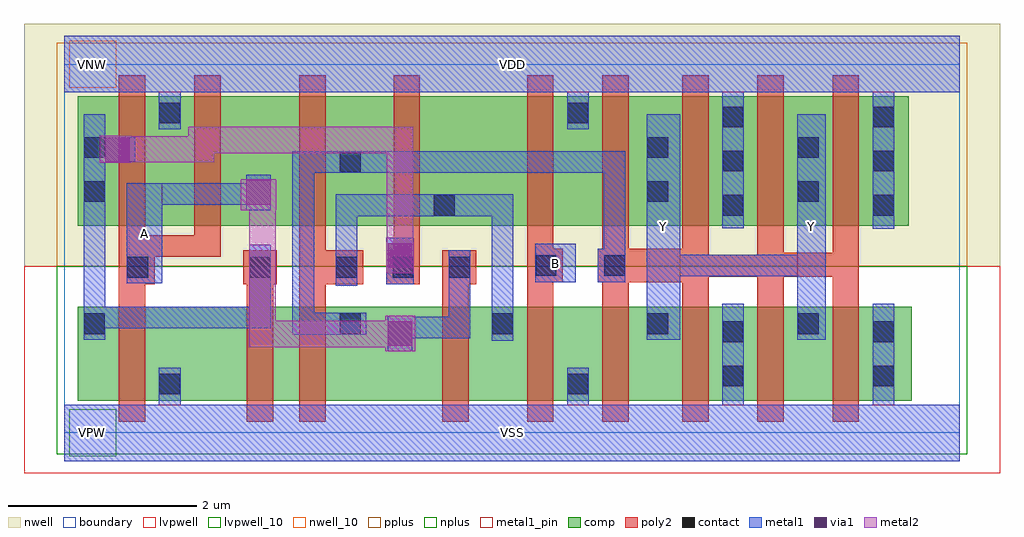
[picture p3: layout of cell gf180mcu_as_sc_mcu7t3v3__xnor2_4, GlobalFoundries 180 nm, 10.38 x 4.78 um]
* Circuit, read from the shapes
.subckt gf180mcu_as_sc_mcu7t3v3__xnor2_4 A B VDD VNW VSS Y
XM1 VSS A n1 VSUBS nfet_03v3 w=1u l=0.28u
XM2 n2 n1 VSS VSUBS nfet_03v3 w=1u l=0.28u
XM3 n3 n4 n2 VSUBS nfet_03v3 w=1u l=0.28u
XM4 n4 A n3 VSUBS nfet_03v3 w=1u l=0.28u
XM5 VSS B n4 VSUBS nfet_03v3 w=1u l=0.28u
XM6 Y n3 VSS VSUBS nfet_03v3 w=1u l=0.28u m=4
XM7 VDD A n1 VNW pfet_03v3 w=1.38u l=0.28u
XM8 n5 A VDD VNW pfet_03v3 w=1.38u l=0.28u
XM9 n3 n4 n5 VNW pfet_03v3 w=1.38u l=0.28u
XM10 n4 n1 n3 VNW pfet_03v3 w=1.38u l=0.28u
XM11 VDD B n4 VNW pfet_03v3 w=1.38u l=0.28u
XM12 Y n3 VDD VNW pfet_03v3 w=1.38u l=0.28u m=4
.ends

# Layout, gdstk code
import gdstk
lib = gdstk.Library(unit=1e-6, precision=1e-09)
def R(c, l, rs):  # rectangles x0, y0, x1, y1
    for r in rs: c.add(gdstk.rectangle(r[:2], r[2:], *l))
boundary = (0, 0)
nwell = (21, 0)
nwell_10 = (21, 10)
comp = (22, 0)
poly2 = (30, 0)
pplus = (31, 0)
nplus = (32, 0)
contact = (33, 0)
metal1 = (34, 0)
metal1_pin = (34, 10)
via1 = (35, 0)
metal2 = (36, 0)
lvpwell = (204, 0)
lvpwell_10 = (204, 10)

gf180mcu_as_sc_mcu7t3v3_ = lib.new_cell('gf180mcu_as_sc_mcu7t3v3__xnor2_4')
R(gf180mcu_as_sc_mcu7t3v3_, boundary, [(0,0,9.52,3.92), (0,0,9.52,3.92)])
R(gf180mcu_as_sc_mcu7t3v3_, nwell, [(-0.43,1.77,9.95,4.35), (-0.43,1.77,9.95,4.35)])
R(gf180mcu_as_sc_mcu7t3v3_, nwell_10, [(0.05,3.67,0.55,4.17), (0.05,3.67,0.55,4.17)])
R(gf180mcu_as_sc_mcu7t3v3_, comp, [(0.14,0.34,9.01,1.34), (0.14,0.34,9.01,1.34), (0.14,2.2,8.98,3.58), (0.14,2.2,8.98,3.58)])
R(gf180mcu_as_sc_mcu7t3v3_, poly2, [(0.58,0.12,0.86,1.58), (0.58,0.12,0.86,1.58), (1.94,0.12,2.22,1.58), (1.94,0.12,2.22,1.58), (2.5,0.12,2.78,1.58), (2.5,0.12,2.78,1.58), (4.02,0.12,4.3,1.58), (4.02,0.12,4.3,1.58), (4.92,0.12,5.2,1.6), (4.92,0.12,5.2,1.6), (5.72,0.12,6,1.6), (5.72,0.12,6,1.6), (6.57,0.12,6.85,1.6), (6.57,0.12,6.85,1.6), (7.37,0.12,7.65,1.66), (7.37,0.12,7.65,1.66), (8.17,0.12,8.45,1.66), (8.17,0.12,8.45,1.66), (0.58,1.58,0.96,1.87), (0.58,1.58,0.96,1.87), (1.9,1.58,2.26,1.94), (1.9,1.58,2.26,1.94), (2.5,1.58,3.18,1.94), (2.5,1.58,3.18,1.94), (3.42,1.58,3.78,1.94), (3.42,1.58,3.78,1.94), (4.02,1.58,4.38,1.94), (4.02,1.58,4.38,1.94), (4.92,1.6,5.3,1.96), (4.92,1.6,5.3,1.96), (5.67,1.6,6.85,1.66), (5.67,1.6,6.85,1.66), (5.67,1.66,8.45,1.895), (5.67,1.66,8.45,1.895), (0.58,1.87,1.66,2.1), (0.58,1.87,1.66,2.1), (5.67,1.895,6.85,1.96), (5.67,1.895,6.85,1.96), (7.37,1.895,8.45,1.915), (7.37,1.895,8.45,1.915), (7.37,1.915,7.65,3.8), (7.37,1.915,7.65,3.8), (8.17,1.915,8.45,3.8), (8.17,1.915,8.45,3.8), (2.5,1.94,2.78,3.8), (2.5,1.94,2.78,3.8), (3.5,1.94,3.78,3.8), (3.5,1.94,3.78,3.8), (4.92,1.96,5.2,3.8), (4.92,1.96,5.2,3.8), (5.72,1.96,6,3.8), (5.72,1.96,6,3.8), (6.57,1.96,6.85,3.8), (6.57,1.96,6.85,3.8), (0.58,2.1,0.86,3.8), (0.58,2.1,0.86,3.8), (1.38,2.1,1.66,3.8), (1.38,2.1,1.66,3.8)])
R(gf180mcu_as_sc_mcu7t3v3_, pplus, [(-0.08,1.77,9.6,4.15), (-0.08,1.77,9.6,4.15), (0.35,1.97,4.01,2.04), (0.35,1.97,4.01,2.04), (4.69,1.97,8.68,2.04), (4.69,1.97,8.68,2.04), (-0.02,2.04,9.14,3.74), (-0.02,2.04,9.14,3.74), (0.35,3.74,4.01,3.81), (0.35,3.74,4.01,3.81), (4.69,3.74,8.68,3.81), (4.69,3.74,8.68,3.81)])
R(gf180mcu_as_sc_mcu7t3v3_, nplus, [(-0.08,-0.23,9.6,1.77), (-0.08,-0.23,9.6,1.77), (-0.08,-0.23,9.6,1.77), (-0.08,-0.23,9.6,1.77)])
R(gf180mcu_as_sc_mcu7t3v3_, contact, [(1.01,0.41,1.23,0.63), (1.01,0.41,1.23,0.63), (5.35,0.41,5.57,0.63), (5.35,0.41,5.57,0.63), (7,0.495,7.22,0.715), (7,0.495,7.22,0.715), (8.6,0.495,8.82,0.715), (8.6,0.495,8.82,0.715), (7,0.965,7.22,1.185), (7,0.965,7.22,1.185), (8.6,0.965,8.82,1.185), (8.6,0.965,8.82,1.185), (0.21,1.05,0.43,1.27), (0.21,1.05,0.43,1.27), (2.93,1.05,3.15,1.27), (2.93,1.05,3.15,1.27), (4.55,1.05,4.77,1.27), (4.55,1.05,4.77,1.27), (6.2,1.05,6.42,1.27), (6.2,1.05,6.42,1.27), (7.8,1.05,8.02,1.27), (7.8,1.05,8.02,1.27), (0.67,1.65,0.89,1.87), (0.67,1.65,0.89,1.87), (1.97,1.65,2.19,1.87), (1.97,1.65,2.19,1.87), (2.89,1.65,3.11,1.87), (2.89,1.65,3.11,1.87), (3.49,1.65,3.71,1.87), (3.49,1.65,3.71,1.87), (4.09,1.65,4.31,1.87), (4.09,1.65,4.31,1.87), (5.01,1.67,5.23,1.89), (5.01,1.67,5.23,1.89), (5.74,1.67,5.96,1.89), (5.74,1.67,5.96,1.89), (3.93,2.31,4.15,2.53), (3.93,2.31,4.15,2.53), (7,2.31,7.22,2.53), (7,2.31,7.22,2.53), (8.6,2.31,8.82,2.53), (8.6,2.31,8.82,2.53), (0.21,2.455,0.43,2.675), (0.21,2.455,0.43,2.675), (6.2,2.455,6.42,2.675), (6.2,2.455,6.42,2.675), (7.8,2.455,8.02,2.675), (7.8,2.455,8.02,2.675), (2.93,2.77,3.15,2.99), (2.93,2.77,3.15,2.99), (7,2.78,7.22,3), (7,2.78,7.22,3), (8.6,2.78,8.82,3), (8.6,2.78,8.82,3), (0.21,2.925,0.43,3.145), (0.21,2.925,0.43,3.145), (6.2,2.925,6.42,3.145), (6.2,2.925,6.42,3.145), (7.8,2.925,8.02,3.145), (7.8,2.925,8.02,3.145), (7,3.25,7.22,3.47), (7,3.25,7.22,3.47), (8.6,3.25,8.82,3.47), (8.6,3.25,8.82,3.47), (1.01,3.29,1.23,3.51), (1.01,3.29,1.23,3.51), (5.35,3.29,5.57,3.51), (5.35,3.29,5.57,3.51)])
R(gf180mcu_as_sc_mcu7t3v3_, metal1, [(0,-0.3,9.52,0.3), (0,-0.3,9.52,0.3), (1.005,0.3,1.235,0.69), (1.005,0.3,1.235,0.69), (5.345,0.3,5.575,0.69), (5.345,0.3,5.575,0.69), (6.995,0.3,7.225,1.375), (6.995,0.3,7.225,1.375), (8.595,0.3,8.825,1.375), (8.595,0.3,8.825,1.375), (3.44,0.865,3.7,1.005), (3.44,0.865,3.7,1.005), (4.545,0.98,4.775,2.305), (4.545,0.98,4.775,2.305), (0.205,0.99,0.435,1.11), (0.205,0.99,0.435,1.11), (6.195,0.99,6.55,1.665), (6.195,0.99,6.55,1.665), (7.795,0.99,8.095,1.665), (7.795,0.99,8.095,1.665), (3.44,1.005,4.315,1.235), (3.44,1.005,4.315,1.235), (2.425,1.045,3.21,1.275), (2.425,1.045,3.21,1.275), (0.205,1.11,2.195,1.34), (0.205,1.11,2.195,1.34), (3.44,1.235,3.7,1.245), (3.44,1.235,3.7,1.245), (4.085,1.235,4.315,1.94), (4.085,1.235,4.315,1.94), (2.425,1.275,2.655,2.765), (2.425,1.275,2.655,2.765), (0.205,1.34,0.435,2.885), (0.205,1.34,0.435,2.885), (1.965,1.34,2.195,2), (1.965,1.34,2.195,2), (2.885,1.565,3.115,2.305), (2.885,1.565,3.115,2.305), (3.42,1.58,3.715,2.075), (3.42,1.58,3.715,2.075), (0.665,1.59,1.04,2.425), (0.665,1.59,1.04,2.425), (5.005,1.6,5.44,2.01), (5.005,1.6,5.44,2.01), (5.67,1.6,5.965,1.96), (5.67,1.6,5.965,1.96), (6.195,1.665,8.095,1.895), (6.195,1.665,8.095,1.895), (6.195,1.895,6.55,3.39), (6.195,1.895,6.55,3.39), (7.795,1.895,8.095,3.39), (7.795,1.895,8.095,3.39), (5.735,1.96,5.965,2.765), (5.735,1.96,5.965,2.765), (8.595,2.17,8.825,3.62), (8.595,2.17,8.825,3.62), (6.995,2.175,7.225,3.62), (6.995,2.175,7.225,3.62), (2.885,2.305,4.775,2.535), (2.885,2.305,4.775,2.535), (1.935,2.365,2.195,2.425), (1.935,2.365,2.195,2.425), (0.665,2.425,2.195,2.655), (0.665,2.425,2.195,2.655), (1.935,2.655,2.195,2.745), (1.935,2.655,2.195,2.745), (2.425,2.765,5.965,2.995), (2.425,2.765,5.965,2.995), (0.205,2.885,0.755,3.145), (0.205,2.885,0.755,3.145), (0.205,3.145,0.435,3.39), (0.205,3.145,0.435,3.39), (1.005,3.23,1.235,3.62), (1.005,3.23,1.235,3.62), (5.345,3.23,5.575,3.62), (5.345,3.23,5.575,3.62), (0,3.62,9.52,4.22), (0,3.62,9.52,4.22)])
R(gf180mcu_as_sc_mcu7t3v3_, metal1_pin, [(0,-0.3,9.52,0.3), (0,-0.3,9.52,0.3), (6.195,0.99,6.55,3.39), (6.195,0.99,6.55,3.39), (7.795,0.99,8.095,3.39), (7.795,0.99,8.095,3.39), (0.665,1.59,1.04,2.655), (0.665,1.59,1.04,2.655), (5.005,1.6,5.44,2.01), (5.005,1.6,5.44,2.01), (0,3.62,9.52,4.22), (0,3.62,9.52,4.22)])
R(gf180mcu_as_sc_mcu7t3v3_, via1, [(3.44,0.925,3.7,1.185), (3.44,0.925,3.7,1.185), (3.44,1.755,3.7,2.015), (3.44,1.755,3.7,2.015), (1.935,2.425,2.195,2.685), (1.935,2.425,2.195,2.685), (0.435,2.885,0.695,3.145), (0.435,2.885,0.695,3.145)])
R(gf180mcu_as_sc_mcu7t3v3_, metal2, [(3.41,0.865,3.73,0.91), (3.41,0.865,3.73,0.91), (1.965,0.91,3.73,1.19), (1.965,0.91,3.73,1.19), (1.965,1.19,2.245,2.365), (1.965,1.19,2.245,2.365), (3.41,1.19,3.73,1.245), (3.41,1.19,3.73,1.245), (3.42,1.695,3.715,2.03), (3.42,1.695,3.715,2.03), (3.43,2.03,3.71,2.975), (3.43,2.03,3.71,2.975), (1.875,2.365,2.255,2.695), (1.875,2.365,2.255,2.695), (0.375,2.87,0.71,2.875), (0.375,2.87,0.71,2.875), (0.375,2.875,1.595,2.975), (0.375,2.875,1.595,2.975), (0.375,2.975,3.71,3.155), (0.375,2.975,3.71,3.155), (0.375,3.155,0.71,3.16), (0.375,3.155,0.71,3.16), (1.315,3.155,3.71,3.255), (1.315,3.155,3.71,3.255)])
R(gf180mcu_as_sc_mcu7t3v3_, lvpwell, [(-0.43,-0.43,9.95,1.77), (-0.43,-0.43,9.95,1.77)])
R(gf180mcu_as_sc_mcu7t3v3_, lvpwell_10, [(0.05,-0.25,0.55,0.25), (0.05,-0.25,0.55,0.25)])
gf180mcu_as_sc_mcu7t3v3_.add(gdstk.Label('VDD', (4.76,3.92), layer=34, texttype=10))
gf180mcu_as_sc_mcu7t3v3_.add(gdstk.Label('VSS', (4.76,0), layer=34, texttype=10))
gf180mcu_as_sc_mcu7t3v3_.add(gdstk.Label('B', (5.222,1.805), layer=34, texttype=10))
gf180mcu_as_sc_mcu7t3v3_.add(gdstk.Label('A', (0.852,2.122), layer=34, texttype=10))
gf180mcu_as_sc_mcu7t3v3_.add(gdstk.Label('Y', (7.945,2.19), layer=34, texttype=10))
gf180mcu_as_sc_mcu7t3v3_.add(gdstk.Label('Y', (6.372,2.19), layer=34, texttype=10))
gf180mcu_as_sc_mcu7t3v3_.add(gdstk.Label('VDD', (4.76,3.92), layer=34, texttype=10))
gf180mcu_as_sc_mcu7t3v3_.add(gdstk.Label('VSS', (4.76,0), layer=34, texttype=10))
gf180mcu_as_sc_mcu7t3v3_.add(gdstk.Label('B', (5.222,1.805), layer=34, texttype=10))
gf180mcu_as_sc_mcu7t3v3_.add(gdstk.Label('A', (0.852,2.122), layer=34, texttype=10))
gf180mcu_as_sc_mcu7t3v3_.add(gdstk.Label('Y', (7.945,2.19), layer=34, texttype=10))
gf180mcu_as_sc_mcu7t3v3_.add(gdstk.Label('Y', (6.372,2.19), layer=34, texttype=10))
gf180mcu_as_sc_mcu7t3v3_.add(gdstk.Label('VNW', (0.3,3.92), layer=21, texttype=10))
gf180mcu_as_sc_mcu7t3v3_.add(gdstk.Label('VNW', (0.3,3.92), layer=21, texttype=10))
gf180mcu_as_sc_mcu7t3v3_.add(gdstk.Label('VPW', (0.3,0), layer=204, texttype=10))
gf180mcu_as_sc_mcu7t3v3_.add(gdstk.Label('VPW', (0.3,0), layer=204, texttype=10))

lib.write_gds('gf180mcu_as_sc_mcu7t3v3__xnor2_4.gds')
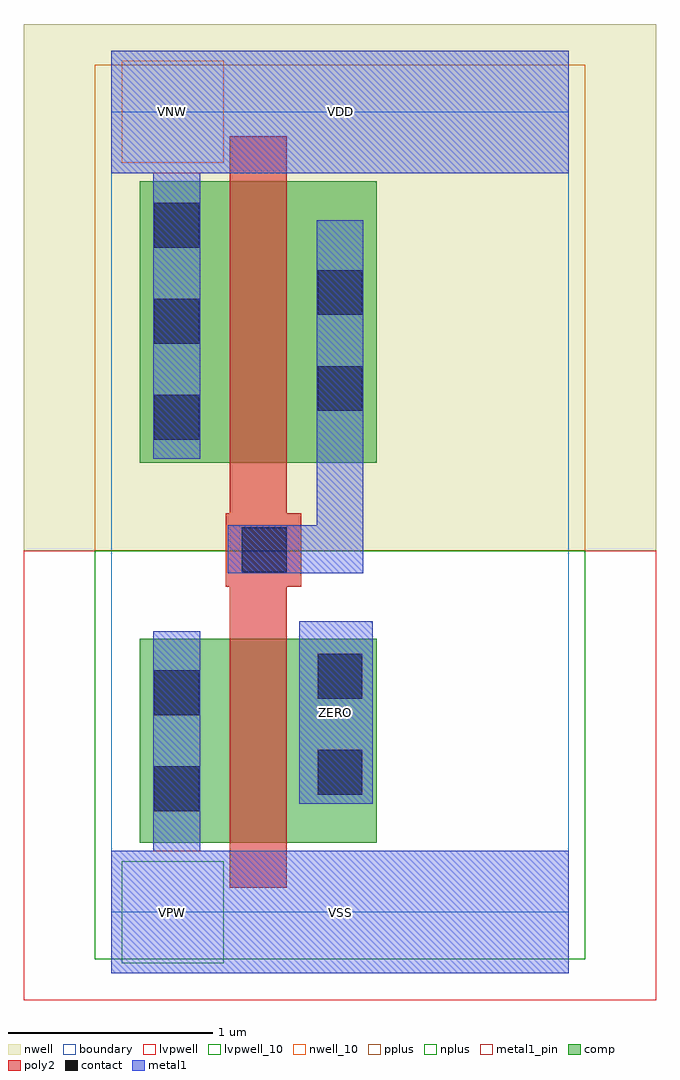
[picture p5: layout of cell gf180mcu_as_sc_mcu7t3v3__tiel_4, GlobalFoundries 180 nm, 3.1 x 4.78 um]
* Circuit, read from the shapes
.subckt gf180mcu_as_sc_mcu7t3v3__tiel_4 VDD VNW VSS ZERO
XM1 ZERO n1 VSS VSUBS nfet_03v3 w=1u l=0.28u
XM2 n1 n1 VDD VNW pfet_03v3 w=1.38u l=0.28u
.ends

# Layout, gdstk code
import gdstk
lib = gdstk.Library(unit=1e-6, precision=1e-09)
def R(c, l, rs):  # rectangles x0, y0, x1, y1
    for r in rs: c.add(gdstk.rectangle(r[:2], r[2:], *l))
boundary = (0, 0)
nwell = (21, 0)
nwell_10 = (21, 10)
comp = (22, 0)
poly2 = (30, 0)
pplus = (31, 0)
nplus = (32, 0)
contact = (33, 0)
metal1 = (34, 0)
metal1_pin = (34, 10)
lvpwell = (204, 0)
lvpwell_10 = (204, 10)

gf180mcu_as_sc_mcu7t3v3_ = lib.new_cell('gf180mcu_as_sc_mcu7t3v3__tiel_4')
R(gf180mcu_as_sc_mcu7t3v3_, boundary, [(0,0,2.24,3.92), (0,0,2.24,3.92)])
R(gf180mcu_as_sc_mcu7t3v3_, nwell, [(-0.43,1.77,2.67,4.35), (-0.43,1.77,2.67,4.35)])
R(gf180mcu_as_sc_mcu7t3v3_, nwell_10, [(0.05,3.67,0.55,4.17), (0.05,3.67,0.55,4.17)])
R(gf180mcu_as_sc_mcu7t3v3_, comp, [(0.14,0.34,1.3,1.34), (0.14,0.34,1.3,1.34), (0.14,2.2,1.3,3.58), (0.14,2.2,1.3,3.58)])
R(gf180mcu_as_sc_mcu7t3v3_, poly2, [(0.58,0.12,0.86,1.595), (0.58,0.12,0.86,1.595), (0.56,1.595,0.93,1.955), (0.56,1.595,0.93,1.955), (0.58,1.955,0.86,3.8), (0.58,1.955,0.86,3.8)])
R(gf180mcu_as_sc_mcu7t3v3_, pplus, [(-0.08,1.77,2.32,4.15), (-0.08,1.77,2.32,4.15), (0.35,1.97,1.09,2.04), (0.35,1.97,1.09,2.04), (-0.02,2.04,1.46,3.74), (-0.02,2.04,1.46,3.74), (0.35,3.74,1.09,3.81), (0.35,3.74,1.09,3.81)])
R(gf180mcu_as_sc_mcu7t3v3_, nplus, [(-0.08,-0.23,2.32,1.77), (-0.08,-0.23,2.32,1.77), (-0.08,-0.23,2.32,1.77), (-0.08,-0.23,2.32,1.77)])
R(gf180mcu_as_sc_mcu7t3v3_, contact, [(0.21,0.495,0.43,0.715), (0.21,0.495,0.43,0.715), (1.01,0.575,1.23,0.795), (1.01,0.575,1.23,0.795), (0.21,0.965,0.43,1.185), (0.21,0.965,0.43,1.185), (1.01,1.045,1.23,1.265), (1.01,1.045,1.23,1.265), (0.64,1.665,0.86,1.885), (0.64,1.665,0.86,1.885), (0.21,2.315,0.43,2.535), (0.21,2.315,0.43,2.535), (1.01,2.455,1.23,2.675), (1.01,2.455,1.23,2.675), (0.21,2.785,0.43,3.005), (0.21,2.785,0.43,3.005), (1.01,2.925,1.23,3.145), (1.01,2.925,1.23,3.145), (0.21,3.255,0.43,3.475), (0.21,3.255,0.43,3.475)])
R(gf180mcu_as_sc_mcu7t3v3_, metal1, [(0,-0.3,2.24,0.3), (0,-0.3,2.24,0.3), (0.205,0.3,0.435,1.375), (0.205,0.3,0.435,1.375), (0.92,0.53,1.28,1.425), (0.92,0.53,1.28,1.425), (0.57,1.66,1.235,1.895), (0.57,1.66,1.235,1.895), (1.005,1.895,1.235,3.39), (1.005,1.895,1.235,3.39), (0.205,2.22,0.435,3.62), (0.205,2.22,0.435,3.62), (0,3.62,2.24,4.22), (0,3.62,2.24,4.22)])
R(gf180mcu_as_sc_mcu7t3v3_, metal1_pin, [(0,-0.3,2.24,0.3), (0,-0.3,2.24,0.3), (0.92,0.53,1.28,1.425), (0.92,0.53,1.28,1.425), (0,3.62,2.24,4.22), (0,3.62,2.24,4.22)])
R(gf180mcu_as_sc_mcu7t3v3_, lvpwell, [(-0.43,-0.43,2.67,1.77), (-0.43,-0.43,2.67,1.77)])
R(gf180mcu_as_sc_mcu7t3v3_, lvpwell_10, [(0.05,-0.25,0.55,0.25), (0.05,-0.25,0.55,0.25)])
gf180mcu_as_sc_mcu7t3v3_.add(gdstk.Label('VDD', (1.12,3.92), layer=34, texttype=10))
gf180mcu_as_sc_mcu7t3v3_.add(gdstk.Label('VSS', (1.12,0), layer=34, texttype=10))
gf180mcu_as_sc_mcu7t3v3_.add(gdstk.Label('ZERO', (1.1,0.977), layer=34, texttype=10))
gf180mcu_as_sc_mcu7t3v3_.add(gdstk.Label('VDD', (1.12,3.92), layer=34, texttype=10))
gf180mcu_as_sc_mcu7t3v3_.add(gdstk.Label('VSS', (1.12,0), layer=34, texttype=10))
gf180mcu_as_sc_mcu7t3v3_.add(gdstk.Label('ZERO', (1.1,0.977), layer=34, texttype=10))
gf180mcu_as_sc_mcu7t3v3_.add(gdstk.Label('VNW', (0.3,3.92), layer=21, texttype=10))
gf180mcu_as_sc_mcu7t3v3_.add(gdstk.Label('VNW', (0.3,3.92), layer=21, texttype=10))
gf180mcu_as_sc_mcu7t3v3_.add(gdstk.Label('VPW', (0.3,0), layer=204, texttype=10))
gf180mcu_as_sc_mcu7t3v3_.add(gdstk.Label('VPW', (0.3,0), layer=204, texttype=10))

lib.write_gds('gf180mcu_as_sc_mcu7t3v3__tiel_4.gds')
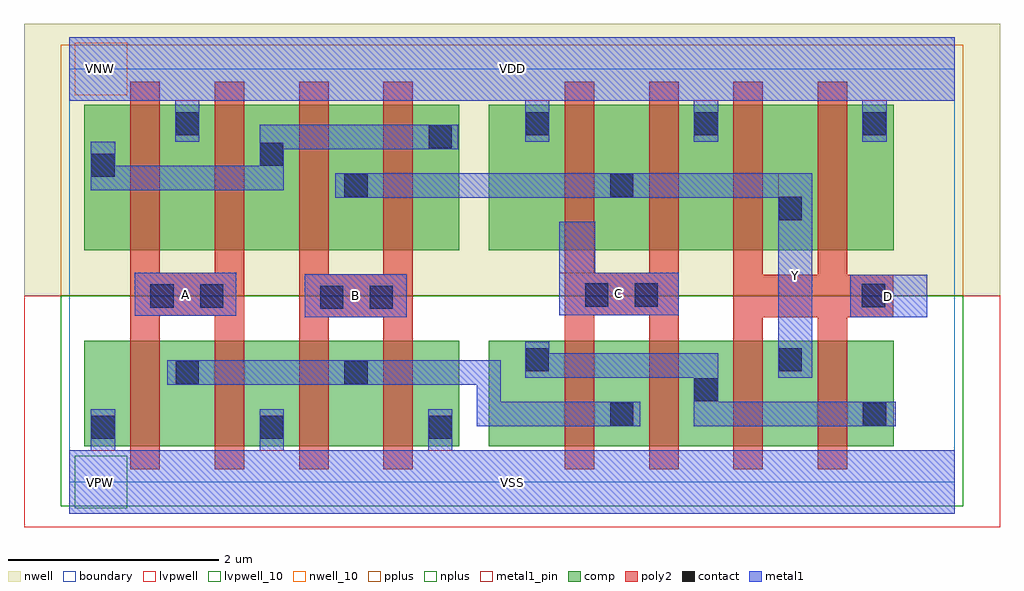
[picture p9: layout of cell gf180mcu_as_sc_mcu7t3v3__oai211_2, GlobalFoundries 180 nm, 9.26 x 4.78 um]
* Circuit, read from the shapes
.subckt gf180mcu_as_sc_mcu7t3v3__oai211_2 A B C D VDD VNW VSS Y
XM1 n1 A VSS VSUBS nfet_03v3 w=1u l=0.28u m=2
XM2 n1 B VSS VSUBS nfet_03v3 w=1u l=0.28u m=2
XM3 n1 C n2 VSUBS nfet_03v3 w=1u l=0.28u m=2
XM4 Y D n2 VSUBS nfet_03v3 w=1u l=0.28u m=2
XM5 VDD A n3 VNW pfet_03v3 w=1.38u l=0.28u m=2
XM6 Y B n3 VNW pfet_03v3 w=1.38u l=0.28u m=2
XM7 Y C VDD VNW pfet_03v3 w=1.38u l=0.28u m=2
XM8 Y D VDD VNW pfet_03v3 w=1.38u l=0.28u m=2
.ends

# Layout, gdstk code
import gdstk
lib = gdstk.Library(unit=1e-6, precision=1e-09)
def R(c, l, rs):  # rectangles x0, y0, x1, y1
    for r in rs: c.add(gdstk.rectangle(r[:2], r[2:], *l))
boundary = (0, 0)
nwell = (21, 0)
nwell_10 = (21, 10)
comp = (22, 0)
poly2 = (30, 0)
pplus = (31, 0)
nplus = (32, 0)
contact = (33, 0)
metal1 = (34, 0)
metal1_pin = (34, 10)
lvpwell = (204, 0)
lvpwell_10 = (204, 10)

gf180mcu_as_sc_mcu7t3v3_ = lib.new_cell('gf180mcu_as_sc_mcu7t3v3__oai211_2')
R(gf180mcu_as_sc_mcu7t3v3_, boundary, [(0,0,8.4,3.92), (0,0,8.4,3.92)])
R(gf180mcu_as_sc_mcu7t3v3_, nwell, [(-0.43,1.77,8.83,4.35), (-0.43,1.77,8.83,4.35)])
R(gf180mcu_as_sc_mcu7t3v3_, nwell_10, [(0.05,3.67,0.55,4.17), (0.05,3.67,0.55,4.17)])
R(gf180mcu_as_sc_mcu7t3v3_, comp, [(0.14,0.34,3.7,1.34), (0.14,0.34,3.7,1.34), (3.98,0.34,7.82,1.34), (3.98,0.34,7.82,1.34), (0.14,2.2,3.7,3.58), (0.14,2.2,3.7,3.58), (3.98,2.2,7.82,3.58), (3.98,2.2,7.82,3.58)])
R(gf180mcu_as_sc_mcu7t3v3_, poly2, [(0.58,0.12,0.86,1.58), (0.58,0.12,0.86,1.58), (1.38,0.12,1.66,1.58), (1.38,0.12,1.66,1.58), (2.18,0.12,2.46,1.565), (2.18,0.12,2.46,1.565), (2.98,0.12,3.26,1.565), (2.98,0.12,3.26,1.565), (4.7,0.12,4.98,1.585), (4.7,0.12,4.98,1.585), (5.5,0.12,5.78,1.585), (5.5,0.12,5.78,1.585), (6.3,0.12,6.58,1.565), (6.3,0.12,6.58,1.565), (7.1,0.12,7.38,1.565), (7.1,0.12,7.38,1.565), (2.18,1.565,3.26,1.97), (2.18,1.565,3.26,1.97), (6.3,1.565,7.815,1.965), (6.3,1.565,7.815,1.965), (0.58,1.58,1.66,1.985), (0.58,1.58,1.66,1.985), (4.7,1.585,5.78,1.985), (4.7,1.585,5.78,1.985), (6.3,1.965,6.58,3.8), (6.3,1.965,6.58,3.8), (7.1,1.965,7.38,3.8), (7.1,1.965,7.38,3.8), (2.18,1.97,2.46,3.8), (2.18,1.97,2.46,3.8), (2.98,1.97,3.26,3.8), (2.98,1.97,3.26,3.8), (0.58,1.985,0.86,3.8), (0.58,1.985,0.86,3.8), (1.38,1.985,1.66,3.8), (1.38,1.985,1.66,3.8), (4.7,1.985,4.98,3.8), (4.7,1.985,4.98,3.8), (5.5,1.985,5.78,3.8), (5.5,1.985,5.78,3.8)])
R(gf180mcu_as_sc_mcu7t3v3_, pplus, [(-0.08,1.77,8.48,4.15), (-0.08,1.77,8.48,4.15), (0.35,1.97,3.49,2.04), (0.35,1.97,3.49,2.04), (4.47,1.97,7.61,2.04), (4.47,1.97,7.61,2.04), (-0.02,2.04,7.98,3.74), (-0.02,2.04,7.98,3.74), (0.35,3.74,3.49,3.81), (0.35,3.74,3.49,3.81), (4.47,3.74,7.61,3.81), (4.47,3.74,7.61,3.81)])
R(gf180mcu_as_sc_mcu7t3v3_, nplus, [(-0.08,-0.23,8.48,1.77), (-0.08,-0.23,8.48,1.77), (-0.08,-0.23,8.48,1.77), (-0.08,-0.23,8.48,1.77)])
R(gf180mcu_as_sc_mcu7t3v3_, contact, [(0.21,0.41,0.43,0.63), (0.21,0.41,0.43,0.63), (1.81,0.41,2.03,0.63), (1.81,0.41,2.03,0.63), (3.41,0.41,3.63,0.63), (3.41,0.41,3.63,0.63), (5.13,0.535,5.35,0.755), (5.13,0.535,5.35,0.755), (7.53,0.535,7.75,0.755), (7.53,0.535,7.75,0.755), (5.93,0.765,6.15,0.985), (5.93,0.765,6.15,0.985), (1.01,0.93,1.23,1.15), (1.01,0.93,1.23,1.15), (2.61,0.93,2.83,1.15), (2.61,0.93,2.83,1.15), (4.33,1.05,4.55,1.27), (4.33,1.05,4.55,1.27), (6.73,1.05,6.95,1.27), (6.73,1.05,6.95,1.27), (2.38,1.645,2.6,1.865), (2.38,1.645,2.6,1.865), (2.85,1.645,3.07,1.865), (2.85,1.645,3.07,1.865), (0.77,1.655,0.99,1.875), (0.77,1.655,0.99,1.875), (1.24,1.655,1.46,1.875), (1.24,1.655,1.46,1.875), (7.52,1.66,7.74,1.88), (7.52,1.66,7.74,1.88), (4.895,1.665,5.115,1.885), (4.895,1.665,5.115,1.885), (5.365,1.665,5.585,1.885), (5.365,1.665,5.585,1.885), (6.73,2.485,6.95,2.705), (6.73,2.485,6.95,2.705), (2.61,2.705,2.83,2.925), (2.61,2.705,2.83,2.925), (5.13,2.705,5.35,2.925), (5.13,2.705,5.35,2.925), (0.21,2.895,0.43,3.115), (0.21,2.895,0.43,3.115), (1.81,3,2.03,3.22), (1.81,3,2.03,3.22), (3.41,3.165,3.63,3.385), (3.41,3.165,3.63,3.385), (1.01,3.29,1.23,3.51), (1.01,3.29,1.23,3.51), (4.33,3.29,4.55,3.51), (4.33,3.29,4.55,3.51), (5.93,3.29,6.15,3.51), (5.93,3.29,6.15,3.51), (7.53,3.29,7.75,3.51), (7.53,3.29,7.75,3.51)])
R(gf180mcu_as_sc_mcu7t3v3_, metal1, [(0,-0.3,8.4,0.3), (0,-0.3,8.4,0.3), (0.205,0.3,0.435,0.69), (0.205,0.3,0.435,0.69), (1.805,0.3,2.035,0.69), (1.805,0.3,2.035,0.69), (3.405,0.3,3.635,0.69), (3.405,0.3,3.635,0.69), (3.865,0.53,5.415,0.76), (3.865,0.53,5.415,0.76), (5.925,0.53,7.84,0.76), (5.925,0.53,7.84,0.76), (3.865,0.76,4.095,0.925), (3.865,0.76,4.095,0.925), (5.925,0.76,6.155,0.99), (5.925,0.76,6.155,0.99), (0.93,0.925,4.095,1.155), (0.93,0.925,4.095,1.155), (4.325,0.99,6.155,1.22), (4.325,0.99,6.155,1.22), (6.725,0.99,7.05,2.7), (6.725,0.99,7.05,2.7), (4.325,1.22,4.555,1.33), (4.325,1.22,4.555,1.33), (2.235,1.565,3.2,1.97), (2.235,1.565,3.2,1.97), (7.41,1.565,8.14,1.965), (7.41,1.565,8.14,1.965), (0.62,1.58,1.585,1.985), (0.62,1.58,1.585,1.985), (4.65,1.585,5.78,1.985), (4.65,1.585,5.78,1.985), (4.65,1.985,4.99,2.47), (4.65,1.985,4.99,2.47), (2.525,2.7,7.05,2.93), (2.525,2.7,7.05,2.93), (0.205,2.77,2.035,3), (0.205,2.77,2.035,3), (0.205,3,0.435,3.23), (0.205,3,0.435,3.23), (1.805,3,2.035,3.16), (1.805,3,2.035,3.16), (1.805,3.16,3.69,3.39), (1.805,3.16,3.69,3.39), (1.005,3.23,1.235,3.62), (1.005,3.23,1.235,3.62), (4.325,3.23,4.555,3.62), (4.325,3.23,4.555,3.62), (5.925,3.23,6.155,3.62), (5.925,3.23,6.155,3.62), (7.525,3.23,7.755,3.62), (7.525,3.23,7.755,3.62), (0,3.62,8.4,4.22), (0,3.62,8.4,4.22)])
R(gf180mcu_as_sc_mcu7t3v3_, metal1_pin, [(0,-0.3,8.4,0.3), (0,-0.3,8.4,0.3), (6.725,0.99,7.05,2.93), (6.725,0.99,7.05,2.93), (2.235,1.565,3.2,1.97), (2.235,1.565,3.2,1.97), (7.41,1.565,8.14,1.965), (7.41,1.565,8.14,1.965), (0.62,1.58,1.585,1.985), (0.62,1.58,1.585,1.985), (4.65,1.585,5.78,1.985), (4.65,1.585,5.78,1.985), (0,3.62,8.4,4.22), (0,3.62,8.4,4.22)])
R(gf180mcu_as_sc_mcu7t3v3_, lvpwell, [(-0.43,-0.43,8.83,1.77), (-0.43,-0.43,8.83,1.77)])
R(gf180mcu_as_sc_mcu7t3v3_, lvpwell_10, [(0.05,-0.25,0.55,0.25), (0.05,-0.25,0.55,0.25)])
gf180mcu_as_sc_mcu7t3v3_.add(gdstk.Label('VDD', (4.2,3.92), layer=34, texttype=10))
gf180mcu_as_sc_mcu7t3v3_.add(gdstk.Label('VSS', (4.2,0), layer=34, texttype=10))
gf180mcu_as_sc_mcu7t3v3_.add(gdstk.Label('A', (1.102,1.782), layer=34, texttype=10))
gf180mcu_as_sc_mcu7t3v3_.add(gdstk.Label('B', (2.717,1.767), layer=34, texttype=10))
gf180mcu_as_sc_mcu7t3v3_.add(gdstk.Label('C', (5.215,1.785), layer=34, texttype=10))
gf180mcu_as_sc_mcu7t3v3_.add(gdstk.Label('Y', (6.887,1.96), layer=34, texttype=10))
gf180mcu_as_sc_mcu7t3v3_.add(gdstk.Label('D', (7.775,1.765), layer=34, texttype=10))
gf180mcu_as_sc_mcu7t3v3_.add(gdstk.Label('VDD', (4.2,3.92), layer=34, texttype=10))
gf180mcu_as_sc_mcu7t3v3_.add(gdstk.Label('VSS', (4.2,0), layer=34, texttype=10))
gf180mcu_as_sc_mcu7t3v3_.add(gdstk.Label('A', (1.102,1.782), layer=34, texttype=10))
gf180mcu_as_sc_mcu7t3v3_.add(gdstk.Label('B', (2.717,1.767), layer=34, texttype=10))
gf180mcu_as_sc_mcu7t3v3_.add(gdstk.Label('C', (5.215,1.785), layer=34, texttype=10))
gf180mcu_as_sc_mcu7t3v3_.add(gdstk.Label('Y', (6.887,1.96), layer=34, texttype=10))
gf180mcu_as_sc_mcu7t3v3_.add(gdstk.Label('D', (7.775,1.765), layer=34, texttype=10))
gf180mcu_as_sc_mcu7t3v3_.add(gdstk.Label('VNW', (0.3,3.92), layer=21, texttype=10))
gf180mcu_as_sc_mcu7t3v3_.add(gdstk.Label('VNW', (0.3,3.92), layer=21, texttype=10))
gf180mcu_as_sc_mcu7t3v3_.add(gdstk.Label('VPW', (0.3,0), layer=204, texttype=10))
gf180mcu_as_sc_mcu7t3v3_.add(gdstk.Label('VPW', (0.3,0), layer=204, texttype=10))

lib.write_gds('gf180mcu_as_sc_mcu7t3v3__oai211_2.gds')
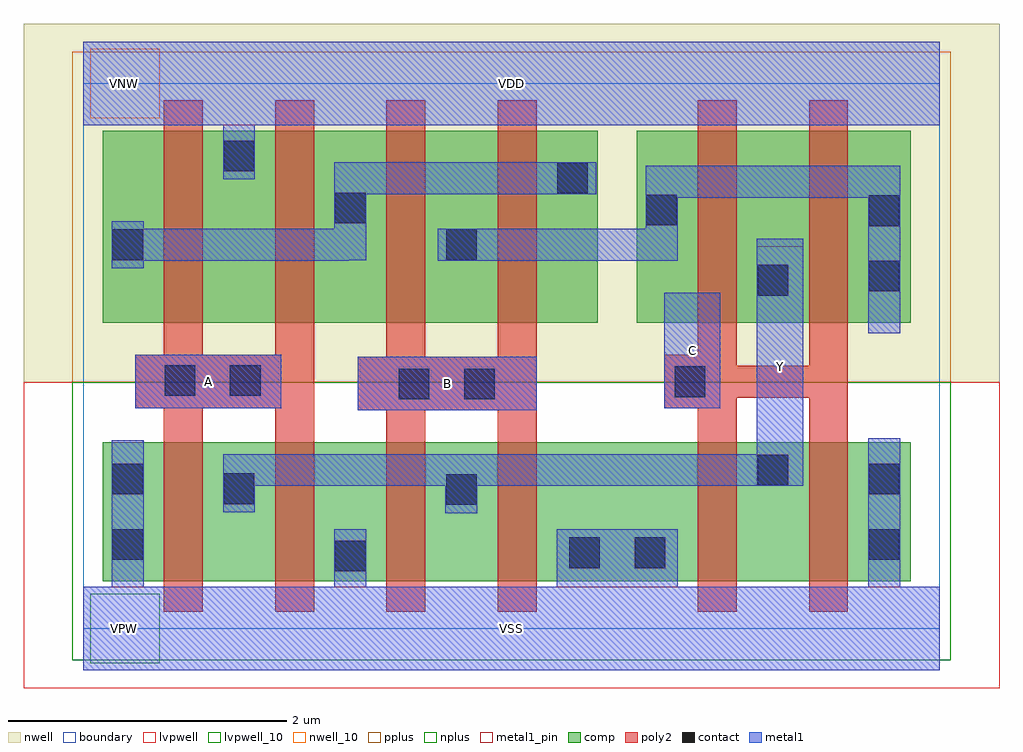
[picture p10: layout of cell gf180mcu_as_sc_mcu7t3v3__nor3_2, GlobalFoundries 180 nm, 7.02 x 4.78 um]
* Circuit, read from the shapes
.subckt gf180mcu_as_sc_mcu7t3v3__nor3_2 A B C VDD VNW VSS Y
XM1 Y A VSS VSUBS nfet_03v3 w=1u l=0.28u m=2
XM2 Y B VSS VSUBS nfet_03v3 w=1u l=0.28u m=2
XM3 Y C VSS VSUBS nfet_03v3 w=1u l=0.28u m=2
XM4 VDD A n1 VNW pfet_03v3 w=1.38u l=0.28u m=2
XM5 n2 B n1 VNW pfet_03v3 w=1.38u l=0.28u m=2
XM6 Y C n2 VNW pfet_03v3 w=1.38u l=0.28u m=2
.ends

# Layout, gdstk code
import gdstk
lib = gdstk.Library(unit=1e-6, precision=1e-09)
def R(c, l, rs):  # rectangles x0, y0, x1, y1
    for r in rs: c.add(gdstk.rectangle(r[:2], r[2:], *l))
boundary = (0, 0)
nwell = (21, 0)
nwell_10 = (21, 10)
comp = (22, 0)
poly2 = (30, 0)
pplus = (31, 0)
nplus = (32, 0)
contact = (33, 0)
metal1 = (34, 0)
metal1_pin = (34, 10)
lvpwell = (204, 0)
lvpwell_10 = (204, 10)

gf180mcu_as_sc_mcu7t3v3_ = lib.new_cell('gf180mcu_as_sc_mcu7t3v3__nor3_2')
R(gf180mcu_as_sc_mcu7t3v3_, boundary, [(0,0,6.16,3.92), (0,0,6.16,3.92)])
R(gf180mcu_as_sc_mcu7t3v3_, nwell, [(-0.43,1.77,6.59,4.35), (-0.43,1.77,6.59,4.35)])
R(gf180mcu_as_sc_mcu7t3v3_, nwell_10, [(0.05,3.67,0.55,4.17), (0.05,3.67,0.55,4.17)])
R(gf180mcu_as_sc_mcu7t3v3_, comp, [(0.14,0.34,5.95,1.34), (0.14,0.34,5.95,1.34), (0.14,2.2,3.7,3.58), (0.14,2.2,3.7,3.58), (3.98,2.2,5.95,3.58), (3.98,2.2,5.95,3.58)])
R(gf180mcu_as_sc_mcu7t3v3_, poly2, [(0.58,0.12,0.86,1.585), (0.58,0.12,0.86,1.585), (1.38,0.12,1.66,1.585), (1.38,0.12,1.66,1.585), (2.18,0.12,2.46,1.57), (2.18,0.12,2.46,1.57), (2.98,0.12,3.26,1.57), (2.98,0.12,3.26,1.57), (4.42,0.12,4.7,1.585), (4.42,0.12,4.7,1.585), (5.22,0.12,5.5,1.66), (5.22,0.12,5.5,1.66), (1.975,1.57,3.26,1.955), (1.975,1.57,3.26,1.955), (0.375,1.585,1.66,1.97), (0.375,1.585,1.66,1.97), (4.18,1.585,4.7,1.66), (4.18,1.585,4.7,1.66), (4.18,1.66,5.5,1.89), (4.18,1.66,5.5,1.89), (4.18,1.89,4.7,1.97), (4.18,1.89,4.7,1.97), (5.22,1.89,5.5,3.8), (5.22,1.89,5.5,3.8), (2.18,1.955,2.46,3.8), (2.18,1.955,2.46,3.8), (2.98,1.955,3.26,3.8), (2.98,1.955,3.26,3.8), (0.58,1.97,0.86,3.8), (0.58,1.97,0.86,3.8), (1.38,1.97,1.66,3.8), (1.38,1.97,1.66,3.8), (4.42,1.97,4.7,3.8), (4.42,1.97,4.7,3.8)])
R(gf180mcu_as_sc_mcu7t3v3_, pplus, [(-0.08,1.77,6.24,4.15), (-0.08,1.77,6.24,4.15), (0.35,1.97,3.49,2.04), (0.35,1.97,3.49,2.04), (4.19,1.97,5.73,2.04), (4.19,1.97,5.73,2.04), (-0.02,2.04,6.11,3.74), (-0.02,2.04,6.11,3.74), (0.35,3.74,3.49,3.81), (0.35,3.74,3.49,3.81), (4.19,3.74,5.73,3.81), (4.19,3.74,5.73,3.81)])
R(gf180mcu_as_sc_mcu7t3v3_, nplus, [(-0.08,-0.23,6.24,1.77), (-0.08,-0.23,6.24,1.77), (-0.08,-0.23,6.24,1.77), (-0.08,-0.23,6.24,1.77)])
R(gf180mcu_as_sc_mcu7t3v3_, contact, [(1.81,0.41,2.03,0.63), (1.81,0.41,2.03,0.63), (3.495,0.435,3.715,0.655), (3.495,0.435,3.715,0.655), (3.965,0.435,4.185,0.655), (3.965,0.435,4.185,0.655), (0.21,0.495,0.43,0.715), (0.21,0.495,0.43,0.715), (5.65,0.495,5.87,0.715), (5.65,0.495,5.87,0.715), (2.61,0.89,2.83,1.11), (2.61,0.89,2.83,1.11), (1.01,0.895,1.23,1.115), (1.01,0.895,1.23,1.115), (0.21,0.965,0.43,1.185), (0.21,0.965,0.43,1.185), (5.65,0.965,5.87,1.185), (5.65,0.965,5.87,1.185), (4.85,1.03,5.07,1.25), (4.85,1.03,5.07,1.25), (2.27,1.65,2.49,1.87), (2.27,1.65,2.49,1.87), (2.74,1.65,2.96,1.87), (2.74,1.65,2.96,1.87), (4.255,1.665,4.475,1.885), (4.255,1.665,4.475,1.885), (0.585,1.675,0.805,1.895), (0.585,1.675,0.805,1.895), (1.055,1.675,1.275,1.895), (1.055,1.675,1.275,1.895), (4.85,2.395,5.07,2.615), (4.85,2.395,5.07,2.615), (5.65,2.425,5.87,2.645), (5.65,2.425,5.87,2.645), (0.21,2.65,0.43,2.87), (0.21,2.65,0.43,2.87), (2.61,2.65,2.83,2.87), (2.61,2.65,2.83,2.87), (5.65,2.895,5.87,3.115), (5.65,2.895,5.87,3.115), (4.05,2.9,4.27,3.12), (4.05,2.9,4.27,3.12), (1.81,2.915,2.03,3.135), (1.81,2.915,2.03,3.135), (3.41,3.13,3.63,3.35), (3.41,3.13,3.63,3.35), (1.01,3.29,1.23,3.51), (1.01,3.29,1.23,3.51)])
R(gf180mcu_as_sc_mcu7t3v3_, metal1, [(0,-0.3,6.16,0.3), (0,-0.3,6.16,0.3), (0.205,0.3,0.435,1.355), (0.205,0.3,0.435,1.355), (1.805,0.3,2.035,0.715), (1.805,0.3,2.035,0.715), (3.405,0.3,4.275,0.715), (3.405,0.3,4.275,0.715), (5.645,0.3,5.875,1.37), (5.645,0.3,5.875,1.37), (2.605,0.83,2.835,1.025), (2.605,0.83,2.835,1.025), (1.005,0.835,1.235,1.025), (1.005,0.835,1.235,1.025), (1.005,1.025,5.18,1.255), (1.005,1.025,5.18,1.255), (4.845,1.255,5.18,2.805), (4.845,1.255,5.18,2.805), (1.975,1.57,3.26,1.955), (1.975,1.57,3.26,1.955), (0.375,1.585,1.425,1.97), (0.375,1.585,1.425,1.97), (4.18,1.585,4.58,2.415), (4.18,1.585,4.58,2.415), (5.645,2.125,5.875,3.1), (5.645,2.125,5.875,3.1), (0.205,2.59,0.435,2.645), (0.205,2.59,0.435,2.645), (0.205,2.645,1.91,2.65), (0.205,2.645,1.91,2.65), (2.55,2.645,4.275,2.875), (2.55,2.645,4.275,2.875), (0.205,2.65,2.035,2.875), (0.205,2.65,2.035,2.875), (0.205,2.875,0.435,2.93), (0.205,2.875,0.435,2.93), (1.805,2.875,2.035,3.125), (1.805,2.875,2.035,3.125), (4.045,2.875,4.275,3.1), (4.045,2.875,4.275,3.1), (4.045,3.1,5.875,3.33), (4.045,3.1,5.875,3.33), (1.805,3.125,3.69,3.355), (1.805,3.125,3.69,3.355), (1.005,3.23,1.235,3.62), (1.005,3.23,1.235,3.62), (0,3.62,6.16,4.22), (0,3.62,6.16,4.22)])
R(gf180mcu_as_sc_mcu7t3v3_, metal1_pin, [(0,-0.3,6.16,0.3), (0,-0.3,6.16,0.3), (4.845,1.025,5.18,2.75), (4.845,1.025,5.18,2.75), (1.975,1.57,3.26,1.955), (1.975,1.57,3.26,1.955), (0.375,1.585,1.425,1.97), (0.375,1.585,1.425,1.97), (4.18,1.585,4.58,2.415), (4.18,1.585,4.58,2.415), (0,3.62,6.16,4.22), (0,3.62,6.16,4.22)])
R(gf180mcu_as_sc_mcu7t3v3_, lvpwell, [(-0.43,-0.43,6.59,1.77), (-0.43,-0.43,6.59,1.77)])
R(gf180mcu_as_sc_mcu7t3v3_, lvpwell_10, [(0.05,-0.25,0.55,0.25), (0.05,-0.25,0.55,0.25)])
gf180mcu_as_sc_mcu7t3v3_.add(gdstk.Label('VDD', (3.08,3.92), layer=34, texttype=10))
gf180mcu_as_sc_mcu7t3v3_.add(gdstk.Label('VSS', (3.08,0), layer=34, texttype=10))
gf180mcu_as_sc_mcu7t3v3_.add(gdstk.Label('A', (0.9,1.777), layer=34, texttype=10))
gf180mcu_as_sc_mcu7t3v3_.add(gdstk.Label('B', (2.617,1.762), layer=34, texttype=10))
gf180mcu_as_sc_mcu7t3v3_.add(gdstk.Label('C', (4.38,2), layer=34, texttype=10))
gf180mcu_as_sc_mcu7t3v3_.add(gdstk.Label('Y', (5.012,1.887), layer=34, texttype=10))
gf180mcu_as_sc_mcu7t3v3_.add(gdstk.Label('VDD', (3.08,3.92), layer=34, texttype=10))
gf180mcu_as_sc_mcu7t3v3_.add(gdstk.Label('VSS', (3.08,0), layer=34, texttype=10))
gf180mcu_as_sc_mcu7t3v3_.add(gdstk.Label('A', (0.9,1.777), layer=34, texttype=10))
gf180mcu_as_sc_mcu7t3v3_.add(gdstk.Label('B', (2.617,1.762), layer=34, texttype=10))
gf180mcu_as_sc_mcu7t3v3_.add(gdstk.Label('C', (4.38,2), layer=34, texttype=10))
gf180mcu_as_sc_mcu7t3v3_.add(gdstk.Label('Y', (5.012,1.887), layer=34, texttype=10))
gf180mcu_as_sc_mcu7t3v3_.add(gdstk.Label('VNW', (0.3,3.92), layer=21, texttype=10))
gf180mcu_as_sc_mcu7t3v3_.add(gdstk.Label('VNW', (0.3,3.92), layer=21, texttype=10))
gf180mcu_as_sc_mcu7t3v3_.add(gdstk.Label('VPW', (0.3,0), layer=204, texttype=10))
gf180mcu_as_sc_mcu7t3v3_.add(gdstk.Label('VPW', (0.3,0), layer=204, texttype=10))

lib.write_gds('gf180mcu_as_sc_mcu7t3v3__nor3_2.gds')
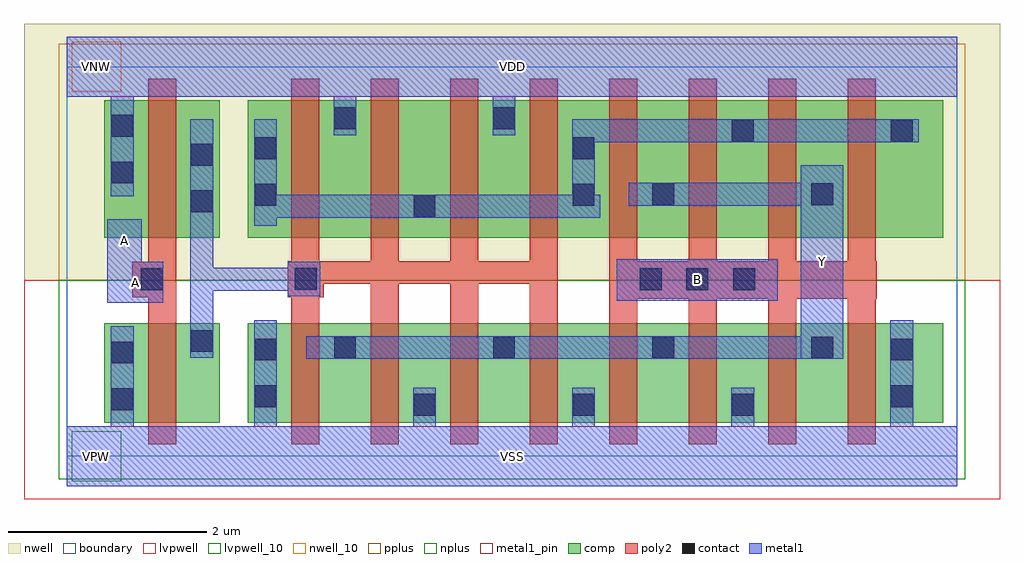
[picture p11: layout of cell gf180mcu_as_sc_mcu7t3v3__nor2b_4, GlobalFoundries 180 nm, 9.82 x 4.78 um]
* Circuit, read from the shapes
.subckt gf180mcu_as_sc_mcu7t3v3__nor2b_4 A B VDD VNW VSS Y
XM1 n1 A VSS VSUBS nfet_03v3 w=1u l=0.28u
XM2 Y n1 VSS VSUBS nfet_03v3 w=1u l=0.28u m=4
XM3 Y B VSS VSUBS nfet_03v3 w=1u l=0.28u m=4
XM4 n1 A VDD VNW pfet_03v3 w=1.38u l=0.28u
XM5 VDD n1 n2 VNW pfet_03v3 w=1.38u l=0.28u m=4
XM6 Y B n2 VNW pfet_03v3 w=1.38u l=0.28u m=4
.ends

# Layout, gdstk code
import gdstk
lib = gdstk.Library(unit=1e-6, precision=1e-09)
def R(c, l, rs):  # rectangles x0, y0, x1, y1
    for r in rs: c.add(gdstk.rectangle(r[:2], r[2:], *l))
boundary = (0, 0)
nwell = (21, 0)
nwell_10 = (21, 10)
comp = (22, 0)
poly2 = (30, 0)
pplus = (31, 0)
nplus = (32, 0)
contact = (33, 0)
metal1 = (34, 0)
metal1_pin = (34, 10)
lvpwell = (204, 0)
lvpwell_10 = (204, 10)

gf180mcu_as_sc_mcu7t3v3_ = lib.new_cell('gf180mcu_as_sc_mcu7t3v3__nor2b_4')
R(gf180mcu_as_sc_mcu7t3v3_, boundary, [(0,0,8.96,3.92), (0,0,8.96,3.92)])
R(gf180mcu_as_sc_mcu7t3v3_, nwell, [(-0.43,1.77,9.39,4.35), (-0.43,1.77,9.39,4.35)])
R(gf180mcu_as_sc_mcu7t3v3_, nwell_10, [(0.05,3.67,0.55,4.17), (0.05,3.67,0.55,4.17)])
R(gf180mcu_as_sc_mcu7t3v3_, comp, [(0.375,0.34,1.54,1.34), (0.375,0.34,1.54,1.34), (1.82,0.34,8.82,1.34), (1.82,0.34,8.82,1.34), (0.375,2.2,1.54,3.58), (0.375,2.2,1.54,3.58), (1.82,2.2,8.82,3.58), (1.82,2.2,8.82,3.58)])
R(gf180mcu_as_sc_mcu7t3v3_, poly2, [(0.82,0.12,1.1,1.6), (0.82,0.12,1.1,1.6), (2.26,0.12,2.54,1.6), (2.26,0.12,2.54,1.6), (3.06,0.12,3.34,1.735), (3.06,0.12,3.34,1.735), (3.86,0.12,4.14,1.735), (3.86,0.12,4.14,1.735), (4.66,0.12,4.94,1.735), (4.66,0.12,4.94,1.735), (5.46,0.12,5.74,1.585), (5.46,0.12,5.74,1.585), (6.26,0.12,6.54,1.585), (6.26,0.12,6.54,1.585), (7.06,0.12,7.34,1.585), (7.06,0.12,7.34,1.585), (7.86,0.12,8.14,1.585), (7.86,0.12,8.14,1.585), (5.46,1.585,8.15,1.965), (5.46,1.585,8.15,1.965), (0.66,1.6,1.1,1.96), (0.66,1.6,1.1,1.96), (2.225,1.6,2.585,1.735), (2.225,1.6,2.585,1.735), (2.225,1.735,4.94,1.965), (2.225,1.735,4.94,1.965), (0.82,1.96,1.1,3.8), (0.82,1.96,1.1,3.8), (2.26,1.965,2.54,3.8), (2.26,1.965,2.54,3.8), (3.06,1.965,3.34,3.8), (3.06,1.965,3.34,3.8), (3.86,1.965,4.14,3.8), (3.86,1.965,4.14,3.8), (4.66,1.965,4.94,3.8), (4.66,1.965,4.94,3.8), (5.46,1.965,5.74,3.8), (5.46,1.965,5.74,3.8), (6.26,1.965,6.54,3.8), (6.26,1.965,6.54,3.8), (7.06,1.965,7.34,3.8), (7.06,1.965,7.34,3.8), (7.86,1.965,8.14,3.8), (7.86,1.965,8.14,3.8)])
R(gf180mcu_as_sc_mcu7t3v3_, pplus, [(-0.08,1.77,9.04,4.15), (-0.08,1.77,9.04,4.15), (0.59,1.97,1.33,2.04), (0.59,1.97,1.33,2.04), (2.03,1.97,8.37,2.04), (2.03,1.97,8.37,2.04), (0.215,2.04,8.98,3.74), (0.215,2.04,8.98,3.74), (0.59,3.74,1.33,3.81), (0.59,3.74,1.33,3.81), (2.03,3.74,8.37,3.81), (2.03,3.74,8.37,3.81)])
R(gf180mcu_as_sc_mcu7t3v3_, nplus, [(-0.08,-0.23,9.04,1.77), (-0.08,-0.23,9.04,1.77), (-0.08,-0.23,9.04,1.77), (-0.08,-0.23,9.04,1.77)])
R(gf180mcu_as_sc_mcu7t3v3_, contact, [(3.49,0.41,3.71,0.63), (3.49,0.41,3.71,0.63), (5.09,0.41,5.31,0.63), (5.09,0.41,5.31,0.63), (6.69,0.41,6.91,0.63), (6.69,0.41,6.91,0.63), (0.45,0.465,0.67,0.685), (0.45,0.465,0.67,0.685), (1.89,0.495,2.11,0.715), (1.89,0.495,2.11,0.715), (8.29,0.495,8.51,0.715), (8.29,0.495,8.51,0.715), (0.45,0.935,0.67,1.155), (0.45,0.935,0.67,1.155), (1.89,0.965,2.11,1.185), (1.89,0.965,2.11,1.185), (8.29,0.965,8.51,1.185), (8.29,0.965,8.51,1.185), (2.69,0.985,2.91,1.205), (2.69,0.985,2.91,1.205), (4.29,0.985,4.51,1.205), (4.29,0.985,4.51,1.205), (5.89,0.985,6.11,1.205), (5.89,0.985,6.11,1.205), (7.49,0.985,7.71,1.205), (7.49,0.985,7.71,1.205), (1.25,1.05,1.47,1.27), (1.25,1.05,1.47,1.27), (0.745,1.67,0.965,1.89), (0.745,1.67,0.965,1.89), (5.765,1.67,5.985,1.89), (5.765,1.67,5.985,1.89), (6.235,1.67,6.455,1.89), (6.235,1.67,6.455,1.89), (6.705,1.67,6.925,1.89), (6.705,1.67,6.925,1.89), (2.295,1.675,2.515,1.895), (2.295,1.675,2.515,1.895), (3.49,2.405,3.71,2.625), (3.49,2.405,3.71,2.625), (1.25,2.455,1.47,2.675), (1.25,2.455,1.47,2.675), (1.89,2.52,2.11,2.74), (1.89,2.52,2.11,2.74), (5.09,2.52,5.31,2.74), (5.09,2.52,5.31,2.74), (5.89,2.525,6.11,2.745), (5.89,2.525,6.11,2.745), (7.49,2.525,7.71,2.745), (7.49,2.525,7.71,2.745), (0.45,2.745,0.67,2.965), (0.45,2.745,0.67,2.965), (1.25,2.925,1.47,3.145), (1.25,2.925,1.47,3.145), (1.89,2.99,2.11,3.21), (1.89,2.99,2.11,3.21), (5.09,2.99,5.31,3.21), (5.09,2.99,5.31,3.21), (6.69,3.165,6.91,3.385), (6.69,3.165,6.91,3.385), (8.29,3.165,8.51,3.385), (8.29,3.165,8.51,3.385), (0.45,3.215,0.67,3.435), (0.45,3.215,0.67,3.435), (2.69,3.29,2.91,3.51), (2.69,3.29,2.91,3.51), (4.29,3.29,4.51,3.51), (4.29,3.29,4.51,3.51)])
R(gf180mcu_as_sc_mcu7t3v3_, metal1, [(0,-0.3,8.96,0.3), (0,-0.3,8.96,0.3), (0.445,0.3,0.675,1.31), (0.445,0.3,0.675,1.31), (1.885,0.3,2.115,1.37), (1.885,0.3,2.115,1.37), (3.485,0.3,3.715,0.69), (3.485,0.3,3.715,0.69), (5.085,0.3,5.315,0.69), (5.085,0.3,5.315,0.69), (6.685,0.3,6.915,0.69), (6.685,0.3,6.915,0.69), (8.285,0.3,8.515,1.37), (8.285,0.3,8.515,1.37), (2.41,0.98,7.815,1.21), (2.41,0.98,7.815,1.21), (1.245,0.99,1.475,1.665), (1.245,0.99,1.475,1.665), (7.385,1.21,7.815,2.52), (7.385,1.21,7.815,2.52), (0.41,1.545,0.97,1.955), (0.41,1.545,0.97,1.955), (5.535,1.565,7.155,1.985), (5.535,1.565,7.155,1.985), (2.225,1.61,2.55,1.665), (2.225,1.61,2.55,1.665), (1.245,1.665,2.55,1.895), (1.245,1.665,2.55,1.895), (1.245,1.895,1.475,3.39), (1.245,1.895,1.475,3.39), (2.225,1.895,2.55,1.955), (2.225,1.895,2.55,1.955), (0.41,1.955,0.755,2.385), (0.41,1.955,0.755,2.385), (1.885,2.32,2.115,2.4), (1.885,2.32,2.115,2.4), (1.885,2.4,5.37,2.63), (1.885,2.4,5.37,2.63), (5.655,2.52,7.815,2.75), (5.655,2.52,7.815,2.75), (0.445,2.615,0.675,3.62), (0.445,2.615,0.675,3.62), (1.885,2.63,2.115,3.39), (1.885,2.63,2.115,3.39), (5.085,2.63,5.315,3.16), (5.085,2.63,5.315,3.16), (7.385,2.75,7.815,2.93), (7.385,2.75,7.815,2.93), (5.085,3.16,8.57,3.39), (5.085,3.16,8.57,3.39), (2.685,3.23,2.915,3.62), (2.685,3.23,2.915,3.62), (4.285,3.23,4.515,3.62), (4.285,3.23,4.515,3.62), (0,3.62,8.96,4.22), (0,3.62,8.96,4.22)])
R(gf180mcu_as_sc_mcu7t3v3_, metal1_pin, [(0,-0.3,8.96,0.3), (0,-0.3,8.96,0.3), (7.385,0.98,7.815,2.93), (7.385,0.98,7.815,2.93), (0.41,1.545,0.97,1.955), (0.41,1.545,0.97,1.955), (5.535,1.565,7.155,1.985), (5.535,1.565,7.155,1.985), (0.41,1.955,0.755,2.385), (0.41,1.955,0.755,2.385), (0,3.62,8.96,4.22), (0,3.62,8.96,4.22)])
R(gf180mcu_as_sc_mcu7t3v3_, lvpwell, [(-0.43,-0.43,9.39,1.77), (-0.43,-0.43,9.39,1.77)])
R(gf180mcu_as_sc_mcu7t3v3_, lvpwell_10, [(0.05,-0.25,0.55,0.25), (0.05,-0.25,0.55,0.25)])
gf180mcu_as_sc_mcu7t3v3_.add(gdstk.Label('VDD', (4.48,3.92), layer=34, texttype=10))
gf180mcu_as_sc_mcu7t3v3_.add(gdstk.Label('VSS', (4.48,0), layer=34, texttype=10))
gf180mcu_as_sc_mcu7t3v3_.add(gdstk.Label('Y', (7.6,1.955), layer=34, texttype=10))
gf180mcu_as_sc_mcu7t3v3_.add(gdstk.Label('A', (0.582,2.17), layer=34, texttype=10))
gf180mcu_as_sc_mcu7t3v3_.add(gdstk.Label('A', (0.69,1.75), layer=34, texttype=10))
gf180mcu_as_sc_mcu7t3v3_.add(gdstk.Label('B', (6.345,1.775), layer=34, texttype=10))
gf180mcu_as_sc_mcu7t3v3_.add(gdstk.Label('VDD', (4.48,3.92), layer=34, texttype=10))
gf180mcu_as_sc_mcu7t3v3_.add(gdstk.Label('VSS', (4.48,0), layer=34, texttype=10))
gf180mcu_as_sc_mcu7t3v3_.add(gdstk.Label('Y', (7.6,1.955), layer=34, texttype=10))
gf180mcu_as_sc_mcu7t3v3_.add(gdstk.Label('A', (0.582,2.17), layer=34, texttype=10))
gf180mcu_as_sc_mcu7t3v3_.add(gdstk.Label('A', (0.69,1.75), layer=34, texttype=10))
gf180mcu_as_sc_mcu7t3v3_.add(gdstk.Label('B', (6.345,1.775), layer=34, texttype=10))
gf180mcu_as_sc_mcu7t3v3_.add(gdstk.Label('VNW', (0.3,3.92), layer=21, texttype=10))
gf180mcu_as_sc_mcu7t3v3_.add(gdstk.Label('VNW', (0.3,3.92), layer=21, texttype=10))
gf180mcu_as_sc_mcu7t3v3_.add(gdstk.Label('VPW', (0.3,0), layer=204, texttype=10))
gf180mcu_as_sc_mcu7t3v3_.add(gdstk.Label('VPW', (0.3,0), layer=204, texttype=10))

lib.write_gds('gf180mcu_as_sc_mcu7t3v3__nor2b_4.gds')
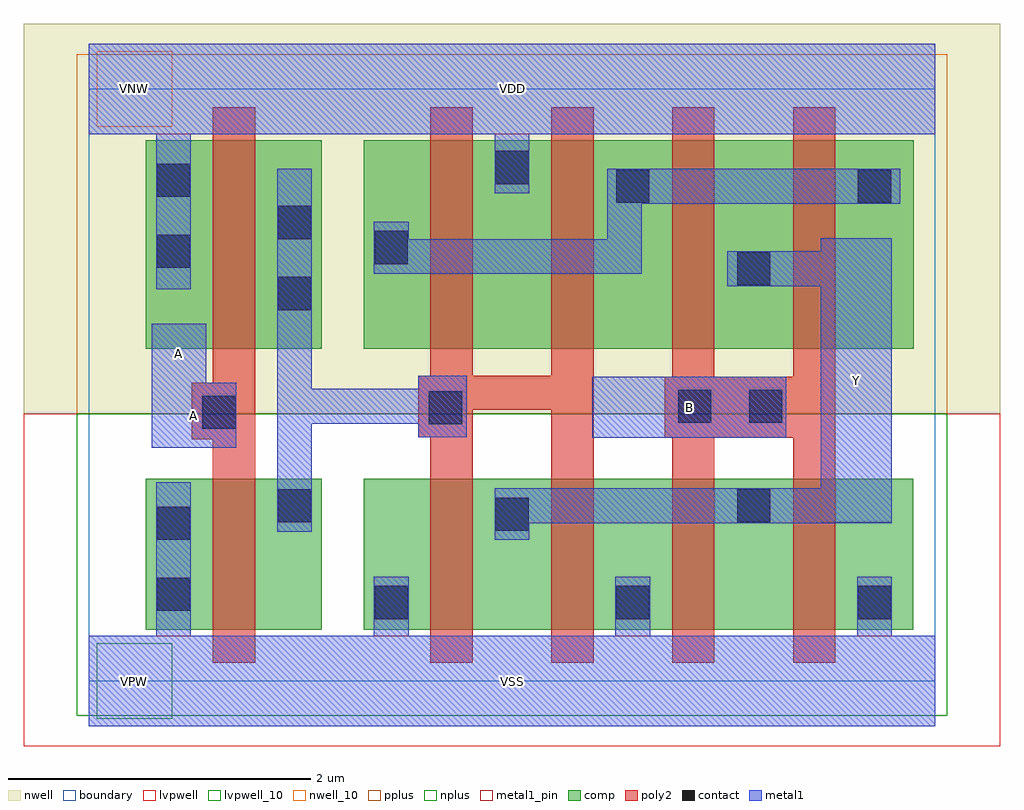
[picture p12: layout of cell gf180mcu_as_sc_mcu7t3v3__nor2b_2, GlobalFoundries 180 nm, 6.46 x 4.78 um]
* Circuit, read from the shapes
.subckt gf180mcu_as_sc_mcu7t3v3__nor2b_2 A B VDD VNW VSS Y
XM1 n1 A VSS VSUBS nfet_03v3 w=1u l=0.28u
XM2 Y n1 VSS VSUBS nfet_03v3 w=1u l=0.28u m=2
XM3 Y B VSS VSUBS nfet_03v3 w=1u l=0.28u m=2
XM4 n1 A VDD VNW pfet_03v3 w=1.38u l=0.28u
XM5 VDD n1 n2 VNW pfet_03v3 w=1.38u l=0.28u m=2
XM6 Y B n2 VNW pfet_03v3 w=1.38u l=0.28u m=2
.ends

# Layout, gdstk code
import gdstk
lib = gdstk.Library(unit=1e-6, precision=1e-09)
def R(c, l, rs):  # rectangles x0, y0, x1, y1
    for r in rs: c.add(gdstk.rectangle(r[:2], r[2:], *l))
boundary = (0, 0)
nwell = (21, 0)
nwell_10 = (21, 10)
comp = (22, 0)
poly2 = (30, 0)
pplus = (31, 0)
nplus = (32, 0)
contact = (33, 0)
metal1 = (34, 0)
metal1_pin = (34, 10)
lvpwell = (204, 0)
lvpwell_10 = (204, 10)

gf180mcu_as_sc_mcu7t3v3_ = lib.new_cell('gf180mcu_as_sc_mcu7t3v3__nor2b_2')
R(gf180mcu_as_sc_mcu7t3v3_, boundary, [(0,0,5.6,3.92), (0,0,5.6,3.92)])
R(gf180mcu_as_sc_mcu7t3v3_, nwell, [(-0.43,1.77,6.03,4.35), (-0.43,1.77,6.03,4.35)])
R(gf180mcu_as_sc_mcu7t3v3_, nwell_10, [(0.05,3.67,0.55,4.17), (0.05,3.67,0.55,4.17)])
R(gf180mcu_as_sc_mcu7t3v3_, comp, [(0.375,0.34,1.54,1.34), (0.375,0.34,1.54,1.34), (1.82,0.34,5.455,1.34), (1.82,0.34,5.455,1.34), (0.375,2.2,1.54,3.58), (0.375,2.2,1.54,3.58), (1.82,2.2,5.46,3.58), (1.82,2.2,5.46,3.58)])
R(gf180mcu_as_sc_mcu7t3v3_, poly2, [(0.82,0.12,1.1,1.6), (0.82,0.12,1.1,1.6), (2.26,0.12,2.54,1.615), (2.26,0.12,2.54,1.615), (3.06,0.12,3.34,1.795), (3.06,0.12,3.34,1.795), (3.86,0.12,4.14,1.61), (3.86,0.12,4.14,1.61), (4.66,0.12,4.94,1.61), (4.66,0.12,4.94,1.61), (0.68,1.6,1.1,1.975), (0.68,1.6,1.1,1.975), (3.81,1.61,4.94,2.015), (3.81,1.61,4.94,2.015), (2.18,1.615,2.54,1.795), (2.18,1.615,2.54,1.795), (2.18,1.795,3.34,2.02), (2.18,1.795,3.34,2.02), (0.82,1.975,1.1,3.8), (0.82,1.975,1.1,3.8), (3.86,2.015,4.14,3.8), (3.86,2.015,4.14,3.8), (4.66,2.015,4.94,3.8), (4.66,2.015,4.94,3.8), (2.26,2.02,2.54,3.8), (2.26,2.02,2.54,3.8), (3.06,2.02,3.34,3.8), (3.06,2.02,3.34,3.8)])
R(gf180mcu_as_sc_mcu7t3v3_, pplus, [(-0.08,1.77,5.68,4.15), (-0.08,1.77,5.68,4.15), (0.59,1.97,1.33,2.04), (0.59,1.97,1.33,2.04), (2.03,1.97,5.17,2.04), (2.03,1.97,5.17,2.04), (0.215,2.04,5.62,3.74), (0.215,2.04,5.62,3.74), (0.59,3.74,1.33,3.81), (0.59,3.74,1.33,3.81), (2.03,3.74,5.17,3.81), (2.03,3.74,5.17,3.81)])
R(gf180mcu_as_sc_mcu7t3v3_, nplus, [(-0.08,-0.23,5.68,1.77), (-0.08,-0.23,5.68,1.77), (-0.08,-0.23,5.68,1.77), (-0.08,-0.23,5.68,1.77)])
R(gf180mcu_as_sc_mcu7t3v3_, contact, [(1.89,0.41,2.11,0.63), (1.89,0.41,2.11,0.63), (3.49,0.41,3.71,0.63), (3.49,0.41,3.71,0.63), (5.09,0.41,5.31,0.63), (5.09,0.41,5.31,0.63), (0.45,0.465,0.67,0.685), (0.45,0.465,0.67,0.685), (0.45,0.935,0.67,1.155), (0.45,0.935,0.67,1.155), (2.69,0.995,2.91,1.215), (2.69,0.995,2.91,1.215), (1.25,1.05,1.47,1.27), (1.25,1.05,1.47,1.27), (4.29,1.05,4.51,1.27), (4.29,1.05,4.51,1.27), (0.75,1.67,0.97,1.89), (0.75,1.67,0.97,1.89), (2.25,1.7,2.47,1.92), (2.25,1.7,2.47,1.92), (3.9,1.71,4.12,1.93), (3.9,1.71,4.12,1.93), (4.37,1.71,4.59,1.93), (4.37,1.71,4.59,1.93), (1.25,2.455,1.47,2.675), (1.25,2.455,1.47,2.675), (4.29,2.62,4.51,2.84), (4.29,2.62,4.51,2.84), (0.45,2.735,0.67,2.955), (0.45,2.735,0.67,2.955), (1.89,2.76,2.11,2.98), (1.89,2.76,2.11,2.98), (1.25,2.925,1.47,3.145), (1.25,2.925,1.47,3.145), (3.49,3.165,3.71,3.385), (3.49,3.165,3.71,3.385), (5.09,3.165,5.31,3.385), (5.09,3.165,5.31,3.385), (0.45,3.205,0.67,3.425), (0.45,3.205,0.67,3.425), (2.69,3.29,2.91,3.51), (2.69,3.29,2.91,3.51)])
R(gf180mcu_as_sc_mcu7t3v3_, metal1, [(0,-0.3,5.6,0.3), (0,-0.3,5.6,0.3), (0.445,0.3,0.675,1.315), (0.445,0.3,0.675,1.315), (1.885,0.3,2.115,0.69), (1.885,0.3,2.115,0.69), (3.485,0.3,3.715,0.69), (3.485,0.3,3.715,0.69), (5.085,0.3,5.315,0.69), (5.085,0.3,5.315,0.69), (2.685,0.935,2.915,1.045), (2.685,0.935,2.915,1.045), (1.245,0.99,1.475,1.705), (1.245,0.99,1.475,1.705), (2.685,1.045,5.315,1.275), (2.685,1.045,5.315,1.275), (4.845,1.275,5.315,2.615), (4.845,1.275,5.315,2.615), (0.415,1.545,0.975,1.975), (0.415,1.545,0.975,1.975), (3.33,1.61,4.615,2.015), (3.33,1.61,4.615,2.015), (2.18,1.615,2.5,1.705), (2.18,1.615,2.5,1.705), (1.245,1.705,2.5,1.935), (1.245,1.705,2.5,1.935), (1.245,1.935,1.475,3.39), (1.245,1.935,1.475,3.39), (2.18,1.935,2.5,2.02), (2.18,1.935,2.5,2.02), (0.415,1.975,0.775,2.365), (0.415,1.975,0.775,2.365), (0.445,2.595,0.675,3.62), (0.445,2.595,0.675,3.62), (4.225,2.615,5.315,2.845), (4.225,2.615,5.315,2.845), (1.885,2.695,3.66,2.925), (1.885,2.695,3.66,2.925), (4.845,2.845,5.315,2.93), (4.845,2.845,5.315,2.93), (1.885,2.925,2.115,3.04), (1.885,2.925,2.115,3.04), (3.43,2.925,3.66,3.16), (3.43,2.925,3.66,3.16), (3.43,3.16,5.37,3.39), (3.43,3.16,5.37,3.39), (2.685,3.23,2.915,3.62), (2.685,3.23,2.915,3.62), (0,3.62,5.6,4.22), (0,3.62,5.6,4.22)])
R(gf180mcu_as_sc_mcu7t3v3_, metal1_pin, [(0,-0.3,5.6,0.3), (0,-0.3,5.6,0.3), (4.845,1.05,5.315,2.93), (4.845,1.05,5.315,2.93), (0.415,1.545,0.975,1.975), (0.415,1.545,0.975,1.975), (3.33,1.61,4.615,2.015), (3.33,1.61,4.615,2.015), (0.415,1.975,0.775,2.365), (0.415,1.975,0.775,2.365), (0,3.62,5.6,4.22), (0,3.62,5.6,4.22)])
R(gf180mcu_as_sc_mcu7t3v3_, lvpwell, [(-0.43,-0.43,6.03,1.77), (-0.43,-0.43,6.03,1.77)])
R(gf180mcu_as_sc_mcu7t3v3_, lvpwell_10, [(0.05,-0.25,0.55,0.25), (0.05,-0.25,0.55,0.25)])
gf180mcu_as_sc_mcu7t3v3_.add(gdstk.Label('VDD', (2.8,3.92), layer=34, texttype=10))
gf180mcu_as_sc_mcu7t3v3_.add(gdstk.Label('VSS', (2.8,0), layer=34, texttype=10))
gf180mcu_as_sc_mcu7t3v3_.add(gdstk.Label('Y', (5.08,1.99), layer=34, texttype=10))
gf180mcu_as_sc_mcu7t3v3_.add(gdstk.Label('B', (3.972,1.812), layer=34, texttype=10))
gf180mcu_as_sc_mcu7t3v3_.add(gdstk.Label('A', (0.595,2.17), layer=34, texttype=10))
gf180mcu_as_sc_mcu7t3v3_.add(gdstk.Label('A', (0.695,1.76), layer=34, texttype=10))
gf180mcu_as_sc_mcu7t3v3_.add(gdstk.Label('VDD', (2.8,3.92), layer=34, texttype=10))
gf180mcu_as_sc_mcu7t3v3_.add(gdstk.Label('VSS', (2.8,0), layer=34, texttype=10))
gf180mcu_as_sc_mcu7t3v3_.add(gdstk.Label('Y', (5.08,1.99), layer=34, texttype=10))
gf180mcu_as_sc_mcu7t3v3_.add(gdstk.Label('B', (3.972,1.812), layer=34, texttype=10))
gf180mcu_as_sc_mcu7t3v3_.add(gdstk.Label('A', (0.595,2.17), layer=34, texttype=10))
gf180mcu_as_sc_mcu7t3v3_.add(gdstk.Label('A', (0.695,1.76), layer=34, texttype=10))
gf180mcu_as_sc_mcu7t3v3_.add(gdstk.Label('VNW', (0.3,3.92), layer=21, texttype=10))
gf180mcu_as_sc_mcu7t3v3_.add(gdstk.Label('VNW', (0.3,3.92), layer=21, texttype=10))
gf180mcu_as_sc_mcu7t3v3_.add(gdstk.Label('VPW', (0.3,0), layer=204, texttype=10))
gf180mcu_as_sc_mcu7t3v3_.add(gdstk.Label('VPW', (0.3,0), layer=204, texttype=10))

lib.write_gds('gf180mcu_as_sc_mcu7t3v3__nor2b_2.gds')
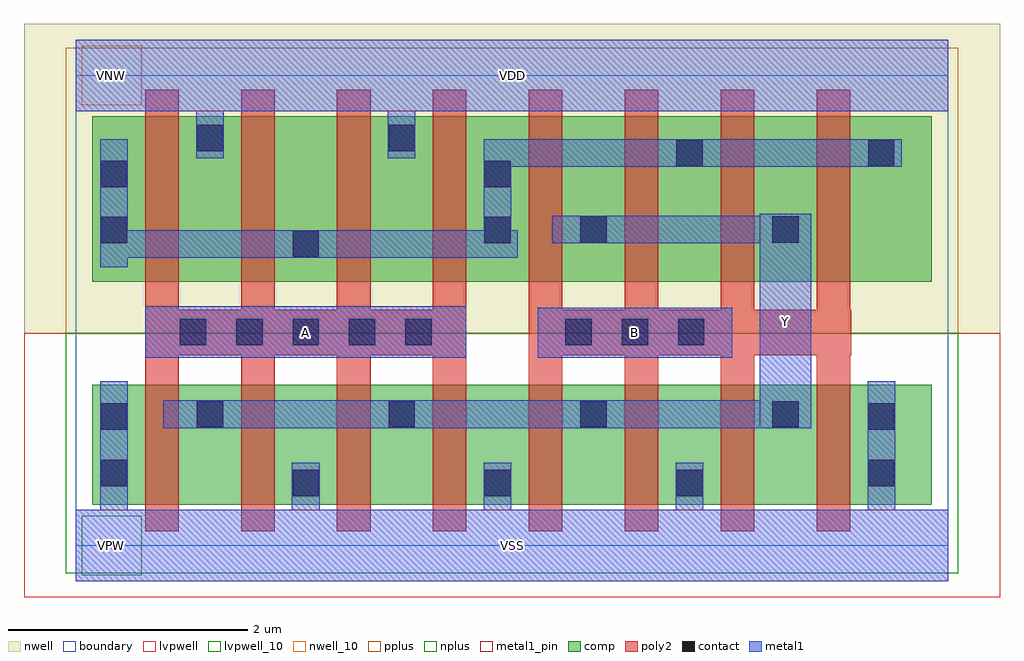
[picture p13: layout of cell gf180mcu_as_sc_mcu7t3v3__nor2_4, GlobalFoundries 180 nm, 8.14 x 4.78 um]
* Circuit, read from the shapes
.subckt gf180mcu_as_sc_mcu7t3v3__nor2_4 A B VDD VNW VSS Y
XM1 Y A VSS VSUBS nfet_03v3 w=1u l=0.28u m=4
XM2 Y B VSS VSUBS nfet_03v3 w=1u l=0.28u m=4
XM3 VDD A n1 VNW pfet_03v3 w=1.38u l=0.28u m=4
XM4 Y B n1 VNW pfet_03v3 w=1.38u l=0.28u m=4
.ends

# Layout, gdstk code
import gdstk
lib = gdstk.Library(unit=1e-6, precision=1e-09)
def R(c, l, rs):  # rectangles x0, y0, x1, y1
    for r in rs: c.add(gdstk.rectangle(r[:2], r[2:], *l))
boundary = (0, 0)
nwell = (21, 0)
nwell_10 = (21, 10)
comp = (22, 0)
poly2 = (30, 0)
pplus = (31, 0)
nplus = (32, 0)
contact = (33, 0)
metal1 = (34, 0)
metal1_pin = (34, 10)
lvpwell = (204, 0)
lvpwell_10 = (204, 10)

gf180mcu_as_sc_mcu7t3v3_ = lib.new_cell('gf180mcu_as_sc_mcu7t3v3__nor2_4')
R(gf180mcu_as_sc_mcu7t3v3_, boundary, [(0,0,7.28,3.92), (0,0,7.28,3.92)])
R(gf180mcu_as_sc_mcu7t3v3_, nwell, [(-0.43,1.77,7.71,4.35), (-0.43,1.77,7.71,4.35)])
R(gf180mcu_as_sc_mcu7t3v3_, nwell_10, [(0.05,3.67,0.55,4.17), (0.05,3.67,0.55,4.17)])
R(gf180mcu_as_sc_mcu7t3v3_, comp, [(0.14,0.34,7.14,1.34), (0.14,0.34,7.14,1.34), (0.14,2.2,7.14,3.58), (0.14,2.2,7.14,3.58)])
R(gf180mcu_as_sc_mcu7t3v3_, poly2, [(0.58,0.12,0.86,1.585), (0.58,0.12,0.86,1.585), (1.38,0.12,1.66,1.585), (1.38,0.12,1.66,1.585), (2.18,0.12,2.46,1.585), (2.18,0.12,2.46,1.585), (2.98,0.12,3.26,1.585), (2.98,0.12,3.26,1.585), (3.78,0.12,4.06,1.585), (3.78,0.12,4.06,1.585), (4.58,0.12,4.86,1.585), (4.58,0.12,4.86,1.585), (5.38,0.12,5.66,1.585), (5.38,0.12,5.66,1.585), (6.18,0.12,6.46,1.585), (6.18,0.12,6.46,1.585), (0.58,1.585,3.26,1.965), (0.58,1.585,3.26,1.965), (3.78,1.585,6.47,1.965), (3.78,1.585,6.47,1.965), (0.58,1.965,0.86,3.8), (0.58,1.965,0.86,3.8), (1.38,1.965,1.66,3.8), (1.38,1.965,1.66,3.8), (2.18,1.965,2.46,3.8), (2.18,1.965,2.46,3.8), (2.98,1.965,3.26,3.8), (2.98,1.965,3.26,3.8), (3.78,1.965,4.06,3.8), (3.78,1.965,4.06,3.8), (4.58,1.965,4.86,3.8), (4.58,1.965,4.86,3.8), (5.38,1.965,5.66,3.8), (5.38,1.965,5.66,3.8), (6.18,1.965,6.46,3.8), (6.18,1.965,6.46,3.8)])
R(gf180mcu_as_sc_mcu7t3v3_, pplus, [(-0.08,1.77,7.36,4.15), (-0.08,1.77,7.36,4.15), (0.35,1.97,6.69,2.04), (0.35,1.97,6.69,2.04), (-0.02,2.04,7.3,3.74), (-0.02,2.04,7.3,3.74), (0.35,3.74,6.69,3.81), (0.35,3.74,6.69,3.81)])
R(gf180mcu_as_sc_mcu7t3v3_, nplus, [(-0.08,-0.23,7.36,1.77), (-0.08,-0.23,7.36,1.77), (-0.08,-0.23,7.36,1.77), (-0.08,-0.23,7.36,1.77)])
R(gf180mcu_as_sc_mcu7t3v3_, contact, [(1.81,0.41,2.03,0.63), (1.81,0.41,2.03,0.63), (3.41,0.41,3.63,0.63), (3.41,0.41,3.63,0.63), (5.01,0.41,5.23,0.63), (5.01,0.41,5.23,0.63), (0.21,0.495,0.43,0.715), (0.21,0.495,0.43,0.715), (6.61,0.495,6.83,0.715), (6.61,0.495,6.83,0.715), (0.21,0.965,0.43,1.185), (0.21,0.965,0.43,1.185), (6.61,0.965,6.83,1.185), (6.61,0.965,6.83,1.185), (1.01,0.985,1.23,1.205), (1.01,0.985,1.23,1.205), (2.61,0.985,2.83,1.205), (2.61,0.985,2.83,1.205), (4.21,0.985,4.43,1.205), (4.21,0.985,4.43,1.205), (5.81,0.985,6.03,1.205), (5.81,0.985,6.03,1.205), (0.87,1.67,1.09,1.89), (0.87,1.67,1.09,1.89), (1.34,1.67,1.56,1.89), (1.34,1.67,1.56,1.89), (1.81,1.67,2.03,1.89), (1.81,1.67,2.03,1.89), (2.28,1.67,2.5,1.89), (2.28,1.67,2.5,1.89), (2.75,1.67,2.97,1.89), (2.75,1.67,2.97,1.89), (4.085,1.67,4.305,1.89), (4.085,1.67,4.305,1.89), (4.555,1.67,4.775,1.89), (4.555,1.67,4.775,1.89), (5.025,1.67,5.245,1.89), (5.025,1.67,5.245,1.89), (1.81,2.405,2.03,2.625), (1.81,2.405,2.03,2.625), (0.21,2.52,0.43,2.74), (0.21,2.52,0.43,2.74), (3.41,2.52,3.63,2.74), (3.41,2.52,3.63,2.74), (4.21,2.525,4.43,2.745), (4.21,2.525,4.43,2.745), (5.81,2.525,6.03,2.745), (5.81,2.525,6.03,2.745), (0.21,2.99,0.43,3.21), (0.21,2.99,0.43,3.21), (3.41,2.99,3.63,3.21), (3.41,2.99,3.63,3.21), (5.01,3.165,5.23,3.385), (5.01,3.165,5.23,3.385), (6.61,3.165,6.83,3.385), (6.61,3.165,6.83,3.385), (1.01,3.29,1.23,3.51), (1.01,3.29,1.23,3.51), (2.61,3.29,2.83,3.51), (2.61,3.29,2.83,3.51)])
R(gf180mcu_as_sc_mcu7t3v3_, metal1, [(0,-0.3,7.28,0.3), (0,-0.3,7.28,0.3), (0.205,0.3,0.435,1.37), (0.205,0.3,0.435,1.37), (1.805,0.3,2.035,0.69), (1.805,0.3,2.035,0.69), (3.405,0.3,3.635,0.69), (3.405,0.3,3.635,0.69), (5.005,0.3,5.235,0.69), (5.005,0.3,5.235,0.69), (6.605,0.3,6.835,1.37), (6.605,0.3,6.835,1.37), (0.73,0.98,6.135,1.21), (0.73,0.98,6.135,1.21), (5.705,1.21,6.135,2.52), (5.705,1.21,6.135,2.52), (0.58,1.565,3.26,1.995), (0.58,1.565,3.26,1.995), (3.855,1.565,5.475,1.985), (3.855,1.565,5.475,1.985), (0.205,2.32,0.435,2.4), (0.205,2.32,0.435,2.4), (0.205,2.4,3.69,2.63), (0.205,2.4,3.69,2.63), (3.975,2.52,6.135,2.75), (3.975,2.52,6.135,2.75), (0.205,2.63,0.435,3.39), (0.205,2.63,0.435,3.39), (3.405,2.63,3.635,3.16), (3.405,2.63,3.635,3.16), (5.705,2.75,6.135,2.765), (5.705,2.75,6.135,2.765), (3.405,3.16,6.89,3.39), (3.405,3.16,6.89,3.39), (1.005,3.23,1.235,3.62), (1.005,3.23,1.235,3.62), (2.605,3.23,2.835,3.62), (2.605,3.23,2.835,3.62), (0,3.62,7.28,4.22), (0,3.62,7.28,4.22)])
R(gf180mcu_as_sc_mcu7t3v3_, metal1_pin, [(0,-0.3,7.28,0.3), (0,-0.3,7.28,0.3), (5.705,0.98,6.135,2.765), (5.705,0.98,6.135,2.765), (0.58,1.565,3.26,1.995), (0.58,1.565,3.26,1.995), (3.855,1.565,5.475,1.985), (3.855,1.565,5.475,1.985), (0,3.62,7.28,4.22), (0,3.62,7.28,4.22)])
R(gf180mcu_as_sc_mcu7t3v3_, lvpwell, [(-0.43,-0.43,7.71,1.77), (-0.43,-0.43,7.71,1.77)])
R(gf180mcu_as_sc_mcu7t3v3_, lvpwell_10, [(0.05,-0.25,0.55,0.25), (0.05,-0.25,0.55,0.25)])
gf180mcu_as_sc_mcu7t3v3_.add(gdstk.Label('VDD', (3.64,3.92), layer=34, texttype=10))
gf180mcu_as_sc_mcu7t3v3_.add(gdstk.Label('VSS', (3.64,0), layer=34, texttype=10))
gf180mcu_as_sc_mcu7t3v3_.add(gdstk.Label('Y', (5.92,1.872), layer=34, texttype=10))
gf180mcu_as_sc_mcu7t3v3_.add(gdstk.Label('A', (1.92,1.78), layer=34, texttype=10))
gf180mcu_as_sc_mcu7t3v3_.add(gdstk.Label('B', (4.665,1.775), layer=34, texttype=10))
gf180mcu_as_sc_mcu7t3v3_.add(gdstk.Label('VDD', (3.64,3.92), layer=34, texttype=10))
gf180mcu_as_sc_mcu7t3v3_.add(gdstk.Label('VSS', (3.64,0), layer=34, texttype=10))
gf180mcu_as_sc_mcu7t3v3_.add(gdstk.Label('Y', (5.92,1.872), layer=34, texttype=10))
gf180mcu_as_sc_mcu7t3v3_.add(gdstk.Label('A', (1.92,1.78), layer=34, texttype=10))
gf180mcu_as_sc_mcu7t3v3_.add(gdstk.Label('B', (4.665,1.775), layer=34, texttype=10))
gf180mcu_as_sc_mcu7t3v3_.add(gdstk.Label('VNW', (0.3,3.92), layer=21, texttype=10))
gf180mcu_as_sc_mcu7t3v3_.add(gdstk.Label('VNW', (0.3,3.92), layer=21, texttype=10))
gf180mcu_as_sc_mcu7t3v3_.add(gdstk.Label('VPW', (0.3,0), layer=204, texttype=10))
gf180mcu_as_sc_mcu7t3v3_.add(gdstk.Label('VPW', (0.3,0), layer=204, texttype=10))

lib.write_gds('gf180mcu_as_sc_mcu7t3v3__nor2_4.gds')
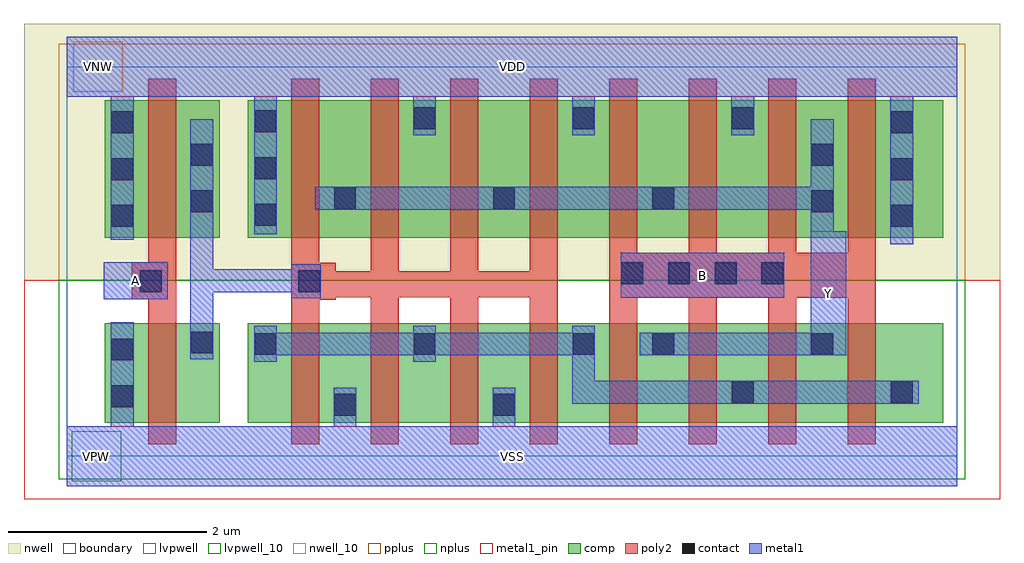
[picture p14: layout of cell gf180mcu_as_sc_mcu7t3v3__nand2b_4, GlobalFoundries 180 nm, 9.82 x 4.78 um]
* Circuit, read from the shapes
.subckt gf180mcu_as_sc_mcu7t3v3__nand2b_4 A B VDD VNW VSS Y
XM1 n1 A VSS VSUBS nfet_03v3 w=1u l=0.28u
XM2 VSS n1 n2 VSUBS nfet_03v3 w=1u l=0.28u m=4
XM3 Y B n2 VSUBS nfet_03v3 w=1u l=0.28u m=4
XM4 n1 A VDD VNW pfet_03v3 w=1.38u l=0.28u
XM5 Y n1 VDD VNW pfet_03v3 w=1.38u l=0.28u m=4
XM6 Y B VDD VNW pfet_03v3 w=1.38u l=0.28u m=4
.ends

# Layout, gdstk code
import gdstk
lib = gdstk.Library(unit=1e-6, precision=1e-09)
def R(c, l, rs):  # rectangles x0, y0, x1, y1
    for r in rs: c.add(gdstk.rectangle(r[:2], r[2:], *l))
boundary = (0, 0)
nwell = (21, 0)
nwell_10 = (21, 10)
comp = (22, 0)
poly2 = (30, 0)
pplus = (31, 0)
nplus = (32, 0)
contact = (33, 0)
metal1 = (34, 0)
metal1_pin = (34, 10)
lvpwell = (204, 0)
lvpwell_10 = (204, 10)

gf180mcu_as_sc_mcu7t3v3_ = lib.new_cell('gf180mcu_as_sc_mcu7t3v3__nand2b_4')
R(gf180mcu_as_sc_mcu7t3v3_, boundary, [(0,0,8.96,3.92), (0,0,8.96,3.92)])
R(gf180mcu_as_sc_mcu7t3v3_, nwell, [(-0.43,1.77,9.39,4.35), (-0.43,1.77,9.39,4.35)])
R(gf180mcu_as_sc_mcu7t3v3_, nwell_10, [(0.065,3.67,0.565,4.17), (0.065,3.67,0.565,4.17)])
R(gf180mcu_as_sc_mcu7t3v3_, comp, [(0.38,0.34,1.54,1.34), (0.38,0.34,1.54,1.34), (1.82,0.34,8.82,1.34), (1.82,0.34,8.82,1.34), (0.38,2.2,1.54,3.58), (0.38,2.2,1.54,3.58), (1.82,2.2,8.82,3.58), (1.82,2.2,8.82,3.58)])
R(gf180mcu_as_sc_mcu7t3v3_, poly2, [(0.82,0.12,1.1,1.58), (0.82,0.12,1.1,1.58), (2.26,0.12,2.54,1.575), (2.26,0.12,2.54,1.575), (3.06,0.12,3.34,1.6), (3.06,0.12,3.34,1.6), (3.86,0.12,4.14,1.6), (3.86,0.12,4.14,1.6), (4.66,0.12,4.94,1.6), (4.66,0.12,4.94,1.6), (5.46,0.12,5.74,1.595), (5.46,0.12,5.74,1.595), (6.26,0.12,6.54,1.595), (6.26,0.12,6.54,1.595), (7.06,0.12,7.34,1.595), (7.06,0.12,7.34,1.595), (7.86,0.12,8.14,1.595), (7.86,0.12,8.14,1.595), (2.26,1.575,2.705,1.6), (2.26,1.575,2.705,1.6), (0.655,1.58,1.1,1.95), (0.655,1.58,1.1,1.95), (5.46,1.595,8.14,2.05), (5.46,1.595,8.14,2.05), (2.26,1.6,4.94,1.86), (2.26,1.6,4.94,1.86), (2.26,1.86,2.705,1.945), (2.26,1.86,2.705,1.945), (3.06,1.86,3.34,3.8), (3.06,1.86,3.34,3.8), (3.86,1.86,4.14,3.8), (3.86,1.86,4.14,3.8), (4.66,1.86,4.94,3.8), (4.66,1.86,4.94,3.8), (2.26,1.945,2.54,3.8), (2.26,1.945,2.54,3.8), (0.82,1.95,1.1,3.8), (0.82,1.95,1.1,3.8), (5.46,2.05,5.74,3.8), (5.46,2.05,5.74,3.8), (6.26,2.05,6.54,3.8), (6.26,2.05,6.54,3.8), (7.06,2.05,7.34,3.8), (7.06,2.05,7.34,3.8), (7.86,2.05,8.14,3.8), (7.86,2.05,8.14,3.8)])
R(gf180mcu_as_sc_mcu7t3v3_, pplus, [(-0.08,1.77,9.04,4.15), (-0.08,1.77,9.04,4.15), (0.59,1.97,1.33,2.04), (0.59,1.97,1.33,2.04), (2.03,1.97,8.37,2.04), (2.03,1.97,8.37,2.04), (0.22,2.04,8.98,3.74), (0.22,2.04,8.98,3.74), (0.59,3.74,1.33,3.81), (0.59,3.74,1.33,3.81), (2.03,3.74,8.37,3.81), (2.03,3.74,8.37,3.81)])
R(gf180mcu_as_sc_mcu7t3v3_, nplus, [(-0.08,-0.23,9.04,1.77), (-0.08,-0.23,9.04,1.77), (-0.08,-0.23,9.04,1.77), (-0.08,-0.23,9.04,1.77)])
R(gf180mcu_as_sc_mcu7t3v3_, contact, [(2.69,0.41,2.91,0.63), (2.69,0.41,2.91,0.63), (4.29,0.41,4.51,0.63), (4.29,0.41,4.51,0.63), (0.45,0.495,0.67,0.715), (0.45,0.495,0.67,0.715), (6.69,0.535,6.91,0.755), (6.69,0.535,6.91,0.755), (8.29,0.535,8.51,0.755), (8.29,0.535,8.51,0.755), (0.45,0.965,0.67,1.185), (0.45,0.965,0.67,1.185), (1.89,1.02,2.11,1.24), (1.89,1.02,2.11,1.24), (3.49,1.02,3.71,1.24), (3.49,1.02,3.71,1.24), (5.09,1.02,5.31,1.24), (5.09,1.02,5.31,1.24), (5.89,1.02,6.11,1.24), (5.89,1.02,6.11,1.24), (7.49,1.02,7.71,1.24), (7.49,1.02,7.71,1.24), (1.25,1.035,1.47,1.255), (1.25,1.035,1.47,1.255), (0.735,1.65,0.955,1.87), (0.735,1.65,0.955,1.87), (2.33,1.65,2.55,1.87), (2.33,1.65,2.55,1.87), (5.58,1.73,5.8,1.95), (5.58,1.73,5.8,1.95), (6.05,1.73,6.27,1.95), (6.05,1.73,6.27,1.95), (6.52,1.73,6.74,1.95), (6.52,1.73,6.74,1.95), (6.99,1.73,7.21,1.95), (6.99,1.73,7.21,1.95), (0.45,2.31,0.67,2.53), (0.45,2.31,0.67,2.53), (8.29,2.31,8.51,2.53), (8.29,2.31,8.51,2.53), (1.89,2.32,2.11,2.54), (1.89,2.32,2.11,2.54), (1.25,2.455,1.47,2.675), (1.25,2.455,1.47,2.675), (7.49,2.455,7.71,2.675), (7.49,2.455,7.71,2.675), (2.69,2.485,2.91,2.705), (2.69,2.485,2.91,2.705), (4.29,2.485,4.51,2.705), (4.29,2.485,4.51,2.705), (5.89,2.485,6.11,2.705), (5.89,2.485,6.11,2.705), (0.45,2.78,0.67,3), (0.45,2.78,0.67,3), (8.29,2.78,8.51,3), (8.29,2.78,8.51,3), (1.89,2.79,2.11,3.01), (1.89,2.79,2.11,3.01), (1.25,2.925,1.47,3.145), (1.25,2.925,1.47,3.145), (7.49,2.925,7.71,3.145), (7.49,2.925,7.71,3.145), (0.45,3.25,0.67,3.47), (0.45,3.25,0.67,3.47), (8.29,3.25,8.51,3.47), (8.29,3.25,8.51,3.47), (1.89,3.26,2.11,3.48), (1.89,3.26,2.11,3.48), (3.49,3.29,3.71,3.51), (3.49,3.29,3.71,3.51), (5.09,3.29,5.31,3.51), (5.09,3.29,5.31,3.51), (6.69,3.29,6.91,3.51), (6.69,3.29,6.91,3.51)])
R(gf180mcu_as_sc_mcu7t3v3_, metal1, [(0,-0.3,8.96,0.3), (0,-0.3,8.96,0.3), (0.445,0.3,0.675,1.35), (0.445,0.3,0.675,1.35), (2.685,0.3,2.915,0.69), (2.685,0.3,2.915,0.69), (4.285,0.3,4.515,0.69), (4.285,0.3,4.515,0.69), (5.085,0.53,8.57,0.76), (5.085,0.53,8.57,0.76), (5.085,0.76,5.315,1.015), (5.085,0.76,5.315,1.015), (1.885,0.95,2.115,1.015), (1.885,0.95,2.115,1.015), (3.485,0.95,3.715,1.015), (3.485,0.95,3.715,1.015), (1.245,0.975,1.475,1.65), (1.245,0.975,1.475,1.65), (1.885,1.015,5.315,1.245), (1.885,1.015,5.315,1.245), (5.765,1.015,7.845,1.245), (5.765,1.015,7.845,1.245), (1.885,1.245,2.115,1.315), (1.885,1.245,2.115,1.315), (3.485,1.245,3.715,1.315), (3.485,1.245,3.715,1.315), (5.085,1.245,5.315,1.315), (5.085,1.245,5.315,1.315), (7.485,1.245,7.845,2.265), (7.485,1.245,7.845,2.265), (0.37,1.58,1.015,1.95), (0.37,1.58,1.015,1.95), (2.26,1.59,2.555,1.65), (2.26,1.59,2.555,1.65), (5.575,1.595,7.22,2.05), (5.575,1.595,7.22,2.05), (1.245,1.65,2.555,1.88), (1.245,1.65,2.555,1.88), (1.245,1.88,1.475,3.39), (1.245,1.88,1.475,3.39), (2.26,1.88,2.555,1.93), (2.26,1.88,2.555,1.93), (8.285,2.135,8.515,3.62), (8.285,2.135,8.515,3.62), (0.445,2.18,0.675,3.62), (0.445,2.18,0.675,3.62), (1.885,2.235,2.115,3.62), (1.885,2.235,2.115,3.62), (7.485,2.265,7.715,2.48), (7.485,2.265,7.715,2.48), (2.5,2.48,7.715,2.71), (2.5,2.48,7.715,2.71), (7.485,2.71,7.715,3.39), (7.485,2.71,7.715,3.39), (3.485,3.23,3.715,3.62), (3.485,3.23,3.715,3.62), (5.085,3.23,5.315,3.62), (5.085,3.23,5.315,3.62), (6.685,3.23,6.915,3.62), (6.685,3.23,6.915,3.62), (0,3.62,8.96,4.22), (0,3.62,8.96,4.22)])
R(gf180mcu_as_sc_mcu7t3v3_, metal1_pin, [(0,-0.3,8.96,0.3), (0,-0.3,8.96,0.3), (7.485,1.015,7.845,2.265), (7.485,1.015,7.845,2.265), (0.37,1.58,1.015,1.95), (0.37,1.58,1.015,1.95), (5.575,1.595,7.22,2.05), (5.575,1.595,7.22,2.05), (0,3.62,8.96,4.22), (0,3.62,8.96,4.22)])
R(gf180mcu_as_sc_mcu7t3v3_, lvpwell, [(-0.43,-0.43,9.39,1.77), (-0.43,-0.43,9.39,1.77)])
R(gf180mcu_as_sc_mcu7t3v3_, lvpwell_10, [(0.05,-0.25,0.55,0.25), (0.05,-0.25,0.55,0.25)])
gf180mcu_as_sc_mcu7t3v3_.add(gdstk.Label('VDD', (4.48,3.92), layer=34, texttype=10))
gf180mcu_as_sc_mcu7t3v3_.add(gdstk.Label('VSS', (4.48,0), layer=34, texttype=10))
gf180mcu_as_sc_mcu7t3v3_.add(gdstk.Label('Y', (7.665,1.64), layer=34, texttype=10))
gf180mcu_as_sc_mcu7t3v3_.add(gdstk.Label('A', (0.692,1.765), layer=34, texttype=10))
gf180mcu_as_sc_mcu7t3v3_.add(gdstk.Label('B', (6.397,1.822), layer=34, texttype=10))
gf180mcu_as_sc_mcu7t3v3_.add(gdstk.Label('VDD', (4.48,3.92), layer=34, texttype=10))
gf180mcu_as_sc_mcu7t3v3_.add(gdstk.Label('VSS', (4.48,0), layer=34, texttype=10))
gf180mcu_as_sc_mcu7t3v3_.add(gdstk.Label('Y', (7.665,1.64), layer=34, texttype=10))
gf180mcu_as_sc_mcu7t3v3_.add(gdstk.Label('A', (0.692,1.765), layer=34, texttype=10))
gf180mcu_as_sc_mcu7t3v3_.add(gdstk.Label('B', (6.397,1.822), layer=34, texttype=10))
gf180mcu_as_sc_mcu7t3v3_.add(gdstk.Label('VNW', (0.315,3.92), layer=21, texttype=10))
gf180mcu_as_sc_mcu7t3v3_.add(gdstk.Label('VNW', (0.315,3.92), layer=21, texttype=10))
gf180mcu_as_sc_mcu7t3v3_.add(gdstk.Label('VPW', (0.3,0), layer=204, texttype=10))
gf180mcu_as_sc_mcu7t3v3_.add(gdstk.Label('VPW', (0.3,0), layer=204, texttype=10))

lib.write_gds('gf180mcu_as_sc_mcu7t3v3__nand2b_4.gds')
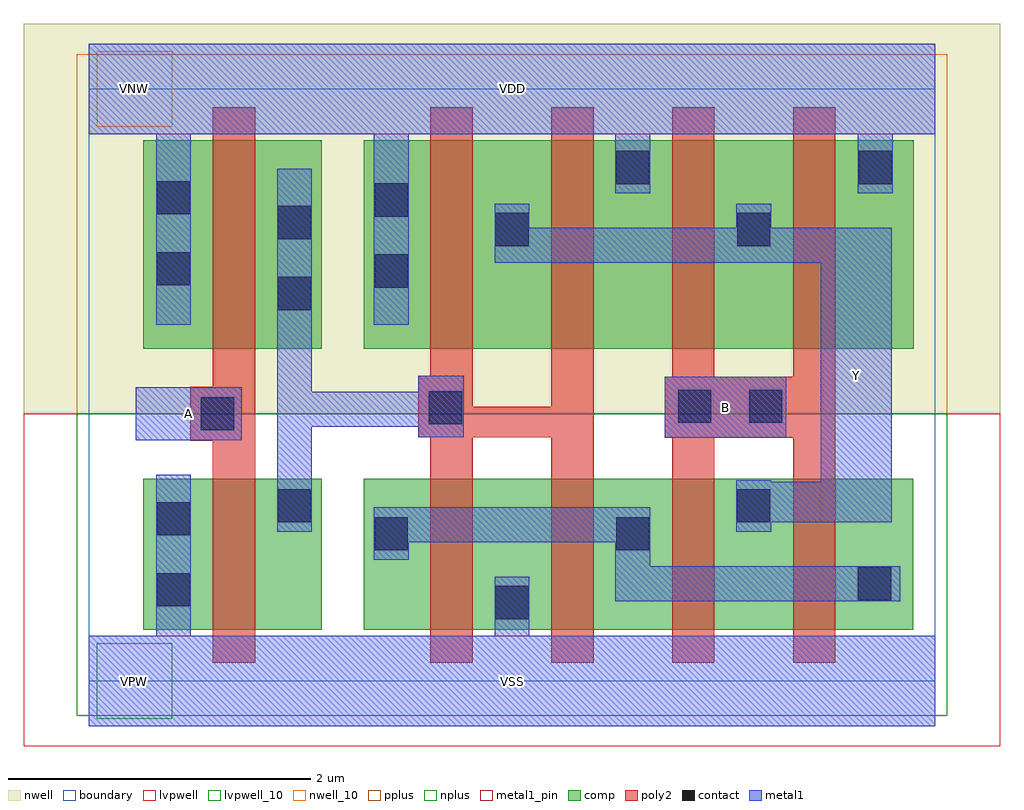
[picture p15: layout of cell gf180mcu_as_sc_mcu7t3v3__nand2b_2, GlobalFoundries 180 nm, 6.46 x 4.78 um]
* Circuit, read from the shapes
.subckt gf180mcu_as_sc_mcu7t3v3__nand2b_2 A B VDD VNW VSS Y
XM1 n1 A VSS VSUBS nfet_03v3 w=1u l=0.28u
XM2 VSS n1 n2 VSUBS nfet_03v3 w=1u l=0.28u m=2
XM3 Y B n2 VSUBS nfet_03v3 w=1u l=0.28u m=2
XM4 n1 A VDD VNW pfet_03v3 w=1.38u l=0.28u
XM5 Y n1 VDD VNW pfet_03v3 w=1.38u l=0.28u m=2
XM6 Y B VDD VNW pfet_03v3 w=1.38u l=0.28u m=2
.ends

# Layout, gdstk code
import gdstk
lib = gdstk.Library(unit=1e-6, precision=1e-09)
def R(c, l, rs):  # rectangles x0, y0, x1, y1
    for r in rs: c.add(gdstk.rectangle(r[:2], r[2:], *l))
boundary = (0, 0)
nwell = (21, 0)
nwell_10 = (21, 10)
comp = (22, 0)
poly2 = (30, 0)
pplus = (31, 0)
nplus = (32, 0)
contact = (33, 0)
metal1 = (34, 0)
metal1_pin = (34, 10)
lvpwell = (204, 0)
lvpwell_10 = (204, 10)

gf180mcu_as_sc_mcu7t3v3_ = lib.new_cell('gf180mcu_as_sc_mcu7t3v3__nand2b_2')
R(gf180mcu_as_sc_mcu7t3v3_, boundary, [(0,0,5.6,3.92), (0,0,5.6,3.92)])
R(gf180mcu_as_sc_mcu7t3v3_, nwell, [(-0.43,1.77,6.03,4.35), (-0.43,1.77,6.03,4.35)])
R(gf180mcu_as_sc_mcu7t3v3_, nwell_10, [(0.05,3.67,0.55,4.17), (0.05,3.67,0.55,4.17)])
R(gf180mcu_as_sc_mcu7t3v3_, comp, [(0.36,0.34,1.54,1.34), (0.36,0.34,1.54,1.34), (1.82,0.34,5.455,1.34), (1.82,0.34,5.455,1.34), (0.36,2.2,1.54,3.58), (0.36,2.2,1.54,3.58), (1.82,2.2,5.46,3.58), (1.82,2.2,5.46,3.58)])
R(gf180mcu_as_sc_mcu7t3v3_, poly2, [(0.82,0.12,1.1,1.59), (0.82,0.12,1.1,1.59), (2.26,0.12,2.54,1.615), (2.26,0.12,2.54,1.615), (3.06,0.12,3.34,1.615), (3.06,0.12,3.34,1.615), (3.86,0.12,4.14,1.61), (3.86,0.12,4.14,1.61), (4.66,0.12,4.94,1.61), (4.66,0.12,4.94,1.61), (0.67,1.59,1.1,1.95), (0.67,1.59,1.1,1.95), (3.81,1.61,4.94,2.015), (3.81,1.61,4.94,2.015), (2.18,1.615,3.34,1.815), (2.18,1.615,3.34,1.815), (2.18,1.815,2.54,2.02), (2.18,1.815,2.54,2.02), (3.06,1.815,3.34,3.8), (3.06,1.815,3.34,3.8), (0.82,1.95,1.1,3.8), (0.82,1.95,1.1,3.8), (3.86,2.015,4.14,3.8), (3.86,2.015,4.14,3.8), (4.66,2.015,4.94,3.8), (4.66,2.015,4.94,3.8), (2.26,2.02,2.54,3.8), (2.26,2.02,2.54,3.8)])
R(gf180mcu_as_sc_mcu7t3v3_, pplus, [(-0.08,1.77,5.68,4.15), (-0.08,1.77,5.68,4.15), (0.59,1.97,1.33,2.04), (0.59,1.97,1.33,2.04), (2.03,1.97,5.17,2.04), (2.03,1.97,5.17,2.04), (0.2,2.04,5.62,3.74), (0.2,2.04,5.62,3.74), (0.59,3.74,1.33,3.81), (0.59,3.74,1.33,3.81), (2.03,3.74,5.17,3.81), (2.03,3.74,5.17,3.81)])
R(gf180mcu_as_sc_mcu7t3v3_, nplus, [(-0.08,-0.23,5.68,1.77), (-0.08,-0.23,5.68,1.77), (-0.08,-0.23,5.68,1.77), (-0.08,-0.23,5.68,1.77)])
R(gf180mcu_as_sc_mcu7t3v3_, contact, [(2.69,0.41,2.91,0.63), (2.69,0.41,2.91,0.63), (0.45,0.495,0.67,0.715), (0.45,0.495,0.67,0.715), (5.09,0.535,5.31,0.755), (5.09,0.535,5.31,0.755), (1.89,0.865,2.11,1.085), (1.89,0.865,2.11,1.085), (3.49,0.865,3.71,1.085), (3.49,0.865,3.71,1.085), (0.45,0.965,0.67,1.185), (0.45,0.965,0.67,1.185), (1.25,1.05,1.47,1.27), (1.25,1.05,1.47,1.27), (4.29,1.05,4.51,1.27), (4.29,1.05,4.51,1.27), (0.74,1.66,0.96,1.88), (0.74,1.66,0.96,1.88), (2.25,1.7,2.47,1.92), (2.25,1.7,2.47,1.92), (3.9,1.71,4.12,1.93), (3.9,1.71,4.12,1.93), (4.37,1.71,4.59,1.93), (4.37,1.71,4.59,1.93), (1.25,2.455,1.47,2.675), (1.25,2.455,1.47,2.675), (1.89,2.605,2.11,2.825), (1.89,2.605,2.11,2.825), (0.45,2.62,0.67,2.84), (0.45,2.62,0.67,2.84), (2.69,2.88,2.91,3.1), (2.69,2.88,2.91,3.1), (4.29,2.88,4.51,3.1), (4.29,2.88,4.51,3.1), (1.25,2.925,1.47,3.145), (1.25,2.925,1.47,3.145), (1.89,3.075,2.11,3.295), (1.89,3.075,2.11,3.295), (0.45,3.09,0.67,3.31), (0.45,3.09,0.67,3.31), (3.49,3.29,3.71,3.51), (3.49,3.29,3.71,3.51), (5.095,3.29,5.315,3.51), (5.095,3.29,5.315,3.51)])
R(gf180mcu_as_sc_mcu7t3v3_, metal1, [(0,-0.3,5.6,0.3), (0,-0.3,5.6,0.3), (0.445,0.3,0.675,1.365), (0.445,0.3,0.675,1.365), (2.685,0.3,2.915,0.69), (2.685,0.3,2.915,0.69), (3.485,0.53,5.37,0.76), (3.485,0.53,5.37,0.76), (3.485,0.76,3.715,0.92), (3.485,0.76,3.715,0.92), (1.885,0.805,2.115,0.92), (1.885,0.805,2.115,0.92), (1.885,0.92,3.715,1.15), (1.885,0.92,3.715,1.15), (1.245,0.99,1.475,1.685), (1.245,0.99,1.475,1.685), (4.285,0.99,4.515,1.05), (4.285,0.99,4.515,1.05), (4.285,1.05,5.315,1.32), (4.285,1.05,5.315,1.32), (4.285,1.32,4.515,1.33), (4.285,1.32,4.515,1.33), (4.845,1.32,5.315,2.77), (4.845,1.32,5.315,2.77), (0.31,1.595,1.01,1.945), (0.31,1.595,1.01,1.945), (3.81,1.61,4.615,2.015), (3.81,1.61,4.615,2.015), (2.18,1.615,2.48,1.685), (2.18,1.615,2.48,1.685), (1.245,1.685,2.48,1.915), (1.245,1.685,2.48,1.915), (1.245,1.915,1.475,3.39), (1.245,1.915,1.475,3.39), (2.18,1.915,2.48,2.02), (2.18,1.915,2.48,2.02), (0.445,2.36,0.675,3.62), (0.445,2.36,0.675,3.62), (1.885,2.36,2.115,3.62), (1.885,2.36,2.115,3.62), (2.685,2.77,5.315,3), (2.685,2.77,5.315,3), (2.685,3,2.915,3.16), (2.685,3,2.915,3.16), (4.285,3,4.515,3.16), (4.285,3,4.515,3.16), (3.485,3.23,3.715,3.62), (3.485,3.23,3.715,3.62), (5.09,3.23,5.32,3.62), (5.09,3.23,5.32,3.62), (0,3.62,5.6,4.22), (0,3.62,5.6,4.22)])
R(gf180mcu_as_sc_mcu7t3v3_, metal1_pin, [(0,-0.3,5.6,0.3), (0,-0.3,5.6,0.3), (4.845,1.05,5.315,3), (4.845,1.05,5.315,3), (0.31,1.595,1.01,1.945), (0.31,1.595,1.01,1.945), (3.81,1.61,4.615,2.015), (3.81,1.61,4.615,2.015), (0,3.62,5.6,4.22), (0,3.62,5.6,4.22)])
R(gf180mcu_as_sc_mcu7t3v3_, lvpwell, [(-0.43,-0.43,6.03,1.77), (-0.43,-0.43,6.03,1.77)])
R(gf180mcu_as_sc_mcu7t3v3_, lvpwell_10, [(0.05,-0.25,0.55,0.25), (0.05,-0.25,0.55,0.25)])
gf180mcu_as_sc_mcu7t3v3_.add(gdstk.Label('VDD', (2.8,3.92), layer=34, texttype=10))
gf180mcu_as_sc_mcu7t3v3_.add(gdstk.Label('VSS', (2.8,0), layer=34, texttype=10))
gf180mcu_as_sc_mcu7t3v3_.add(gdstk.Label('Y', (5.08,2.025), layer=34, texttype=10))
gf180mcu_as_sc_mcu7t3v3_.add(gdstk.Label('B', (4.212,1.812), layer=34, texttype=10))
gf180mcu_as_sc_mcu7t3v3_.add(gdstk.Label('A', (0.66,1.77), layer=34, texttype=10))
gf180mcu_as_sc_mcu7t3v3_.add(gdstk.Label('VDD', (2.8,3.92), layer=34, texttype=10))
gf180mcu_as_sc_mcu7t3v3_.add(gdstk.Label('VSS', (2.8,0), layer=34, texttype=10))
gf180mcu_as_sc_mcu7t3v3_.add(gdstk.Label('Y', (5.08,2.025), layer=34, texttype=10))
gf180mcu_as_sc_mcu7t3v3_.add(gdstk.Label('B', (4.212,1.812), layer=34, texttype=10))
gf180mcu_as_sc_mcu7t3v3_.add(gdstk.Label('A', (0.66,1.77), layer=34, texttype=10))
gf180mcu_as_sc_mcu7t3v3_.add(gdstk.Label('VNW', (0.3,3.92), layer=21, texttype=10))
gf180mcu_as_sc_mcu7t3v3_.add(gdstk.Label('VNW', (0.3,3.92), layer=21, texttype=10))
gf180mcu_as_sc_mcu7t3v3_.add(gdstk.Label('VPW', (0.3,0), layer=204, texttype=10))
gf180mcu_as_sc_mcu7t3v3_.add(gdstk.Label('VPW', (0.3,0), layer=204, texttype=10))

lib.write_gds('gf180mcu_as_sc_mcu7t3v3__nand2b_2.gds')
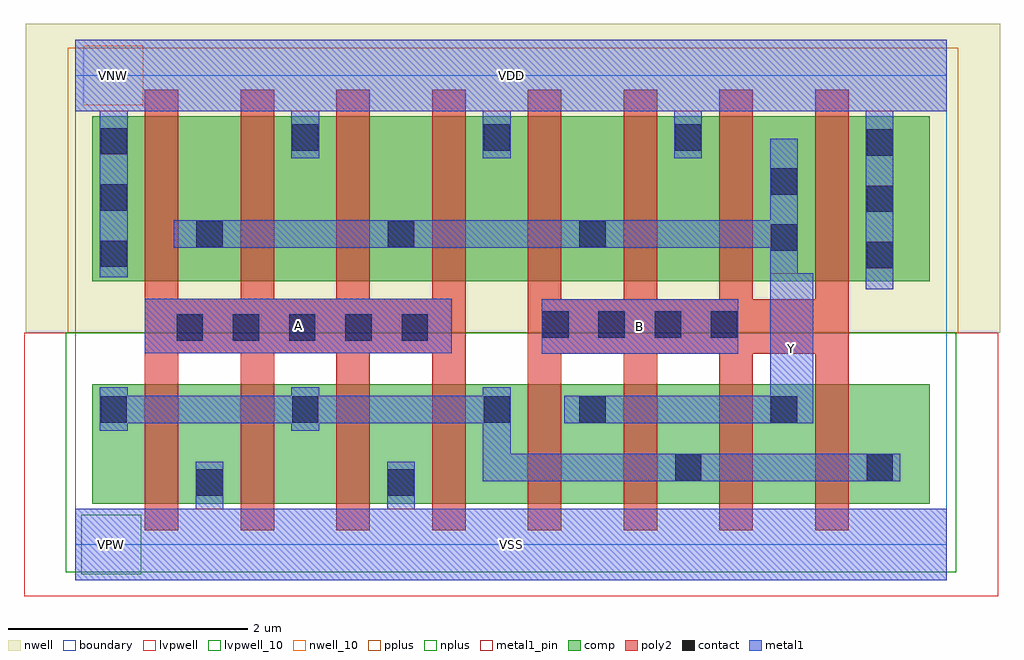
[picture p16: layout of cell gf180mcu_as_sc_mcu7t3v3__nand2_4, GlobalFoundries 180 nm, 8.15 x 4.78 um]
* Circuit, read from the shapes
.subckt gf180mcu_as_sc_mcu7t3v3__nand2_4 A B VDD VNW VSS Y
XM1 VSS A n1 VSUBS nfet_03v3 w=1u l=0.28u m=4
XM2 Y B n1 VSUBS nfet_03v3 w=1u l=0.28u m=4
XM3 Y A VDD VNW pfet_03v3 w=1.38u l=0.28u m=4
XM4 Y B VDD VNW pfet_03v3 w=1.38u l=0.28u m=4
.ends

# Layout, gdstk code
import gdstk
lib = gdstk.Library(unit=1e-6, precision=1e-09)
def R(c, l, rs):  # rectangles x0, y0, x1, y1
    for r in rs: c.add(gdstk.rectangle(r[:2], r[2:], *l))
boundary = (0, 0)
nwell = (21, 0)
nwell_10 = (21, 10)
comp = (22, 0)
poly2 = (30, 0)
pplus = (31, 0)
nplus = (32, 0)
contact = (33, 0)
metal1 = (34, 0)
metal1_pin = (34, 10)
lvpwell = (204, 0)
lvpwell_10 = (204, 10)

gf180mcu_as_sc_mcu7t3v3_ = lib.new_cell('gf180mcu_as_sc_mcu7t3v3__nand2_4')
R(gf180mcu_as_sc_mcu7t3v3_, boundary, [(0,0,7.28,3.92), (0,0,7.28,3.92)])
R(gf180mcu_as_sc_mcu7t3v3_, nwell, [(-0.415,1.77,7.725,4.35), (-0.415,1.77,7.725,4.35)])
R(gf180mcu_as_sc_mcu7t3v3_, nwell_10, [(0.065,3.67,0.565,4.17), (0.065,3.67,0.565,4.17)])
R(gf180mcu_as_sc_mcu7t3v3_, comp, [(0.14,0.34,7.14,1.34), (0.14,0.34,7.14,1.34), (0.14,2.2,7.14,3.58), (0.14,2.2,7.14,3.58)])
R(gf180mcu_as_sc_mcu7t3v3_, poly2, [(0.58,0.12,0.86,1.6), (0.58,0.12,0.86,1.6), (1.38,0.12,1.66,1.6), (1.38,0.12,1.66,1.6), (2.18,0.12,2.46,1.6), (2.18,0.12,2.46,1.6), (2.98,0.12,3.26,1.6), (2.98,0.12,3.26,1.6), (3.78,0.12,4.06,1.595), (3.78,0.12,4.06,1.595), (4.58,0.12,4.86,1.595), (4.58,0.12,4.86,1.595), (5.38,0.12,5.66,1.595), (5.38,0.12,5.66,1.595), (6.18,0.12,6.46,1.595), (6.18,0.12,6.46,1.595), (3.78,1.595,6.46,2.05), (3.78,1.595,6.46,2.05), (0.58,1.6,3.26,2.055), (0.58,1.6,3.26,2.055), (3.78,2.05,4.06,3.8), (3.78,2.05,4.06,3.8), (4.58,2.05,4.86,3.8), (4.58,2.05,4.86,3.8), (5.38,2.05,5.66,3.8), (5.38,2.05,5.66,3.8), (6.18,2.05,6.46,3.8), (6.18,2.05,6.46,3.8), (0.58,2.055,0.86,3.8), (0.58,2.055,0.86,3.8), (1.38,2.055,1.66,3.8), (1.38,2.055,1.66,3.8), (2.18,2.055,2.46,3.8), (2.18,2.055,2.46,3.8), (2.98,2.055,3.26,3.8), (2.98,2.055,3.26,3.8)])
R(gf180mcu_as_sc_mcu7t3v3_, pplus, [(-0.065,1.77,7.375,4.15), (-0.065,1.77,7.375,4.15), (0.35,1.97,6.69,2.04), (0.35,1.97,6.69,2.04), (-0.02,2.04,7.3,3.74), (-0.02,2.04,7.3,3.74), (0.35,3.74,6.69,3.81), (0.35,3.74,6.69,3.81)])
R(gf180mcu_as_sc_mcu7t3v3_, nplus, [(-0.08,-0.23,7.36,1.77), (-0.08,-0.23,7.36,1.77), (-0.08,-0.23,7.36,1.77), (-0.08,-0.23,7.36,1.77)])
R(gf180mcu_as_sc_mcu7t3v3_, contact, [(1.01,0.41,1.23,0.63), (1.01,0.41,1.23,0.63), (2.61,0.41,2.83,0.63), (2.61,0.41,2.83,0.63), (5.01,0.535,5.23,0.755), (5.01,0.535,5.23,0.755), (6.61,0.535,6.83,0.755), (6.61,0.535,6.83,0.755), (0.21,1.02,0.43,1.24), (0.21,1.02,0.43,1.24), (1.81,1.02,2.03,1.24), (1.81,1.02,2.03,1.24), (3.41,1.02,3.63,1.24), (3.41,1.02,3.63,1.24), (4.21,1.02,4.43,1.24), (4.21,1.02,4.43,1.24), (5.81,1.02,6.03,1.24), (5.81,1.02,6.03,1.24), (0.845,1.705,1.065,1.925), (0.845,1.705,1.065,1.925), (1.315,1.705,1.535,1.925), (1.315,1.705,1.535,1.925), (1.785,1.705,2.005,1.925), (1.785,1.705,2.005,1.925), (2.255,1.705,2.475,1.925), (2.255,1.705,2.475,1.925), (2.725,1.705,2.945,1.925), (2.725,1.705,2.945,1.925), (3.9,1.73,4.12,1.95), (3.9,1.73,4.12,1.95), (4.37,1.73,4.59,1.95), (4.37,1.73,4.59,1.95), (4.84,1.73,5.06,1.95), (4.84,1.73,5.06,1.95), (5.31,1.73,5.53,1.95), (5.31,1.73,5.53,1.95), (6.61,2.31,6.83,2.53), (6.61,2.31,6.83,2.53), (0.21,2.32,0.43,2.54), (0.21,2.32,0.43,2.54), (5.81,2.455,6.03,2.675), (5.81,2.455,6.03,2.675), (1.01,2.485,1.23,2.705), (1.01,2.485,1.23,2.705), (2.61,2.485,2.83,2.705), (2.61,2.485,2.83,2.705), (4.21,2.485,4.43,2.705), (4.21,2.485,4.43,2.705), (6.61,2.78,6.83,3), (6.61,2.78,6.83,3), (0.21,2.79,0.43,3.01), (0.21,2.79,0.43,3.01), (5.81,2.925,6.03,3.145), (5.81,2.925,6.03,3.145), (6.61,3.25,6.83,3.47), (6.61,3.25,6.83,3.47), (0.21,3.26,0.43,3.48), (0.21,3.26,0.43,3.48), (1.81,3.29,2.03,3.51), (1.81,3.29,2.03,3.51), (3.41,3.29,3.63,3.51), (3.41,3.29,3.63,3.51), (5.01,3.29,5.23,3.51), (5.01,3.29,5.23,3.51)])
R(gf180mcu_as_sc_mcu7t3v3_, metal1, [(0,-0.3,7.28,0.3), (0,-0.3,7.28,0.3), (1.005,0.3,1.235,0.69), (1.005,0.3,1.235,0.69), (2.605,0.3,2.835,0.69), (2.605,0.3,2.835,0.69), (3.405,0.53,6.89,0.76), (3.405,0.53,6.89,0.76), (3.405,0.76,3.635,1.015), (3.405,0.76,3.635,1.015), (0.205,0.95,0.435,1.015), (0.205,0.95,0.435,1.015), (1.805,0.95,2.035,1.015), (1.805,0.95,2.035,1.015), (0.205,1.015,3.635,1.245), (0.205,1.015,3.635,1.245), (4.085,1.015,6.165,1.245), (4.085,1.015,6.165,1.245), (0.205,1.245,0.435,1.315), (0.205,1.245,0.435,1.315), (1.805,1.245,2.035,1.315), (1.805,1.245,2.035,1.315), (3.405,1.245,3.635,1.315), (3.405,1.245,3.635,1.315), (5.805,1.245,6.165,2.265), (5.805,1.245,6.165,2.265), (3.895,1.595,5.54,2.05), (3.895,1.595,5.54,2.05), (0.58,1.6,3.145,2.055), (0.58,1.6,3.145,2.055), (6.605,2.135,6.835,3.62), (6.605,2.135,6.835,3.62), (0.205,2.235,0.435,3.62), (0.205,2.235,0.435,3.62), (5.805,2.265,6.035,2.48), (5.805,2.265,6.035,2.48), (0.82,2.48,6.035,2.71), (0.82,2.48,6.035,2.71), (5.805,2.71,6.035,3.39), (5.805,2.71,6.035,3.39), (1.805,3.23,2.035,3.62), (1.805,3.23,2.035,3.62), (3.405,3.23,3.635,3.62), (3.405,3.23,3.635,3.62), (5.005,3.23,5.235,3.62), (5.005,3.23,5.235,3.62), (0,3.62,7.28,4.22), (0,3.62,7.28,4.22)])
R(gf180mcu_as_sc_mcu7t3v3_, metal1_pin, [(0,-0.3,7.28,0.3), (0,-0.3,7.28,0.3), (5.805,1.015,6.165,2.265), (5.805,1.015,6.165,2.265), (3.895,1.595,5.54,2.05), (3.895,1.595,5.54,2.05), (0.58,1.6,3.145,2.055), (0.58,1.6,3.145,2.055), (0,3.62,7.28,4.22), (0,3.62,7.28,4.22)])
R(gf180mcu_as_sc_mcu7t3v3_, lvpwell, [(-0.43,-0.43,7.71,1.77), (-0.43,-0.43,7.71,1.77)])
R(gf180mcu_as_sc_mcu7t3v3_, lvpwell_10, [(0.05,-0.25,0.55,0.25), (0.05,-0.25,0.55,0.25)])
gf180mcu_as_sc_mcu7t3v3_.add(gdstk.Label('VDD', (3.64,3.92), layer=34, texttype=10))
gf180mcu_as_sc_mcu7t3v3_.add(gdstk.Label('VSS', (3.64,0), layer=34, texttype=10))
gf180mcu_as_sc_mcu7t3v3_.add(gdstk.Label('Y', (5.985,1.64), layer=34, texttype=10))
gf180mcu_as_sc_mcu7t3v3_.add(gdstk.Label('A', (1.862,1.827), layer=34, texttype=10))
gf180mcu_as_sc_mcu7t3v3_.add(gdstk.Label('B', (4.717,1.822), layer=34, texttype=10))
gf180mcu_as_sc_mcu7t3v3_.add(gdstk.Label('VDD', (3.64,3.92), layer=34, texttype=10))
gf180mcu_as_sc_mcu7t3v3_.add(gdstk.Label('VSS', (3.64,0), layer=34, texttype=10))
gf180mcu_as_sc_mcu7t3v3_.add(gdstk.Label('Y', (5.985,1.64), layer=34, texttype=10))
gf180mcu_as_sc_mcu7t3v3_.add(gdstk.Label('A', (1.862,1.827), layer=34, texttype=10))
gf180mcu_as_sc_mcu7t3v3_.add(gdstk.Label('B', (4.717,1.822), layer=34, texttype=10))
gf180mcu_as_sc_mcu7t3v3_.add(gdstk.Label('VNW', (0.315,3.92), layer=21, texttype=10))
gf180mcu_as_sc_mcu7t3v3_.add(gdstk.Label('VNW', (0.315,3.92), layer=21, texttype=10))
gf180mcu_as_sc_mcu7t3v3_.add(gdstk.Label('VPW', (0.3,0), layer=204, texttype=10))
gf180mcu_as_sc_mcu7t3v3_.add(gdstk.Label('VPW', (0.3,0), layer=204, texttype=10))

lib.write_gds('gf180mcu_as_sc_mcu7t3v3__nand2_4.gds')
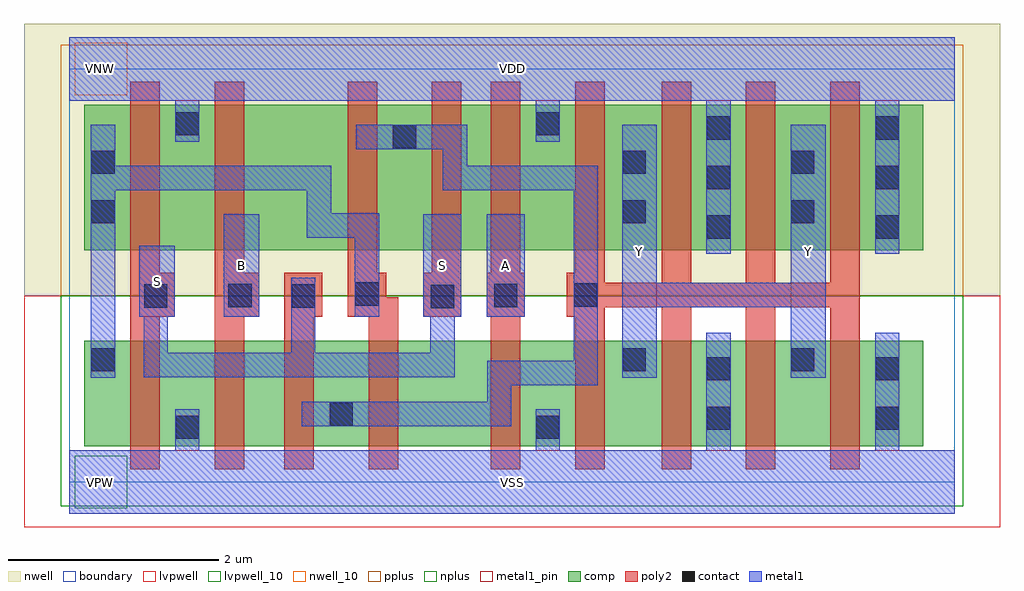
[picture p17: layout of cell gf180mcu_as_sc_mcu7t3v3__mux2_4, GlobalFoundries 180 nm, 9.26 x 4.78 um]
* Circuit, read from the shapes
.subckt gf180mcu_as_sc_mcu7t3v3__mux2_4 A B S VDD VNW VSS Y
XM1 VSS S n1 VSUBS nfet_03v3 w=1u l=0.28u
XM2 n2 B VSS VSUBS nfet_03v3 w=1u l=0.28u
XM3 n3 S n2 VSUBS nfet_03v3 w=1u l=0.28u
XM4 n4 n1 n3 VSUBS nfet_03v3 w=1u l=0.28u
XM5 VSS A n4 VSUBS nfet_03v3 w=1u l=0.28u
XM6 Y n3 VSS VSUBS nfet_03v3 w=1u l=0.28u m=4
XM7 VDD S n1 VNW pfet_03v3 w=1.38u l=0.28u
XM8 n5 B VDD VNW pfet_03v3 w=1.38u l=0.28u
XM9 n3 n1 n5 VNW pfet_03v3 w=1.38u l=0.28u
XM10 n6 S n3 VNW pfet_03v3 w=1.38u l=0.28u
XM11 VDD A n6 VNW pfet_03v3 w=1.38u l=0.28u
XM12 Y n3 VDD VNW pfet_03v3 w=1.38u l=0.28u m=4
.ends

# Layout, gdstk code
import gdstk
lib = gdstk.Library(unit=1e-6, precision=1e-09)
def R(c, l, rs):  # rectangles x0, y0, x1, y1
    for r in rs: c.add(gdstk.rectangle(r[:2], r[2:], *l))
boundary = (0, 0)
nwell = (21, 0)
nwell_10 = (21, 10)
comp = (22, 0)
poly2 = (30, 0)
pplus = (31, 0)
nplus = (32, 0)
contact = (33, 0)
metal1 = (34, 0)
metal1_pin = (34, 10)
lvpwell = (204, 0)
lvpwell_10 = (204, 10)

gf180mcu_as_sc_mcu7t3v3_ = lib.new_cell('gf180mcu_as_sc_mcu7t3v3__mux2_4')
R(gf180mcu_as_sc_mcu7t3v3_, boundary, [(0,0,8.4,3.92), (0,0,8.4,3.92)])
R(gf180mcu_as_sc_mcu7t3v3_, nwell, [(-0.43,1.77,8.83,4.35), (-0.43,1.77,8.83,4.35)])
R(gf180mcu_as_sc_mcu7t3v3_, nwell_10, [(0.05,3.67,0.55,4.17), (0.05,3.67,0.55,4.17)])
R(gf180mcu_as_sc_mcu7t3v3_, comp, [(0.14,0.34,8.1,1.34), (0.14,0.34,8.1,1.34), (0.14,2.2,8.1,3.58), (0.14,2.2,8.1,3.58)])
R(gf180mcu_as_sc_mcu7t3v3_, poly2, [(0.58,0.12,0.86,1.57), (0.58,0.12,0.86,1.57), (1.38,0.12,1.66,1.57), (1.38,0.12,1.66,1.57), (2.04,0.12,2.32,1.57), (2.04,0.12,2.32,1.57), (2.84,0.12,3.12,1.57), (2.84,0.12,3.12,1.57), (4,0.12,4.28,1.57), (4,0.12,4.28,1.57), (4.8,0.12,5.08,1.57), (4.8,0.12,5.08,1.57), (5.62,0.12,5.9,1.66), (5.62,0.12,5.9,1.66), (6.42,0.12,6.7,1.66), (6.42,0.12,6.7,1.66), (7.22,0.12,7.5,1.66), (7.22,0.12,7.5,1.66), (0.58,1.57,1,1.985), (0.58,1.57,1,1.985), (1.38,1.57,1.8,1.985), (1.38,1.57,1.8,1.985), (2.04,1.57,2.4,1.985), (2.04,1.57,2.4,1.985), (2.64,1.57,3.12,1.755), (2.64,1.57,3.12,1.755), (3.36,1.57,3.72,1.985), (3.36,1.57,3.72,1.985), (3.96,1.57,4.32,1.985), (3.96,1.57,4.32,1.985), (4.72,1.57,5.08,1.66), (4.72,1.57,5.08,1.66), (4.72,1.66,7.5,1.89), (4.72,1.66,7.5,1.89), (2.64,1.755,3.005,1.985), (2.64,1.755,3.005,1.985), (4.72,1.89,5.08,1.985), (4.72,1.89,5.08,1.985), (5.62,1.89,5.9,3.8), (5.62,1.89,5.9,3.8), (6.42,1.89,6.7,3.8), (6.42,1.89,6.7,3.8), (7.22,1.89,7.5,3.8), (7.22,1.89,7.5,3.8), (0.58,1.985,0.86,3.8), (0.58,1.985,0.86,3.8), (1.38,1.985,1.66,3.8), (1.38,1.985,1.66,3.8), (2.64,1.985,2.92,3.8), (2.64,1.985,2.92,3.8), (3.44,1.985,3.72,3.8), (3.44,1.985,3.72,3.8), (4,1.985,4.28,3.8), (4,1.985,4.28,3.8), (4.8,1.985,5.08,3.8), (4.8,1.985,5.08,3.8)])
R(gf180mcu_as_sc_mcu7t3v3_, pplus, [(-0.08,1.77,8.48,4.15), (-0.08,1.77,8.48,4.15), (0.35,1.97,1.89,2.04), (0.35,1.97,1.89,2.04), (2.41,1.97,7.73,2.04), (2.41,1.97,7.73,2.04), (-0.02,2.04,8.26,3.74), (-0.02,2.04,8.26,3.74), (0.35,3.74,1.89,3.81), (0.35,3.74,1.89,3.81), (2.41,3.74,7.73,3.81), (2.41,3.74,7.73,3.81)])
R(gf180mcu_as_sc_mcu7t3v3_, nplus, [(-0.08,-0.23,8.48,1.77), (-0.08,-0.23,8.48,1.77), (-0.08,-0.23,8.48,1.77), (-0.08,-0.23,8.48,1.77)])
R(gf180mcu_as_sc_mcu7t3v3_, contact, [(1.01,0.41,1.23,0.63), (1.01,0.41,1.23,0.63), (4.43,0.41,4.65,0.63), (4.43,0.41,4.65,0.63), (6.05,0.495,6.27,0.715), (6.05,0.495,6.27,0.715), (7.65,0.495,7.87,0.715), (7.65,0.495,7.87,0.715), (2.47,0.535,2.69,0.755), (2.47,0.535,2.69,0.755), (6.05,0.965,6.27,1.185), (6.05,0.965,6.27,1.185), (7.65,0.965,7.87,1.185), (7.65,0.965,7.87,1.185), (0.21,1.05,0.43,1.27), (0.21,1.05,0.43,1.27), (5.25,1.05,5.47,1.27), (5.25,1.05,5.47,1.27), (6.85,1.05,7.07,1.27), (6.85,1.05,7.07,1.27), (3.43,1.65,3.65,1.87), (3.43,1.65,3.65,1.87), (0.71,1.655,0.93,1.875), (0.71,1.655,0.93,1.875), (2.11,1.655,2.33,1.875), (2.11,1.655,2.33,1.875), (1.51,1.66,1.73,1.88), (1.51,1.66,1.73,1.88), (4.03,1.66,4.25,1.88), (4.03,1.66,4.25,1.88), (4.79,1.665,5.01,1.885), (4.79,1.665,5.01,1.885), (2.715,1.675,2.935,1.895), (2.715,1.675,2.935,1.895), (6.05,2.31,6.27,2.53), (6.05,2.31,6.27,2.53), (7.65,2.31,7.87,2.53), (7.65,2.31,7.87,2.53), (0.21,2.455,0.43,2.675), (0.21,2.455,0.43,2.675), (5.25,2.455,5.47,2.675), (5.25,2.455,5.47,2.675), (6.85,2.455,7.07,2.675), (6.85,2.455,7.07,2.675), (6.05,2.78,6.27,3), (6.05,2.78,6.27,3), (7.65,2.78,7.87,3), (7.65,2.78,7.87,3), (0.21,2.925,0.43,3.145), (0.21,2.925,0.43,3.145), (5.25,2.925,5.47,3.145), (5.25,2.925,5.47,3.145), (6.85,2.925,7.07,3.145), (6.85,2.925,7.07,3.145), (3.07,3.165,3.29,3.385), (3.07,3.165,3.29,3.385), (6.05,3.25,6.27,3.47), (6.05,3.25,6.27,3.47), (7.65,3.25,7.87,3.47), (7.65,3.25,7.87,3.47), (1.01,3.29,1.23,3.51), (1.01,3.29,1.23,3.51), (4.43,3.29,4.65,3.51), (4.43,3.29,4.65,3.51)])
R(gf180mcu_as_sc_mcu7t3v3_, metal1, [(0,-0.3,8.4,0.3), (0,-0.3,8.4,0.3), (1.005,0.3,1.235,0.69), (1.005,0.3,1.235,0.69), (4.425,0.3,4.655,0.69), (4.425,0.3,4.655,0.69), (6.045,0.3,6.275,1.415), (6.045,0.3,6.275,1.415), (7.645,0.3,7.875,1.415), (7.645,0.3,7.875,1.415), (2.205,0.53,4.195,0.76), (2.205,0.53,4.195,0.76), (3.965,0.76,4.195,0.92), (3.965,0.76,4.195,0.92), (3.965,0.92,5.015,1.15), (3.965,0.92,5.015,1.15), (0.205,0.99,0.435,2.77), (0.205,0.99,0.435,2.77), (5.245,0.99,5.575,1.66), (5.245,0.99,5.575,1.66), (6.845,0.99,7.175,1.66), (6.845,0.99,7.175,1.66), (0.705,0.995,3.655,1.225), (0.705,0.995,3.655,1.225), (4.785,1.15,5.015,2.77), (4.785,1.15,5.015,2.77), (0.705,1.225,0.935,1.57), (0.705,1.225,0.935,1.57), (2.105,1.225,2.335,1.94), (2.105,1.225,2.335,1.94), (3.425,1.225,3.655,1.57), (3.425,1.225,3.655,1.57), (0.665,1.57,1,2.24), (0.665,1.57,1,2.24), (1.465,1.57,1.8,2.54), (1.465,1.57,1.8,2.54), (2.71,1.57,2.94,2.32), (2.71,1.57,2.94,2.32), (3.36,1.57,3.72,2.54), (3.36,1.57,3.72,2.54), (3.96,1.57,4.32,2.54), (3.96,1.57,4.32,2.54), (5.245,1.66,7.175,1.89), (5.245,1.66,7.175,1.89), (5.245,1.89,5.575,3.39), (5.245,1.89,5.575,3.39), (6.845,1.89,7.175,3.39), (6.845,1.89,7.175,3.39), (6.045,2.165,6.275,3.62), (6.045,2.165,6.275,3.62), (7.645,2.165,7.875,3.62), (7.645,2.165,7.875,3.62), (2.255,2.32,2.94,2.55), (2.255,2.32,2.94,2.55), (2.255,2.55,2.485,2.77), (2.255,2.55,2.485,2.77), (0.205,2.77,2.485,3), (0.205,2.77,2.485,3), (3.545,2.77,5.015,3), (3.545,2.77,5.015,3), (0.205,3,0.435,3.39), (0.205,3,0.435,3.39), (3.545,3,3.775,3.16), (3.545,3,3.775,3.16), (2.72,3.16,3.775,3.39), (2.72,3.16,3.775,3.39), (1.005,3.23,1.235,3.62), (1.005,3.23,1.235,3.62), (4.425,3.23,4.655,3.62), (4.425,3.23,4.655,3.62), (0,3.62,8.4,4.22), (0,3.62,8.4,4.22)])
R(gf180mcu_as_sc_mcu7t3v3_, metal1_pin, [(0,-0.3,8.4,0.3), (0,-0.3,8.4,0.3), (5.245,0.99,5.575,3.39), (5.245,0.99,5.575,3.39), (6.845,0.99,7.175,3.39), (6.845,0.99,7.175,3.39), (0.665,1.57,1,2.24), (0.665,1.57,1,2.24), (1.465,1.57,1.8,2.54), (1.465,1.57,1.8,2.54), (3.36,1.57,3.72,2.54), (3.36,1.57,3.72,2.54), (3.96,1.57,4.32,2.54), (3.96,1.57,4.32,2.54), (0,3.62,8.4,4.22), (0,3.62,8.4,4.22)])
R(gf180mcu_as_sc_mcu7t3v3_, lvpwell, [(-0.43,-0.43,8.83,1.77), (-0.43,-0.43,8.83,1.77)])
R(gf180mcu_as_sc_mcu7t3v3_, lvpwell_10, [(0.05,-0.25,0.55,0.25), (0.05,-0.25,0.55,0.25)])
gf180mcu_as_sc_mcu7t3v3_.add(gdstk.Label('VDD', (4.2,3.92), layer=34, texttype=10))
gf180mcu_as_sc_mcu7t3v3_.add(gdstk.Label('VSS', (4.2,0), layer=34, texttype=10))
gf180mcu_as_sc_mcu7t3v3_.add(gdstk.Label('S', (3.54,2.055), layer=34, texttype=10))
gf180mcu_as_sc_mcu7t3v3_.add(gdstk.Label('S', (0.832,1.905), layer=34, texttype=10))
gf180mcu_as_sc_mcu7t3v3_.add(gdstk.Label('B', (1.632,2.055), layer=34, texttype=10))
gf180mcu_as_sc_mcu7t3v3_.add(gdstk.Label('A', (4.14,2.055), layer=34, texttype=10))
gf180mcu_as_sc_mcu7t3v3_.add(gdstk.Label('Y', (7.01,2.19), layer=34, texttype=10))
gf180mcu_as_sc_mcu7t3v3_.add(gdstk.Label('Y', (5.41,2.19), layer=34, texttype=10))
gf180mcu_as_sc_mcu7t3v3_.add(gdstk.Label('VDD', (4.2,3.92), layer=34, texttype=10))
gf180mcu_as_sc_mcu7t3v3_.add(gdstk.Label('VSS', (4.2,0), layer=34, texttype=10))
gf180mcu_as_sc_mcu7t3v3_.add(gdstk.Label('S', (3.54,2.055), layer=34, texttype=10))
gf180mcu_as_sc_mcu7t3v3_.add(gdstk.Label('S', (0.832,1.905), layer=34, texttype=10))
gf180mcu_as_sc_mcu7t3v3_.add(gdstk.Label('B', (1.632,2.055), layer=34, texttype=10))
gf180mcu_as_sc_mcu7t3v3_.add(gdstk.Label('A', (4.14,2.055), layer=34, texttype=10))
gf180mcu_as_sc_mcu7t3v3_.add(gdstk.Label('Y', (7.01,2.19), layer=34, texttype=10))
gf180mcu_as_sc_mcu7t3v3_.add(gdstk.Label('Y', (5.41,2.19), layer=34, texttype=10))
gf180mcu_as_sc_mcu7t3v3_.add(gdstk.Label('VNW', (0.3,3.92), layer=21, texttype=10))
gf180mcu_as_sc_mcu7t3v3_.add(gdstk.Label('VNW', (0.3,3.92), layer=21, texttype=10))
gf180mcu_as_sc_mcu7t3v3_.add(gdstk.Label('VPW', (0.3,0), layer=204, texttype=10))
gf180mcu_as_sc_mcu7t3v3_.add(gdstk.Label('VPW', (0.3,0), layer=204, texttype=10))

lib.write_gds('gf180mcu_as_sc_mcu7t3v3__mux2_4.gds')
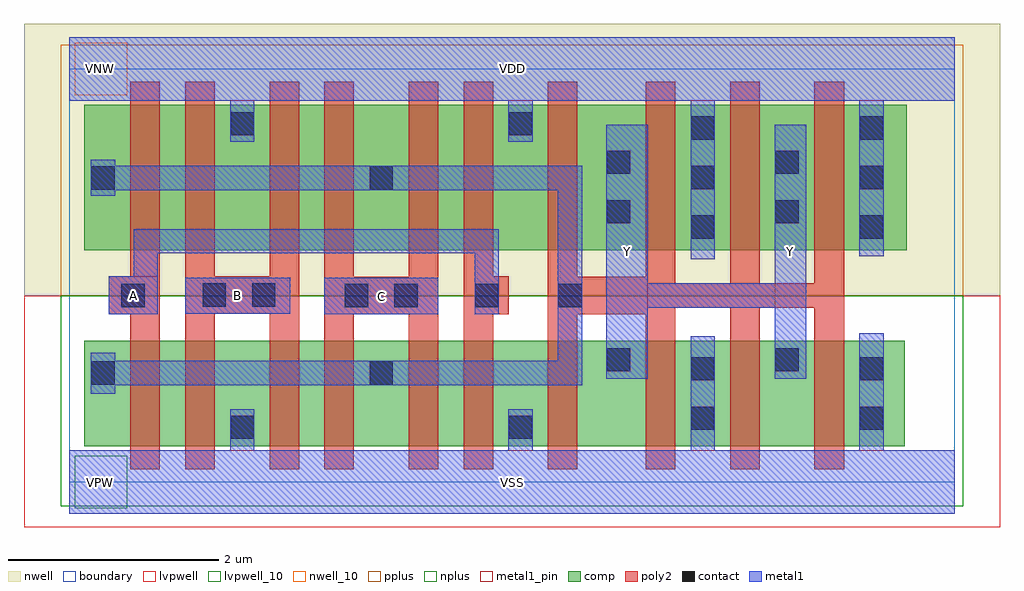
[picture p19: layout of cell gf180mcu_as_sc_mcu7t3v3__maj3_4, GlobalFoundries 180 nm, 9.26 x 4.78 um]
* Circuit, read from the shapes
.subckt gf180mcu_as_sc_mcu7t3v3__maj3_4 A B C VDD VNW VSS Y
XM1 n1 A n2 VSUBS nfet_03v3 w=1u l=0.28u
XM2 VSS B n1 VSUBS nfet_03v3 w=1u l=0.28u
XM3 n3 B VSS VSUBS nfet_03v3 w=1u l=0.28u
XM4 n2 C n3 VSUBS nfet_03v3 w=1u l=0.28u
XM5 n4 C n2 VSUBS nfet_03v3 w=1u l=0.28u
XM6 VSS A n4 VSUBS nfet_03v3 w=1u l=0.28u
XM7 Y n2 VSS VSUBS nfet_03v3 w=1u l=0.28u m=4
XM8 n5 A n2 VNW pfet_03v3 w=1.38u l=0.28u
XM9 VDD B n5 VNW pfet_03v3 w=1.38u l=0.28u
XM10 n6 B VDD VNW pfet_03v3 w=1.38u l=0.28u
XM11 n2 C n6 VNW pfet_03v3 w=1.38u l=0.28u
XM12 n7 C n2 VNW pfet_03v3 w=1.38u l=0.28u
XM13 VDD A n7 VNW pfet_03v3 w=1.38u l=0.28u
XM14 Y n2 VDD VNW pfet_03v3 w=1.38u l=0.28u m=4
.ends

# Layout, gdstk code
import gdstk
lib = gdstk.Library(unit=1e-6, precision=1e-09)
def R(c, l, rs):  # rectangles x0, y0, x1, y1
    for r in rs: c.add(gdstk.rectangle(r[:2], r[2:], *l))
boundary = (0, 0)
nwell = (21, 0)
nwell_10 = (21, 10)
comp = (22, 0)
poly2 = (30, 0)
pplus = (31, 0)
nplus = (32, 0)
contact = (33, 0)
metal1 = (34, 0)
metal1_pin = (34, 10)
lvpwell = (204, 0)
lvpwell_10 = (204, 10)

gf180mcu_as_sc_mcu7t3v3_ = lib.new_cell('gf180mcu_as_sc_mcu7t3v3__maj3_4')
R(gf180mcu_as_sc_mcu7t3v3_, boundary, [(0,0,8.4,3.92), (0,0,8.4,3.92)])
R(gf180mcu_as_sc_mcu7t3v3_, nwell, [(-0.43,1.77,8.83,4.35), (-0.43,1.77,8.83,4.35)])
R(gf180mcu_as_sc_mcu7t3v3_, nwell_10, [(0.05,3.67,0.55,4.17), (0.05,3.67,0.55,4.17)])
R(gf180mcu_as_sc_mcu7t3v3_, comp, [(0.14,0.34,7.925,1.34), (0.14,0.34,7.925,1.34), (0.14,2.2,7.945,3.58), (0.14,2.2,7.945,3.58)])
R(gf180mcu_as_sc_mcu7t3v3_, poly2, [(0.58,0.12,0.86,1.59), (0.58,0.12,0.86,1.59), (1.1,0.12,1.38,1.595), (1.1,0.12,1.38,1.595), (1.9,0.12,2.18,1.595), (1.9,0.12,2.18,1.595), (2.42,0.12,2.7,1.59), (2.42,0.12,2.7,1.59), (3.22,0.12,3.5,1.59), (3.22,0.12,3.5,1.59), (3.74,0.12,4.02,1.59), (3.74,0.12,4.02,1.59), (4.54,0.12,4.82,1.59), (4.54,0.12,4.82,1.59), (5.47,0.12,5.75,1.59), (5.47,0.12,5.75,1.59), (6.27,0.12,6.55,1.655), (6.27,0.12,6.55,1.655), (7.07,0.12,7.35,1.655), (7.07,0.12,7.35,1.655), (0.375,1.59,0.86,1.955), (0.375,1.59,0.86,1.955), (2.42,1.59,3.5,1.95), (2.42,1.59,3.5,1.95), (3.74,1.59,4.17,1.955), (3.74,1.59,4.17,1.955), (4.54,1.59,5.75,1.655), (4.54,1.59,5.75,1.655), (1.1,1.595,2.18,1.955), (1.1,1.595,2.18,1.955), (4.54,1.655,7.35,1.885), (4.54,1.655,7.35,1.885), (4.54,1.885,5.75,1.95), (4.54,1.885,5.75,1.95), (6.27,1.885,6.55,3.8), (6.27,1.885,6.55,3.8), (7.07,1.885,7.35,3.8), (7.07,1.885,7.35,3.8), (2.42,1.95,2.7,3.8), (2.42,1.95,2.7,3.8), (3.22,1.95,3.5,3.8), (3.22,1.95,3.5,3.8), (4.54,1.95,4.82,3.8), (4.54,1.95,4.82,3.8), (5.47,1.95,5.75,3.8), (5.47,1.95,5.75,3.8), (0.58,1.955,0.86,3.8), (0.58,1.955,0.86,3.8), (1.1,1.955,1.38,3.8), (1.1,1.955,1.38,3.8), (1.9,1.955,2.18,3.8), (1.9,1.955,2.18,3.8), (3.74,1.955,4.02,3.8), (3.74,1.955,4.02,3.8)])
R(gf180mcu_as_sc_mcu7t3v3_, pplus, [(-0.08,1.77,8.48,4.15), (-0.08,1.77,8.48,4.15), (0.35,1.97,7.58,2.04), (0.35,1.97,7.58,2.04), (-0.02,2.04,8.105,3.74), (-0.02,2.04,8.105,3.74), (0.35,3.74,7.58,3.81), (0.35,3.74,7.58,3.81)])
R(gf180mcu_as_sc_mcu7t3v3_, nplus, [(-0.08,-0.23,8.48,1.77), (-0.08,-0.23,8.48,1.77), (-0.08,-0.23,8.48,1.77), (-0.08,-0.23,8.48,1.77)])
R(gf180mcu_as_sc_mcu7t3v3_, contact, [(1.53,0.41,1.75,0.63), (1.53,0.41,1.75,0.63), (4.17,0.41,4.39,0.63), (4.17,0.41,4.39,0.63), (5.9,0.495,6.12,0.715), (5.9,0.495,6.12,0.715), (7.5,0.495,7.72,0.715), (7.5,0.495,7.72,0.715), (0.21,0.925,0.43,1.145), (0.21,0.925,0.43,1.145), (2.85,0.925,3.07,1.145), (2.85,0.925,3.07,1.145), (5.9,0.965,6.12,1.185), (5.9,0.965,6.12,1.185), (7.5,0.965,7.72,1.185), (7.5,0.965,7.72,1.185), (5.1,1.05,5.32,1.27), (5.1,1.05,5.32,1.27), (6.7,1.05,6.92,1.27), (6.7,1.05,6.92,1.27), (0.495,1.66,0.715,1.88), (0.495,1.66,0.715,1.88), (2.615,1.66,2.835,1.88), (2.615,1.66,2.835,1.88), (3.085,1.66,3.305,1.88), (3.085,1.66,3.305,1.88), (3.85,1.66,4.07,1.88), (3.85,1.66,4.07,1.88), (4.64,1.66,4.86,1.88), (4.64,1.66,4.86,1.88), (1.265,1.665,1.485,1.885), (1.265,1.665,1.485,1.885), (1.735,1.665,1.955,1.885), (1.735,1.665,1.955,1.885), (5.9,2.31,6.12,2.53), (5.9,2.31,6.12,2.53), (7.5,2.31,7.72,2.53), (7.5,2.31,7.72,2.53), (5.1,2.455,5.32,2.675), (5.1,2.455,5.32,2.675), (6.7,2.455,6.92,2.675), (6.7,2.455,6.92,2.675), (0.21,2.775,0.43,2.995), (0.21,2.775,0.43,2.995), (2.85,2.775,3.07,2.995), (2.85,2.775,3.07,2.995), (5.9,2.78,6.12,3), (5.9,2.78,6.12,3), (7.5,2.78,7.72,3), (7.5,2.78,7.72,3), (5.1,2.925,5.32,3.145), (5.1,2.925,5.32,3.145), (6.7,2.925,6.92,3.145), (6.7,2.925,6.92,3.145), (5.9,3.25,6.12,3.47), (5.9,3.25,6.12,3.47), (7.5,3.25,7.72,3.47), (7.5,3.25,7.72,3.47), (1.53,3.29,1.75,3.51), (1.53,3.29,1.75,3.51), (4.17,3.29,4.39,3.51), (4.17,3.29,4.39,3.51)])
R(gf180mcu_as_sc_mcu7t3v3_, metal1, [(0,-0.3,8.4,0.3), (0,-0.3,8.4,0.3), (1.525,0.3,1.755,0.69), (1.525,0.3,1.755,0.69), (4.165,0.3,4.395,0.69), (4.165,0.3,4.395,0.69), (5.895,0.3,6.125,1.385), (5.895,0.3,6.125,1.385), (7.495,0.3,7.725,1.41), (7.495,0.3,7.725,1.41), (0.205,0.84,0.435,0.92), (0.205,0.84,0.435,0.92), (0.205,0.92,4.865,1.15), (0.205,0.92,4.865,1.15), (5.095,0.98,5.49,1.655), (5.095,0.98,5.49,1.655), (6.695,0.98,6.99,1.655), (6.695,0.98,6.99,1.655), (0.205,1.15,0.435,1.225), (0.205,1.15,0.435,1.225), (4.635,1.15,4.865,2.77), (4.635,1.15,4.865,2.77), (0.375,1.59,0.84,1.955), (0.375,1.59,0.84,1.955), (2.42,1.59,3.5,1.94), (2.42,1.59,3.5,1.94), (3.845,1.59,4.075,2.17), (3.845,1.59,4.075,2.17), (1.1,1.595,2.095,1.94), (1.1,1.595,2.095,1.94), (5.095,1.655,6.99,1.885), (5.095,1.655,6.99,1.885), (5.095,1.885,5.49,3.39), (5.095,1.885,5.49,3.39), (6.695,1.885,6.99,3.39), (6.695,1.885,6.99,3.39), (0.61,1.955,0.84,2.17), (0.61,1.955,0.84,2.17), (5.895,2.115,6.125,3.62), (5.895,2.115,6.125,3.62), (7.495,2.145,7.725,3.62), (7.495,2.145,7.725,3.62), (0.61,2.17,4.075,2.4), (0.61,2.17,4.075,2.4), (0.205,2.715,0.435,2.77), (0.205,2.715,0.435,2.77), (0.205,2.77,4.865,3), (0.205,2.77,4.865,3), (0.205,3,0.435,3.06), (0.205,3,0.435,3.06), (1.525,3.23,1.755,3.62), (1.525,3.23,1.755,3.62), (4.165,3.23,4.395,3.62), (4.165,3.23,4.395,3.62), (0,3.62,8.4,4.22), (0,3.62,8.4,4.22)])
R(gf180mcu_as_sc_mcu7t3v3_, metal1_pin, [(0,-0.3,8.4,0.3), (0,-0.3,8.4,0.3), (5.095,0.98,5.49,3.39), (5.095,0.98,5.49,3.39), (6.695,0.98,6.99,3.39), (6.695,0.98,6.99,3.39), (0.375,1.59,0.84,1.955), (0.375,1.59,0.84,1.955), (2.42,1.59,3.5,1.94), (2.42,1.59,3.5,1.94), (1.1,1.595,2.095,1.94), (1.1,1.595,2.095,1.94), (0,3.62,8.4,4.22), (0,3.62,8.4,4.22)])
R(gf180mcu_as_sc_mcu7t3v3_, lvpwell, [(-0.43,-0.43,8.83,1.77), (-0.43,-0.43,8.83,1.77)])
R(gf180mcu_as_sc_mcu7t3v3_, lvpwell_10, [(0.05,-0.25,0.55,0.25), (0.05,-0.25,0.55,0.25)])
gf180mcu_as_sc_mcu7t3v3_.add(gdstk.Label('VDD', (4.2,3.92), layer=34, texttype=10))
gf180mcu_as_sc_mcu7t3v3_.add(gdstk.Label('VSS', (4.2,0), layer=34, texttype=10))
gf180mcu_as_sc_mcu7t3v3_.add(gdstk.Label('Y', (6.842,2.185), layer=34, texttype=10))
gf180mcu_as_sc_mcu7t3v3_.add(gdstk.Label('Y', (5.292,2.185), layer=34, texttype=10))
gf180mcu_as_sc_mcu7t3v3_.add(gdstk.Label('A', (0.607,1.772), layer=34, texttype=10))
gf180mcu_as_sc_mcu7t3v3_.add(gdstk.Label('B', (1.597,1.767), layer=34, texttype=10))
gf180mcu_as_sc_mcu7t3v3_.add(gdstk.Label('C', (2.96,1.765), layer=34, texttype=10))
gf180mcu_as_sc_mcu7t3v3_.add(gdstk.Label('VDD', (4.2,3.92), layer=34, texttype=10))
gf180mcu_as_sc_mcu7t3v3_.add(gdstk.Label('VSS', (4.2,0), layer=34, texttype=10))
gf180mcu_as_sc_mcu7t3v3_.add(gdstk.Label('Y', (6.842,2.185), layer=34, texttype=10))
gf180mcu_as_sc_mcu7t3v3_.add(gdstk.Label('Y', (5.292,2.185), layer=34, texttype=10))
gf180mcu_as_sc_mcu7t3v3_.add(gdstk.Label('A', (0.607,1.772), layer=34, texttype=10))
gf180mcu_as_sc_mcu7t3v3_.add(gdstk.Label('B', (1.597,1.767), layer=34, texttype=10))
gf180mcu_as_sc_mcu7t3v3_.add(gdstk.Label('C', (2.96,1.765), layer=34, texttype=10))
gf180mcu_as_sc_mcu7t3v3_.add(gdstk.Label('VNW', (0.3,3.92), layer=21, texttype=10))
gf180mcu_as_sc_mcu7t3v3_.add(gdstk.Label('VNW', (0.3,3.92), layer=21, texttype=10))
gf180mcu_as_sc_mcu7t3v3_.add(gdstk.Label('VPW', (0.3,0), layer=204, texttype=10))
gf180mcu_as_sc_mcu7t3v3_.add(gdstk.Label('VPW', (0.3,0), layer=204, texttype=10))

lib.write_gds('gf180mcu_as_sc_mcu7t3v3__maj3_4.gds')
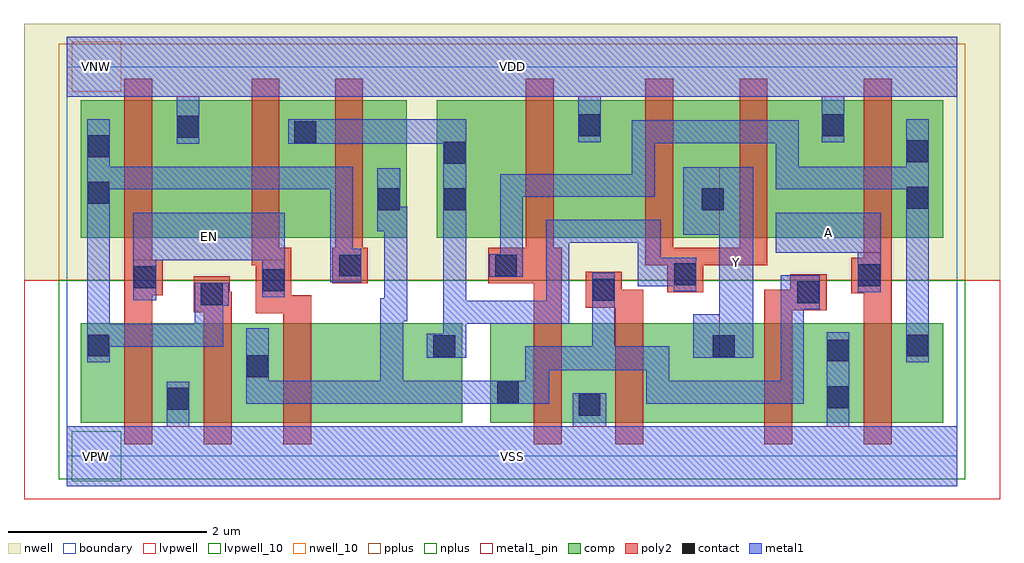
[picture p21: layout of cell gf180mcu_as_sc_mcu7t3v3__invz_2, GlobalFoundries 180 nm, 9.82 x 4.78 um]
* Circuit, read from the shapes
.subckt gf180mcu_as_sc_mcu7t3v3__invz_2 A EN VDD VNW VSS Y
XM1 VSS EN n1 VSUBS nfet_03v3 w=1u l=0.28u
XM2 n2 n1 VSS VSUBS nfet_03v3 w=1u l=0.28u
XM3 n3 EN n2 VSUBS nfet_03v3 w=1u l=0.28u
XM4 VSS n4 n2 VSUBS nfet_03v3 w=1u l=0.28u
XM5 Y n2 VSS VSUBS nfet_03v3 w=1u l=0.28u m=2
XM6 n4 A VSS VSUBS nfet_03v3 w=1u l=0.28u
XM7 VDD EN n1 VNW pfet_03v3 w=1.38u l=0.28u
XM8 n3 EN VDD VNW pfet_03v3 w=1.38u l=0.28u
XM9 n2 n1 n3 VNW pfet_03v3 w=1.38u l=0.28u
XM10 VDD n4 n3 VNW pfet_03v3 w=1.38u l=0.28u
XM11 Y n3 VDD VNW pfet_03v3 w=1.38u l=0.28u m=2
XM12 n4 A VDD VNW pfet_03v3 w=1.38u l=0.28u
.ends

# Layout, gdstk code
import gdstk
lib = gdstk.Library(unit=1e-6, precision=1e-09)
def R(c, l, rs):  # rectangles x0, y0, x1, y1
    for r in rs: c.add(gdstk.rectangle(r[:2], r[2:], *l))
boundary = (0, 0)
nwell = (21, 0)
nwell_10 = (21, 10)
comp = (22, 0)
poly2 = (30, 0)
pplus = (31, 0)
nplus = (32, 0)
contact = (33, 0)
metal1 = (34, 0)
metal1_pin = (34, 10)
lvpwell = (204, 0)
lvpwell_10 = (204, 10)

gf180mcu_as_sc_mcu7t3v3_ = lib.new_cell('gf180mcu_as_sc_mcu7t3v3__invz_2')
R(gf180mcu_as_sc_mcu7t3v3_, boundary, [(0,0,8.96,3.92), (0,0,8.96,3.92)])
R(gf180mcu_as_sc_mcu7t3v3_, nwell, [(-0.43,1.77,9.39,4.35), (-0.43,1.77,9.39,4.35)])
R(gf180mcu_as_sc_mcu7t3v3_, nwell_10, [(0.05,3.67,0.55,4.17), (0.05,3.67,0.55,4.17)])
R(gf180mcu_as_sc_mcu7t3v3_, comp, [(0.14,0.34,3.98,1.34), (0.14,0.34,3.98,1.34), (4.26,0.34,8.82,1.34), (4.26,0.34,8.82,1.34), (0.14,2.2,3.42,3.58), (0.14,2.2,3.42,3.58), (3.725,2.2,8.82,3.58), (3.725,2.2,8.82,3.58)])
R(gf180mcu_as_sc_mcu7t3v3_, poly2, [(0.58,0.12,0.86,1.62), (0.58,0.12,0.86,1.62), (1.38,0.12,1.66,1.45), (1.38,0.12,1.66,1.45), (2.18,0.12,2.46,1.44), (2.18,0.12,2.46,1.44), (4.7,0.12,4.98,1.74), (4.7,0.12,4.98,1.74), (5.52,0.12,5.8,1.495), (5.52,0.12,5.8,1.495), (7.02,0.12,7.3,1.47), (7.02,0.12,7.3,1.47), (8.02,0.12,8.3,1.64), (8.02,0.12,8.3,1.64), (1.9,1.44,2.46,1.62), (1.9,1.44,2.46,1.62), (1.28,1.45,1.66,1.655), (1.28,1.45,1.66,1.655), (7.02,1.47,7.645,1.675), (7.02,1.47,7.645,1.675), (5.22,1.495,5.8,1.675), (5.22,1.495,5.8,1.675), (0.58,1.62,0.965,1.98), (0.58,1.62,0.965,1.98), (1.9,1.62,2.26,1.92), (1.9,1.62,2.26,1.92), (7.895,1.64,8.3,2), (7.895,1.64,8.3,2), (6.04,1.65,6.405,1.92), (6.04,1.65,6.405,1.92), (1.28,1.655,1.64,1.81), (1.28,1.655,1.64,1.81), (5.22,1.675,5.585,1.855), (5.22,1.675,5.585,1.855), (7.28,1.675,7.645,1.83), (7.28,1.675,7.645,1.83), (2.67,1.74,3.03,2.1), (2.67,1.74,3.03,2.1), (4.24,1.74,4.98,2.1), (4.24,1.74,4.98,2.1), (1.86,1.92,2.26,2.1), (1.86,1.92,2.26,2.1), (5.82,1.92,7.05,2.1), (5.82,1.92,7.05,2.1), (0.58,1.98,0.86,3.8), (0.58,1.98,0.86,3.8), (8.02,2,8.3,3.8), (8.02,2,8.3,3.8), (1.86,2.1,2.14,3.8), (1.86,2.1,2.14,3.8), (2.7,2.1,2.98,3.8), (2.7,2.1,2.98,3.8), (4.62,2.1,4.9,3.8), (4.62,2.1,4.9,3.8), (5.82,2.1,6.1,3.8), (5.82,2.1,6.1,3.8), (6.77,2.1,7.05,3.8), (6.77,2.1,7.05,3.8)])
R(gf180mcu_as_sc_mcu7t3v3_, pplus, [(-0.08,1.77,9.04,4.15), (-0.08,1.77,9.04,4.15), (0.35,1.97,1.09,2.04), (0.35,1.97,1.09,2.04), (1.63,1.97,3.21,2.04), (1.63,1.97,3.21,2.04), (4.39,1.97,5.13,2.04), (4.39,1.97,5.13,2.04), (5.59,1.97,7.28,2.04), (5.59,1.97,7.28,2.04), (7.79,1.97,8.53,2.04), (7.79,1.97,8.53,2.04), (-0.02,2.04,8.98,3.74), (-0.02,2.04,8.98,3.74), (0.35,3.74,1.09,3.81), (0.35,3.74,1.09,3.81), (1.63,3.74,3.21,3.81), (1.63,3.74,3.21,3.81), (4.39,3.74,5.13,3.81), (4.39,3.74,5.13,3.81), (5.59,3.74,7.28,3.81), (5.59,3.74,7.28,3.81), (7.79,3.74,8.53,3.81), (7.79,3.74,8.53,3.81)])
R(gf180mcu_as_sc_mcu7t3v3_, nplus, [(-0.08,-0.23,9.04,1.77), (-0.08,-0.23,9.04,1.77), (-0.08,-0.23,9.04,1.77), (-0.08,-0.23,9.04,1.77)])
R(gf180mcu_as_sc_mcu7t3v3_, contact, [(5.15,0.41,5.37,0.63), (5.15,0.41,5.37,0.63), (1.01,0.47,1.23,0.69), (1.01,0.47,1.23,0.69), (7.65,0.485,7.87,0.705), (7.65,0.485,7.87,0.705), (4.33,0.535,4.55,0.755), (4.33,0.535,4.55,0.755), (1.81,0.795,2.03,1.015), (1.81,0.795,2.03,1.015), (7.65,0.955,7.87,1.175), (7.65,0.955,7.87,1.175), (3.69,1,3.91,1.22), (3.69,1,3.91,1.22), (6.5,1,6.72,1.22), (6.5,1,6.72,1.22), (0.21,1.005,0.43,1.225), (0.21,1.005,0.43,1.225), (8.45,1.005,8.67,1.225), (8.45,1.005,8.67,1.225), (1.35,1.52,1.57,1.74), (1.35,1.52,1.57,1.74), (7.35,1.54,7.57,1.76), (7.35,1.54,7.57,1.76), (5.29,1.565,5.51,1.785), (5.29,1.565,5.51,1.785), (1.97,1.66,2.19,1.88), (1.97,1.66,2.19,1.88), (0.675,1.69,0.895,1.91), (0.675,1.69,0.895,1.91), (7.965,1.71,8.185,1.93), (7.965,1.71,8.185,1.93), (6.11,1.72,6.33,1.94), (6.11,1.72,6.33,1.94), (2.74,1.81,2.96,2.03), (2.74,1.81,2.96,2.03), (4.31,1.81,4.53,2.03), (4.31,1.81,4.53,2.03), (3.13,2.475,3.35,2.695), (3.13,2.475,3.35,2.695), (3.795,2.475,4.015,2.695), (3.795,2.475,4.015,2.695), (6.39,2.475,6.61,2.695), (6.39,2.475,6.61,2.695), (8.45,2.49,8.67,2.71), (8.45,2.49,8.67,2.71), (0.21,2.54,0.43,2.76), (0.21,2.54,0.43,2.76), (3.795,2.945,4.015,3.165), (3.795,2.945,4.015,3.165), (8.45,2.96,8.67,3.18), (8.45,2.96,8.67,3.18), (0.21,3.01,0.43,3.23), (0.21,3.01,0.43,3.23), (2.29,3.15,2.51,3.37), (2.29,3.15,2.51,3.37), (1.11,3.205,1.33,3.425), (1.11,3.205,1.33,3.425), (5.15,3.22,5.37,3.44), (5.15,3.22,5.37,3.44), (7.6,3.22,7.82,3.44), (7.6,3.22,7.82,3.44)])
R(gf180mcu_as_sc_mcu7t3v3_, metal1, [(0,-0.3,8.96,0.3), (0,-0.3,8.96,0.3), (1.005,0.3,1.235,0.75), (1.005,0.3,1.235,0.75), (5.09,0.3,5.43,0.635), (5.09,0.3,5.43,0.635), (7.645,0.3,7.875,1.25), (7.645,0.3,7.875,1.25), (1.805,0.53,4.855,0.76), (1.805,0.53,4.855,0.76), (5.83,0.53,7.415,0.76), (5.83,0.53,7.415,0.76), (1.805,0.76,2.035,1.29), (1.805,0.76,2.035,1.29), (3.155,0.76,3.385,1.36), (3.155,0.76,3.385,1.36), (4.615,0.76,4.855,0.865), (4.615,0.76,4.855,0.865), (5.83,0.76,6.06,0.865), (5.83,0.76,6.06,0.865), (7.185,0.76,7.415,1.48), (7.185,0.76,7.415,1.48), (4.615,0.865,6.06,1.105), (4.615,0.865,6.06,1.105), (0.205,0.945,0.435,1.1), (0.205,0.945,0.435,1.1), (8.445,0.945,8.675,2.685), (8.445,0.945,8.675,2.685), (3.62,0.99,4.02,1.235), (3.62,0.99,4.02,1.235), (6.305,0.99,6.905,1.43), (6.305,0.99,6.905,1.43), (0.205,1.1,1.575,1.335), (0.205,1.1,1.575,1.335), (5.285,1.105,5.515,1.845), (5.285,1.105,5.515,1.845), (3.79,1.235,4.02,1.335), (3.79,1.235,4.02,1.335), (0.205,1.335,0.435,2.685), (0.205,1.335,0.435,2.685), (1.29,1.335,1.575,1.515), (1.29,1.335,1.575,1.515), (3.79,1.335,5.055,1.565), (3.79,1.335,5.055,1.565), (3.155,1.36,3.425,1.59), (3.155,1.36,3.425,1.59), (6.565,1.43,6.905,2.23), (6.565,1.43,6.905,2.23), (7.185,1.48,7.575,1.82), (7.185,1.48,7.575,1.82), (1.29,1.515,1.63,1.745), (1.29,1.515,1.63,1.745), (3.79,1.565,4.02,3.145), (3.79,1.565,4.02,3.145), (4.825,1.565,5.055,2.15), (4.825,1.565,5.055,2.15), (0.67,1.57,0.9,1.975), (0.67,1.57,0.9,1.975), (3.195,1.59,3.425,2.265), (3.195,1.59,3.425,2.265), (1.965,1.6,2.195,1.975), (1.965,1.6,2.195,1.975), (7.96,1.65,8.19,2.05), (7.96,1.65,8.19,2.05), (6.105,1.66,6.335,1.71), (6.105,1.66,6.335,1.71), (5.745,1.71,6.335,2), (5.745,1.71,6.335,2), (2.65,1.75,2.965,2.09), (2.65,1.75,2.965,2.09), (4.25,1.805,4.59,2.035), (4.25,1.805,4.59,2.035), (0.67,1.975,2.195,2.45), (0.67,1.975,2.195,2.45), (5.745,2,5.975,2.15), (5.745,2,5.975,2.15), (4.36,2.035,4.59,2.61), (4.36,2.035,4.59,2.61), (7.135,2.05,8.19,2.45), (7.135,2.05,8.19,2.45), (2.65,2.09,2.88,2.685), (2.65,2.09,2.88,2.685), (4.825,2.15,5.975,2.38), (4.825,2.15,5.975,2.38), (6.205,2.23,6.905,2.91), (6.205,2.23,6.905,2.91), (3.125,2.265,3.425,2.51), (3.125,2.265,3.425,2.51), (3.125,2.51,3.355,2.9), (3.125,2.51,3.355,2.9), (4.36,2.61,5.915,2.84), (4.36,2.61,5.915,2.84), (0.205,2.685,2.88,2.915), (0.205,2.685,2.88,2.915), (7.135,2.685,8.675,2.915), (7.135,2.685,8.675,2.915), (5.685,2.84,5.915,3.15), (5.685,2.84,5.915,3.15), (0.205,2.915,0.435,3.39), (0.205,2.915,0.435,3.39), (7.135,2.915,7.365,3.15), (7.135,2.915,7.365,3.15), (8.445,2.915,8.675,3.39), (8.445,2.915,8.675,3.39), (1.105,3.145,1.335,3.62), (1.105,3.145,1.335,3.62), (2.23,3.145,4.02,3.39), (2.23,3.145,4.02,3.39), (5.685,3.15,7.365,3.38), (5.685,3.15,7.365,3.38), (5.145,3.16,5.375,3.62), (5.145,3.16,5.375,3.62), (7.595,3.16,7.825,3.62), (7.595,3.16,7.825,3.62), (0,3.62,8.96,4.22), (0,3.62,8.96,4.22)])
R(gf180mcu_as_sc_mcu7t3v3_, metal1_pin, [(0,-0.3,8.96,0.3), (0,-0.3,8.96,0.3), (6.565,0.99,6.905,2.91), (6.565,0.99,6.905,2.91), (0.67,1.975,2.195,2.45), (0.67,1.975,2.195,2.45), (7.135,2.05,8.19,2.45), (7.135,2.05,8.19,2.45), (0,3.62,8.96,4.22), (0,3.62,8.96,4.22)])
R(gf180mcu_as_sc_mcu7t3v3_, lvpwell, [(-0.43,-0.43,9.39,1.77), (-0.43,-0.43,9.39,1.77)])
R(gf180mcu_as_sc_mcu7t3v3_, lvpwell_10, [(0.05,-0.25,0.55,0.25), (0.05,-0.25,0.55,0.25)])
gf180mcu_as_sc_mcu7t3v3_.add(gdstk.Label('VDD', (4.48,3.92), layer=34, texttype=10))
gf180mcu_as_sc_mcu7t3v3_.add(gdstk.Label('VSS', (4.48,0), layer=34, texttype=10))
gf180mcu_as_sc_mcu7t3v3_.add(gdstk.Label('EN', (1.432,2.212), layer=34, texttype=10))
gf180mcu_as_sc_mcu7t3v3_.add(gdstk.Label('A', (7.662,2.25), layer=34, texttype=10))
gf180mcu_as_sc_mcu7t3v3_.add(gdstk.Label('Y', (6.735,1.95), layer=34, texttype=10))
gf180mcu_as_sc_mcu7t3v3_.add(gdstk.Label('VDD', (4.48,3.92), layer=34, texttype=10))
gf180mcu_as_sc_mcu7t3v3_.add(gdstk.Label('VSS', (4.48,0), layer=34, texttype=10))
gf180mcu_as_sc_mcu7t3v3_.add(gdstk.Label('EN', (1.432,2.212), layer=34, texttype=10))
gf180mcu_as_sc_mcu7t3v3_.add(gdstk.Label('A', (7.662,2.25), layer=34, texttype=10))
gf180mcu_as_sc_mcu7t3v3_.add(gdstk.Label('Y', (6.735,1.95), layer=34, texttype=10))
gf180mcu_as_sc_mcu7t3v3_.add(gdstk.Label('VNW', (0.3,3.92), layer=21, texttype=10))
gf180mcu_as_sc_mcu7t3v3_.add(gdstk.Label('VNW', (0.3,3.92), layer=21, texttype=10))
gf180mcu_as_sc_mcu7t3v3_.add(gdstk.Label('VPW', (0.3,0), layer=204, texttype=10))
gf180mcu_as_sc_mcu7t3v3_.add(gdstk.Label('VPW', (0.3,0), layer=204, texttype=10))

lib.write_gds('gf180mcu_as_sc_mcu7t3v3__invz_2.gds')
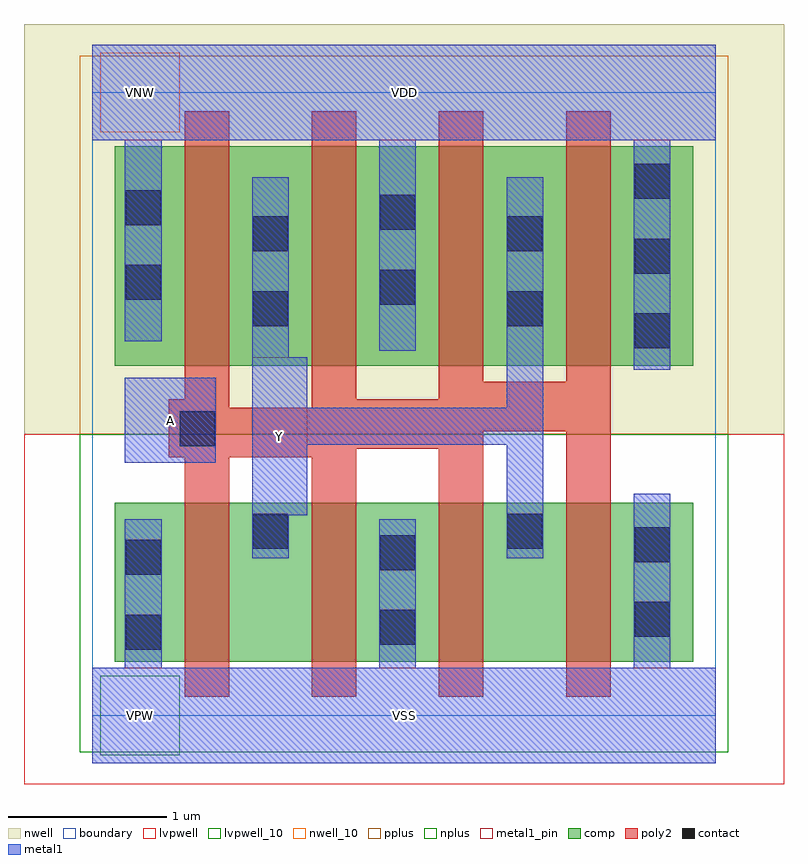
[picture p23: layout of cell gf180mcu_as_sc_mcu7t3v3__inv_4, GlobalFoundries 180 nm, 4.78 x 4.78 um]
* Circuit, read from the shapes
.subckt gf180mcu_as_sc_mcu7t3v3__inv_4 A VDD VNW VSS Y
XM1 Y A VSS VSUBS nfet_03v3 w=1u l=0.28u m=4
XM2 Y A VDD VNW pfet_03v3 w=1.38u l=0.28u m=4
.ends

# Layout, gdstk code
import gdstk
lib = gdstk.Library(unit=1e-6, precision=1e-09)
def R(c, l, rs):  # rectangles x0, y0, x1, y1
    for r in rs: c.add(gdstk.rectangle(r[:2], r[2:], *l))
boundary = (0, 0)
nwell = (21, 0)
nwell_10 = (21, 10)
comp = (22, 0)
poly2 = (30, 0)
pplus = (31, 0)
nplus = (32, 0)
contact = (33, 0)
metal1 = (34, 0)
metal1_pin = (34, 10)
lvpwell = (204, 0)
lvpwell_10 = (204, 10)

gf180mcu_as_sc_mcu7t3v3_ = lib.new_cell('gf180mcu_as_sc_mcu7t3v3__inv_4')
R(gf180mcu_as_sc_mcu7t3v3_, boundary, [(0,0,3.92,3.92), (0,0,3.92,3.92)])
R(gf180mcu_as_sc_mcu7t3v3_, nwell, [(-0.43,1.77,4.35,4.35), (-0.43,1.77,4.35,4.35)])
R(gf180mcu_as_sc_mcu7t3v3_, nwell_10, [(0.05,3.67,0.55,4.17), (0.05,3.67,0.55,4.17)])
R(gf180mcu_as_sc_mcu7t3v3_, comp, [(0.14,0.34,3.78,1.34), (0.14,0.34,3.78,1.34), (0.14,2.2,3.78,3.58), (0.14,2.2,3.78,3.58)])
R(gf180mcu_as_sc_mcu7t3v3_, poly2, [(0.58,0.12,0.86,1.625), (0.58,0.12,0.86,1.625), (1.38,0.12,1.66,1.625), (1.38,0.12,1.66,1.625), (2.18,0.12,2.46,1.68), (2.18,0.12,2.46,1.68), (2.98,0.12,3.26,1.79), (2.98,0.12,3.26,1.79), (0.48,1.625,1.66,1.68), (0.48,1.625,1.66,1.68), (0.48,1.68,2.46,1.79), (0.48,1.68,2.46,1.79), (0.48,1.79,3.26,1.935), (0.48,1.79,3.26,1.935), (0.48,1.935,0.86,1.99), (0.48,1.935,0.86,1.99), (1.38,1.935,3.26,1.99), (1.38,1.935,3.26,1.99), (0.58,1.99,0.86,3.8), (0.58,1.99,0.86,3.8), (1.38,1.99,1.66,3.8), (1.38,1.99,1.66,3.8), (2.18,1.99,3.26,2.1), (2.18,1.99,3.26,2.1), (2.18,2.1,2.46,3.8), (2.18,2.1,2.46,3.8), (2.98,2.1,3.26,3.8), (2.98,2.1,3.26,3.8)])
R(gf180mcu_as_sc_mcu7t3v3_, pplus, [(-0.08,1.77,4,4.15), (-0.08,1.77,4,4.15), (0.35,1.97,3.49,2.04), (0.35,1.97,3.49,2.04), (-0.02,2.04,3.94,3.74), (-0.02,2.04,3.94,3.74), (0.35,3.74,3.49,3.81), (0.35,3.74,3.49,3.81)])
R(gf180mcu_as_sc_mcu7t3v3_, nplus, [(-0.08,-0.23,4,1.77), (-0.08,-0.23,4,1.77), (-0.08,-0.23,4,1.77), (-0.08,-0.23,4,1.77)])
R(gf180mcu_as_sc_mcu7t3v3_, contact, [(0.21,0.415,0.43,0.635), (0.21,0.415,0.43,0.635), (1.81,0.445,2.03,0.665), (1.81,0.445,2.03,0.665), (3.41,0.495,3.63,0.715), (3.41,0.495,3.63,0.715), (0.21,0.885,0.43,1.105), (0.21,0.885,0.43,1.105), (1.81,0.915,2.03,1.135), (1.81,0.915,2.03,1.135), (3.41,0.965,3.63,1.185), (3.41,0.965,3.63,1.185), (1.01,1.05,1.23,1.27), (1.01,1.05,1.23,1.27), (2.61,1.05,2.83,1.27), (2.61,1.05,2.83,1.27), (0.55,1.695,0.77,1.915), (0.55,1.695,0.77,1.915), (3.41,2.31,3.63,2.53), (3.41,2.31,3.63,2.53), (1.01,2.45,1.23,2.67), (1.01,2.45,1.23,2.67), (2.61,2.45,2.83,2.67), (2.61,2.45,2.83,2.67), (1.81,2.585,2.03,2.805), (1.81,2.585,2.03,2.805), (0.21,2.615,0.43,2.835), (0.21,2.615,0.43,2.835), (3.41,2.78,3.63,3), (3.41,2.78,3.63,3), (1.01,2.92,1.23,3.14), (1.01,2.92,1.23,3.14), (2.61,2.92,2.83,3.14), (2.61,2.92,2.83,3.14), (1.81,3.055,2.03,3.275), (1.81,3.055,2.03,3.275), (0.21,3.085,0.43,3.305), (0.21,3.085,0.43,3.305), (3.41,3.25,3.63,3.47), (3.41,3.25,3.63,3.47)])
R(gf180mcu_as_sc_mcu7t3v3_, metal1, [(0,-0.3,3.92,0.3), (0,-0.3,3.92,0.3), (0.205,0.3,0.435,1.235), (0.205,0.3,0.435,1.235), (1.805,0.3,2.035,1.235), (1.805,0.3,2.035,1.235), (3.405,0.3,3.635,1.395), (3.405,0.3,3.635,1.395), (1.005,0.99,1.235,1.26), (1.005,0.99,1.235,1.26), (2.605,0.99,2.835,1.705), (2.605,0.99,2.835,1.705), (1.005,1.26,1.35,1.705), (1.005,1.26,1.35,1.705), (0.205,1.59,0.775,2.125), (0.205,1.59,0.775,2.125), (1.005,1.705,2.835,1.935), (1.005,1.705,2.835,1.935), (1.005,1.935,1.35,2.255), (1.005,1.935,1.35,2.255), (2.605,1.935,2.835,3.385), (2.605,1.935,2.835,3.385), (3.405,2.175,3.635,3.62), (3.405,2.175,3.635,3.62), (1.005,2.255,1.235,3.385), (1.005,2.255,1.235,3.385), (1.805,2.295,2.035,3.62), (1.805,2.295,2.035,3.62), (0.205,2.355,0.435,3.62), (0.205,2.355,0.435,3.62), (0,3.62,3.92,4.22), (0,3.62,3.92,4.22)])
R(gf180mcu_as_sc_mcu7t3v3_, metal1_pin, [(0,-0.3,3.92,0.3), (0,-0.3,3.92,0.3), (1.005,1.26,1.35,2.255), (1.005,1.26,1.35,2.255), (0.205,1.59,0.775,2.125), (0.205,1.59,0.775,2.125), (0,3.62,3.92,4.22), (0,3.62,3.92,4.22)])
R(gf180mcu_as_sc_mcu7t3v3_, lvpwell, [(-0.43,-0.43,4.35,1.77), (-0.43,-0.43,4.35,1.77)])
R(gf180mcu_as_sc_mcu7t3v3_, lvpwell_10, [(0.05,-0.25,0.55,0.25), (0.05,-0.25,0.55,0.25)])
gf180mcu_as_sc_mcu7t3v3_.add(gdstk.Label('VDD', (1.96,3.92), layer=34, texttype=10))
gf180mcu_as_sc_mcu7t3v3_.add(gdstk.Label('VSS', (1.96,0), layer=34, texttype=10))
gf180mcu_as_sc_mcu7t3v3_.add(gdstk.Label('Y', (1.177,1.757), layer=34, texttype=10))
gf180mcu_as_sc_mcu7t3v3_.add(gdstk.Label('A', (0.49,1.857), layer=34, texttype=10))
gf180mcu_as_sc_mcu7t3v3_.add(gdstk.Label('VDD', (1.96,3.92), layer=34, texttype=10))
gf180mcu_as_sc_mcu7t3v3_.add(gdstk.Label('VSS', (1.96,0), layer=34, texttype=10))
gf180mcu_as_sc_mcu7t3v3_.add(gdstk.Label('Y', (1.177,1.757), layer=34, texttype=10))
gf180mcu_as_sc_mcu7t3v3_.add(gdstk.Label('A', (0.49,1.857), layer=34, texttype=10))
gf180mcu_as_sc_mcu7t3v3_.add(gdstk.Label('VNW', (0.3,3.92), layer=21, texttype=10))
gf180mcu_as_sc_mcu7t3v3_.add(gdstk.Label('VNW', (0.3,3.92), layer=21, texttype=10))
gf180mcu_as_sc_mcu7t3v3_.add(gdstk.Label('VPW', (0.3,0), layer=204, texttype=10))
gf180mcu_as_sc_mcu7t3v3_.add(gdstk.Label('VPW', (0.3,0), layer=204, texttype=10))

lib.write_gds('gf180mcu_as_sc_mcu7t3v3__inv_4.gds')
